VERSION 5.8 ;
BUSBITCHARS "[]" ;
DIVIDERCHAR "/" ;
UNITS
    DATABASE MICRONS 1000 ;
END UNITS

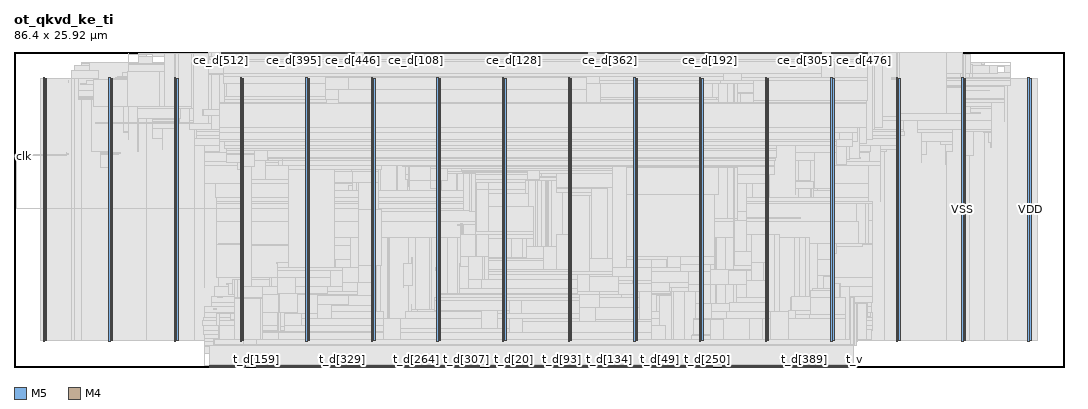
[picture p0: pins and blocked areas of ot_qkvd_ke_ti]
MACRO ot_qkvd_ke_ti
  FOREIGN ot_qkvd_ke_ti 0 0 ;
  CLASS BLOCK ;
  SIZE 86.4 BY 25.92 ;
  PIN ce_d[0]
    DIRECTION OUTPUT ;
    USE SIGNAL ;
    PORT
      LAYER M5 ;
        RECT  34.992 25.836 35.016 25.92 ;
    END
  END ce_d[0]
  PIN ce_d[100]
    DIRECTION OUTPUT ;
    USE SIGNAL ;
    PORT
      LAYER M5 ;
        RECT  32.304 25.836 32.328 25.92 ;
    END
  END ce_d[100]
  PIN ce_d[101]
    DIRECTION OUTPUT ;
    USE SIGNAL ;
    PORT
      LAYER M5 ;
        RECT  32.4 25.836 32.424 25.92 ;
    END
  END ce_d[101]
  PIN ce_d[102]
    DIRECTION OUTPUT ;
    USE SIGNAL ;
    PORT
      LAYER M5 ;
        RECT  32.496 25.836 32.52 25.92 ;
    END
  END ce_d[102]
  PIN ce_d[103]
    DIRECTION OUTPUT ;
    USE SIGNAL ;
    PORT
      LAYER M5 ;
        RECT  32.592 25.836 32.616 25.92 ;
    END
  END ce_d[103]
  PIN ce_d[104]
    DIRECTION OUTPUT ;
    USE SIGNAL ;
    PORT
      LAYER M5 ;
        RECT  32.688 25.836 32.712 25.92 ;
    END
  END ce_d[104]
  PIN ce_d[105]
    DIRECTION OUTPUT ;
    USE SIGNAL ;
    PORT
      LAYER M5 ;
        RECT  32.784 25.836 32.808 25.92 ;
    END
  END ce_d[105]
  PIN ce_d[106]
    DIRECTION OUTPUT ;
    USE SIGNAL ;
    PORT
      LAYER M5 ;
        RECT  32.88 25.836 32.904 25.92 ;
    END
  END ce_d[106]
  PIN ce_d[107]
    DIRECTION OUTPUT ;
    USE SIGNAL ;
    PORT
      LAYER M5 ;
        RECT  32.976 25.836 33 25.92 ;
    END
  END ce_d[107]
  PIN ce_d[108]
    DIRECTION OUTPUT ;
    USE SIGNAL ;
    PORT
      LAYER M5 ;
        RECT  33.072 25.836 33.096 25.92 ;
    END
  END ce_d[108]
  PIN ce_d[109]
    DIRECTION OUTPUT ;
    USE SIGNAL ;
    PORT
      LAYER M5 ;
        RECT  33.168 25.836 33.192 25.92 ;
    END
  END ce_d[109]
  PIN ce_d[10]
    DIRECTION OUTPUT ;
    USE SIGNAL ;
    PORT
      LAYER M5 ;
        RECT  35.952 25.836 35.976 25.92 ;
    END
  END ce_d[10]
  PIN ce_d[110]
    DIRECTION OUTPUT ;
    USE SIGNAL ;
    PORT
      LAYER M5 ;
        RECT  33.264 25.836 33.288 25.92 ;
    END
  END ce_d[110]
  PIN ce_d[111]
    DIRECTION OUTPUT ;
    USE SIGNAL ;
    PORT
      LAYER M5 ;
        RECT  33.36 25.836 33.384 25.92 ;
    END
  END ce_d[111]
  PIN ce_d[112]
    DIRECTION OUTPUT ;
    USE SIGNAL ;
    PORT
      LAYER M5 ;
        RECT  33.456 25.836 33.48 25.92 ;
    END
  END ce_d[112]
  PIN ce_d[113]
    DIRECTION OUTPUT ;
    USE SIGNAL ;
    PORT
      LAYER M5 ;
        RECT  33.552 25.836 33.576 25.92 ;
    END
  END ce_d[113]
  PIN ce_d[114]
    DIRECTION OUTPUT ;
    USE SIGNAL ;
    PORT
      LAYER M5 ;
        RECT  33.648 25.836 33.672 25.92 ;
    END
  END ce_d[114]
  PIN ce_d[115]
    DIRECTION OUTPUT ;
    USE SIGNAL ;
    PORT
      LAYER M5 ;
        RECT  33.744 25.836 33.768 25.92 ;
    END
  END ce_d[115]
  PIN ce_d[116]
    DIRECTION OUTPUT ;
    USE SIGNAL ;
    PORT
      LAYER M5 ;
        RECT  33.84 25.836 33.864 25.92 ;
    END
  END ce_d[116]
  PIN ce_d[117]
    DIRECTION OUTPUT ;
    USE SIGNAL ;
    PORT
      LAYER M5 ;
        RECT  33.936 25.836 33.96 25.92 ;
    END
  END ce_d[117]
  PIN ce_d[118]
    DIRECTION OUTPUT ;
    USE SIGNAL ;
    PORT
      LAYER M5 ;
        RECT  34.032 25.836 34.056 25.92 ;
    END
  END ce_d[118]
  PIN ce_d[119]
    DIRECTION OUTPUT ;
    USE SIGNAL ;
    PORT
      LAYER M5 ;
        RECT  34.128 25.836 34.152 25.92 ;
    END
  END ce_d[119]
  PIN ce_d[11]
    DIRECTION OUTPUT ;
    USE SIGNAL ;
    PORT
      LAYER M5 ;
        RECT  36.048 25.836 36.072 25.92 ;
    END
  END ce_d[11]
  PIN ce_d[120]
    DIRECTION OUTPUT ;
    USE SIGNAL ;
    PORT
      LAYER M5 ;
        RECT  34.224 25.836 34.248 25.92 ;
    END
  END ce_d[120]
  PIN ce_d[121]
    DIRECTION OUTPUT ;
    USE SIGNAL ;
    PORT
      LAYER M5 ;
        RECT  34.32 25.836 34.344 25.92 ;
    END
  END ce_d[121]
  PIN ce_d[122]
    DIRECTION OUTPUT ;
    USE SIGNAL ;
    PORT
      LAYER M5 ;
        RECT  34.416 25.836 34.44 25.92 ;
    END
  END ce_d[122]
  PIN ce_d[123]
    DIRECTION OUTPUT ;
    USE SIGNAL ;
    PORT
      LAYER M5 ;
        RECT  34.512 25.836 34.536 25.92 ;
    END
  END ce_d[123]
  PIN ce_d[124]
    DIRECTION OUTPUT ;
    USE SIGNAL ;
    PORT
      LAYER M5 ;
        RECT  34.608 25.836 34.632 25.92 ;
    END
  END ce_d[124]
  PIN ce_d[125]
    DIRECTION OUTPUT ;
    USE SIGNAL ;
    PORT
      LAYER M5 ;
        RECT  34.704 25.836 34.728 25.92 ;
    END
  END ce_d[125]
  PIN ce_d[126]
    DIRECTION OUTPUT ;
    USE SIGNAL ;
    PORT
      LAYER M5 ;
        RECT  34.8 25.836 34.824 25.92 ;
    END
  END ce_d[126]
  PIN ce_d[127]
    DIRECTION OUTPUT ;
    USE SIGNAL ;
    PORT
      LAYER M5 ;
        RECT  34.896 25.836 34.92 25.92 ;
    END
  END ce_d[127]
  PIN ce_d[128]
    DIRECTION OUTPUT ;
    USE SIGNAL ;
    PORT
      LAYER M5 ;
        RECT  41.136 25.836 41.16 25.92 ;
    END
  END ce_d[128]
  PIN ce_d[129]
    DIRECTION OUTPUT ;
    USE SIGNAL ;
    PORT
      LAYER M5 ;
        RECT  41.232 25.836 41.256 25.92 ;
    END
  END ce_d[129]
  PIN ce_d[12]
    DIRECTION OUTPUT ;
    USE SIGNAL ;
    PORT
      LAYER M5 ;
        RECT  36.144 25.836 36.168 25.92 ;
    END
  END ce_d[12]
  PIN ce_d[130]
    DIRECTION OUTPUT ;
    USE SIGNAL ;
    PORT
      LAYER M5 ;
        RECT  41.328 25.836 41.352 25.92 ;
    END
  END ce_d[130]
  PIN ce_d[131]
    DIRECTION OUTPUT ;
    USE SIGNAL ;
    PORT
      LAYER M5 ;
        RECT  41.424 25.836 41.448 25.92 ;
    END
  END ce_d[131]
  PIN ce_d[132]
    DIRECTION OUTPUT ;
    USE SIGNAL ;
    PORT
      LAYER M5 ;
        RECT  41.52 25.836 41.544 25.92 ;
    END
  END ce_d[132]
  PIN ce_d[133]
    DIRECTION OUTPUT ;
    USE SIGNAL ;
    PORT
      LAYER M5 ;
        RECT  41.616 25.836 41.64 25.92 ;
    END
  END ce_d[133]
  PIN ce_d[134]
    DIRECTION OUTPUT ;
    USE SIGNAL ;
    PORT
      LAYER M5 ;
        RECT  41.712 25.836 41.736 25.92 ;
    END
  END ce_d[134]
  PIN ce_d[135]
    DIRECTION OUTPUT ;
    USE SIGNAL ;
    PORT
      LAYER M5 ;
        RECT  41.808 25.836 41.832 25.92 ;
    END
  END ce_d[135]
  PIN ce_d[136]
    DIRECTION OUTPUT ;
    USE SIGNAL ;
    PORT
      LAYER M5 ;
        RECT  41.904 25.836 41.928 25.92 ;
    END
  END ce_d[136]
  PIN ce_d[137]
    DIRECTION OUTPUT ;
    USE SIGNAL ;
    PORT
      LAYER M5 ;
        RECT  42 25.836 42.024 25.92 ;
    END
  END ce_d[137]
  PIN ce_d[138]
    DIRECTION OUTPUT ;
    USE SIGNAL ;
    PORT
      LAYER M5 ;
        RECT  42.096 25.836 42.12 25.92 ;
    END
  END ce_d[138]
  PIN ce_d[139]
    DIRECTION OUTPUT ;
    USE SIGNAL ;
    PORT
      LAYER M5 ;
        RECT  42.192 25.836 42.216 25.92 ;
    END
  END ce_d[139]
  PIN ce_d[13]
    DIRECTION OUTPUT ;
    USE SIGNAL ;
    PORT
      LAYER M5 ;
        RECT  36.24 25.836 36.264 25.92 ;
    END
  END ce_d[13]
  PIN ce_d[140]
    DIRECTION OUTPUT ;
    USE SIGNAL ;
    PORT
      LAYER M5 ;
        RECT  42.288 25.836 42.312 25.92 ;
    END
  END ce_d[140]
  PIN ce_d[141]
    DIRECTION OUTPUT ;
    USE SIGNAL ;
    PORT
      LAYER M5 ;
        RECT  42.384 25.836 42.408 25.92 ;
    END
  END ce_d[141]
  PIN ce_d[142]
    DIRECTION OUTPUT ;
    USE SIGNAL ;
    PORT
      LAYER M5 ;
        RECT  42.48 25.836 42.504 25.92 ;
    END
  END ce_d[142]
  PIN ce_d[143]
    DIRECTION OUTPUT ;
    USE SIGNAL ;
    PORT
      LAYER M5 ;
        RECT  42.576 25.836 42.6 25.92 ;
    END
  END ce_d[143]
  PIN ce_d[144]
    DIRECTION OUTPUT ;
    USE SIGNAL ;
    PORT
      LAYER M5 ;
        RECT  42.672 25.836 42.696 25.92 ;
    END
  END ce_d[144]
  PIN ce_d[145]
    DIRECTION OUTPUT ;
    USE SIGNAL ;
    PORT
      LAYER M5 ;
        RECT  42.768 25.836 42.792 25.92 ;
    END
  END ce_d[145]
  PIN ce_d[146]
    DIRECTION OUTPUT ;
    USE SIGNAL ;
    PORT
      LAYER M5 ;
        RECT  42.864 25.836 42.888 25.92 ;
    END
  END ce_d[146]
  PIN ce_d[147]
    DIRECTION OUTPUT ;
    USE SIGNAL ;
    PORT
      LAYER M5 ;
        RECT  42.96 25.836 42.984 25.92 ;
    END
  END ce_d[147]
  PIN ce_d[148]
    DIRECTION OUTPUT ;
    USE SIGNAL ;
    PORT
      LAYER M5 ;
        RECT  43.056 25.836 43.08 25.92 ;
    END
  END ce_d[148]
  PIN ce_d[149]
    DIRECTION OUTPUT ;
    USE SIGNAL ;
    PORT
      LAYER M5 ;
        RECT  43.152 25.836 43.176 25.92 ;
    END
  END ce_d[149]
  PIN ce_d[14]
    DIRECTION OUTPUT ;
    USE SIGNAL ;
    PORT
      LAYER M5 ;
        RECT  36.336 25.836 36.36 25.92 ;
    END
  END ce_d[14]
  PIN ce_d[150]
    DIRECTION OUTPUT ;
    USE SIGNAL ;
    PORT
      LAYER M5 ;
        RECT  43.248 25.836 43.272 25.92 ;
    END
  END ce_d[150]
  PIN ce_d[151]
    DIRECTION OUTPUT ;
    USE SIGNAL ;
    PORT
      LAYER M5 ;
        RECT  43.344 25.836 43.368 25.92 ;
    END
  END ce_d[151]
  PIN ce_d[152]
    DIRECTION OUTPUT ;
    USE SIGNAL ;
    PORT
      LAYER M5 ;
        RECT  43.44 25.836 43.464 25.92 ;
    END
  END ce_d[152]
  PIN ce_d[153]
    DIRECTION OUTPUT ;
    USE SIGNAL ;
    PORT
      LAYER M5 ;
        RECT  43.536 25.836 43.56 25.92 ;
    END
  END ce_d[153]
  PIN ce_d[154]
    DIRECTION OUTPUT ;
    USE SIGNAL ;
    PORT
      LAYER M5 ;
        RECT  43.632 25.836 43.656 25.92 ;
    END
  END ce_d[154]
  PIN ce_d[155]
    DIRECTION OUTPUT ;
    USE SIGNAL ;
    PORT
      LAYER M5 ;
        RECT  43.728 25.836 43.752 25.92 ;
    END
  END ce_d[155]
  PIN ce_d[156]
    DIRECTION OUTPUT ;
    USE SIGNAL ;
    PORT
      LAYER M5 ;
        RECT  43.824 25.836 43.848 25.92 ;
    END
  END ce_d[156]
  PIN ce_d[157]
    DIRECTION OUTPUT ;
    USE SIGNAL ;
    PORT
      LAYER M5 ;
        RECT  43.92 25.836 43.944 25.92 ;
    END
  END ce_d[157]
  PIN ce_d[158]
    DIRECTION OUTPUT ;
    USE SIGNAL ;
    PORT
      LAYER M5 ;
        RECT  44.016 25.836 44.04 25.92 ;
    END
  END ce_d[158]
  PIN ce_d[159]
    DIRECTION OUTPUT ;
    USE SIGNAL ;
    PORT
      LAYER M5 ;
        RECT  44.112 25.836 44.136 25.92 ;
    END
  END ce_d[159]
  PIN ce_d[15]
    DIRECTION OUTPUT ;
    USE SIGNAL ;
    PORT
      LAYER M5 ;
        RECT  36.432 25.836 36.456 25.92 ;
    END
  END ce_d[15]
  PIN ce_d[160]
    DIRECTION OUTPUT ;
    USE SIGNAL ;
    PORT
      LAYER M5 ;
        RECT  28.848 25.836 28.872 25.92 ;
    END
  END ce_d[160]
  PIN ce_d[161]
    DIRECTION OUTPUT ;
    USE SIGNAL ;
    PORT
      LAYER M5 ;
        RECT  28.944 25.836 28.968 25.92 ;
    END
  END ce_d[161]
  PIN ce_d[162]
    DIRECTION OUTPUT ;
    USE SIGNAL ;
    PORT
      LAYER M5 ;
        RECT  29.04 25.836 29.064 25.92 ;
    END
  END ce_d[162]
  PIN ce_d[163]
    DIRECTION OUTPUT ;
    USE SIGNAL ;
    PORT
      LAYER M5 ;
        RECT  29.136 25.836 29.16 25.92 ;
    END
  END ce_d[163]
  PIN ce_d[164]
    DIRECTION OUTPUT ;
    USE SIGNAL ;
    PORT
      LAYER M5 ;
        RECT  29.232 25.836 29.256 25.92 ;
    END
  END ce_d[164]
  PIN ce_d[165]
    DIRECTION OUTPUT ;
    USE SIGNAL ;
    PORT
      LAYER M5 ;
        RECT  29.328 25.836 29.352 25.92 ;
    END
  END ce_d[165]
  PIN ce_d[166]
    DIRECTION OUTPUT ;
    USE SIGNAL ;
    PORT
      LAYER M5 ;
        RECT  29.424 25.836 29.448 25.92 ;
    END
  END ce_d[166]
  PIN ce_d[167]
    DIRECTION OUTPUT ;
    USE SIGNAL ;
    PORT
      LAYER M5 ;
        RECT  29.52 25.836 29.544 25.92 ;
    END
  END ce_d[167]
  PIN ce_d[168]
    DIRECTION OUTPUT ;
    USE SIGNAL ;
    PORT
      LAYER M5 ;
        RECT  29.616 25.836 29.64 25.92 ;
    END
  END ce_d[168]
  PIN ce_d[169]
    DIRECTION OUTPUT ;
    USE SIGNAL ;
    PORT
      LAYER M5 ;
        RECT  29.712 25.836 29.736 25.92 ;
    END
  END ce_d[169]
  PIN ce_d[16]
    DIRECTION OUTPUT ;
    USE SIGNAL ;
    PORT
      LAYER M5 ;
        RECT  36.528 25.836 36.552 25.92 ;
    END
  END ce_d[16]
  PIN ce_d[170]
    DIRECTION OUTPUT ;
    USE SIGNAL ;
    PORT
      LAYER M5 ;
        RECT  29.808 25.836 29.832 25.92 ;
    END
  END ce_d[170]
  PIN ce_d[171]
    DIRECTION OUTPUT ;
    USE SIGNAL ;
    PORT
      LAYER M5 ;
        RECT  29.904 25.836 29.928 25.92 ;
    END
  END ce_d[171]
  PIN ce_d[172]
    DIRECTION OUTPUT ;
    USE SIGNAL ;
    PORT
      LAYER M5 ;
        RECT  30 25.836 30.024 25.92 ;
    END
  END ce_d[172]
  PIN ce_d[173]
    DIRECTION OUTPUT ;
    USE SIGNAL ;
    PORT
      LAYER M5 ;
        RECT  30.096 25.836 30.12 25.92 ;
    END
  END ce_d[173]
  PIN ce_d[174]
    DIRECTION OUTPUT ;
    USE SIGNAL ;
    PORT
      LAYER M5 ;
        RECT  30.192 25.836 30.216 25.92 ;
    END
  END ce_d[174]
  PIN ce_d[175]
    DIRECTION OUTPUT ;
    USE SIGNAL ;
    PORT
      LAYER M5 ;
        RECT  30.288 25.836 30.312 25.92 ;
    END
  END ce_d[175]
  PIN ce_d[176]
    DIRECTION OUTPUT ;
    USE SIGNAL ;
    PORT
      LAYER M5 ;
        RECT  30.384 25.836 30.408 25.92 ;
    END
  END ce_d[176]
  PIN ce_d[177]
    DIRECTION OUTPUT ;
    USE SIGNAL ;
    PORT
      LAYER M5 ;
        RECT  30.48 25.836 30.504 25.92 ;
    END
  END ce_d[177]
  PIN ce_d[178]
    DIRECTION OUTPUT ;
    USE SIGNAL ;
    PORT
      LAYER M5 ;
        RECT  30.576 25.836 30.6 25.92 ;
    END
  END ce_d[178]
  PIN ce_d[179]
    DIRECTION OUTPUT ;
    USE SIGNAL ;
    PORT
      LAYER M5 ;
        RECT  30.672 25.836 30.696 25.92 ;
    END
  END ce_d[179]
  PIN ce_d[17]
    DIRECTION OUTPUT ;
    USE SIGNAL ;
    PORT
      LAYER M5 ;
        RECT  36.624 25.836 36.648 25.92 ;
    END
  END ce_d[17]
  PIN ce_d[180]
    DIRECTION OUTPUT ;
    USE SIGNAL ;
    PORT
      LAYER M5 ;
        RECT  30.768 25.836 30.792 25.92 ;
    END
  END ce_d[180]
  PIN ce_d[181]
    DIRECTION OUTPUT ;
    USE SIGNAL ;
    PORT
      LAYER M5 ;
        RECT  30.864 25.836 30.888 25.92 ;
    END
  END ce_d[181]
  PIN ce_d[182]
    DIRECTION OUTPUT ;
    USE SIGNAL ;
    PORT
      LAYER M5 ;
        RECT  30.96 25.836 30.984 25.92 ;
    END
  END ce_d[182]
  PIN ce_d[183]
    DIRECTION OUTPUT ;
    USE SIGNAL ;
    PORT
      LAYER M5 ;
        RECT  31.056 25.836 31.08 25.92 ;
    END
  END ce_d[183]
  PIN ce_d[184]
    DIRECTION OUTPUT ;
    USE SIGNAL ;
    PORT
      LAYER M5 ;
        RECT  31.152 25.836 31.176 25.92 ;
    END
  END ce_d[184]
  PIN ce_d[185]
    DIRECTION OUTPUT ;
    USE SIGNAL ;
    PORT
      LAYER M5 ;
        RECT  31.248 25.836 31.272 25.92 ;
    END
  END ce_d[185]
  PIN ce_d[186]
    DIRECTION OUTPUT ;
    USE SIGNAL ;
    PORT
      LAYER M5 ;
        RECT  31.344 25.836 31.368 25.92 ;
    END
  END ce_d[186]
  PIN ce_d[187]
    DIRECTION OUTPUT ;
    USE SIGNAL ;
    PORT
      LAYER M5 ;
        RECT  31.44 25.836 31.464 25.92 ;
    END
  END ce_d[187]
  PIN ce_d[188]
    DIRECTION OUTPUT ;
    USE SIGNAL ;
    PORT
      LAYER M5 ;
        RECT  31.536 25.836 31.56 25.92 ;
    END
  END ce_d[188]
  PIN ce_d[189]
    DIRECTION OUTPUT ;
    USE SIGNAL ;
    PORT
      LAYER M5 ;
        RECT  31.632 25.836 31.656 25.92 ;
    END
  END ce_d[189]
  PIN ce_d[18]
    DIRECTION OUTPUT ;
    USE SIGNAL ;
    PORT
      LAYER M5 ;
        RECT  36.72 25.836 36.744 25.92 ;
    END
  END ce_d[18]
  PIN ce_d[190]
    DIRECTION OUTPUT ;
    USE SIGNAL ;
    PORT
      LAYER M5 ;
        RECT  31.728 25.836 31.752 25.92 ;
    END
  END ce_d[190]
  PIN ce_d[191]
    DIRECTION OUTPUT ;
    USE SIGNAL ;
    PORT
      LAYER M5 ;
        RECT  31.824 25.836 31.848 25.92 ;
    END
  END ce_d[191]
  PIN ce_d[192]
    DIRECTION OUTPUT ;
    USE SIGNAL ;
    PORT
      LAYER M5 ;
        RECT  57.264 25.836 57.288 25.92 ;
    END
  END ce_d[192]
  PIN ce_d[193]
    DIRECTION OUTPUT ;
    USE SIGNAL ;
    PORT
      LAYER M5 ;
        RECT  57.36 25.836 57.384 25.92 ;
    END
  END ce_d[193]
  PIN ce_d[194]
    DIRECTION OUTPUT ;
    USE SIGNAL ;
    PORT
      LAYER M5 ;
        RECT  57.456 25.836 57.48 25.92 ;
    END
  END ce_d[194]
  PIN ce_d[195]
    DIRECTION OUTPUT ;
    USE SIGNAL ;
    PORT
      LAYER M5 ;
        RECT  57.552 25.836 57.576 25.92 ;
    END
  END ce_d[195]
  PIN ce_d[196]
    DIRECTION OUTPUT ;
    USE SIGNAL ;
    PORT
      LAYER M5 ;
        RECT  57.648 25.836 57.672 25.92 ;
    END
  END ce_d[196]
  PIN ce_d[197]
    DIRECTION OUTPUT ;
    USE SIGNAL ;
    PORT
      LAYER M5 ;
        RECT  57.744 25.836 57.768 25.92 ;
    END
  END ce_d[197]
  PIN ce_d[198]
    DIRECTION OUTPUT ;
    USE SIGNAL ;
    PORT
      LAYER M5 ;
        RECT  57.84 25.836 57.864 25.92 ;
    END
  END ce_d[198]
  PIN ce_d[199]
    DIRECTION OUTPUT ;
    USE SIGNAL ;
    PORT
      LAYER M5 ;
        RECT  57.936 25.836 57.96 25.92 ;
    END
  END ce_d[199]
  PIN ce_d[19]
    DIRECTION OUTPUT ;
    USE SIGNAL ;
    PORT
      LAYER M5 ;
        RECT  36.816 25.836 36.84 25.92 ;
    END
  END ce_d[19]
  PIN ce_d[1]
    DIRECTION OUTPUT ;
    USE SIGNAL ;
    PORT
      LAYER M5 ;
        RECT  35.088 25.836 35.112 25.92 ;
    END
  END ce_d[1]
  PIN ce_d[200]
    DIRECTION OUTPUT ;
    USE SIGNAL ;
    PORT
      LAYER M5 ;
        RECT  58.032 25.836 58.056 25.92 ;
    END
  END ce_d[200]
  PIN ce_d[201]
    DIRECTION OUTPUT ;
    USE SIGNAL ;
    PORT
      LAYER M5 ;
        RECT  58.128 25.836 58.152 25.92 ;
    END
  END ce_d[201]
  PIN ce_d[202]
    DIRECTION OUTPUT ;
    USE SIGNAL ;
    PORT
      LAYER M5 ;
        RECT  58.224 25.836 58.248 25.92 ;
    END
  END ce_d[202]
  PIN ce_d[203]
    DIRECTION OUTPUT ;
    USE SIGNAL ;
    PORT
      LAYER M5 ;
        RECT  58.32 25.836 58.344 25.92 ;
    END
  END ce_d[203]
  PIN ce_d[204]
    DIRECTION OUTPUT ;
    USE SIGNAL ;
    PORT
      LAYER M5 ;
        RECT  58.416 25.836 58.44 25.92 ;
    END
  END ce_d[204]
  PIN ce_d[205]
    DIRECTION OUTPUT ;
    USE SIGNAL ;
    PORT
      LAYER M5 ;
        RECT  58.512 25.836 58.536 25.92 ;
    END
  END ce_d[205]
  PIN ce_d[206]
    DIRECTION OUTPUT ;
    USE SIGNAL ;
    PORT
      LAYER M5 ;
        RECT  58.608 25.836 58.632 25.92 ;
    END
  END ce_d[206]
  PIN ce_d[207]
    DIRECTION OUTPUT ;
    USE SIGNAL ;
    PORT
      LAYER M5 ;
        RECT  58.704 25.836 58.728 25.92 ;
    END
  END ce_d[207]
  PIN ce_d[208]
    DIRECTION OUTPUT ;
    USE SIGNAL ;
    PORT
      LAYER M5 ;
        RECT  58.8 25.836 58.824 25.92 ;
    END
  END ce_d[208]
  PIN ce_d[209]
    DIRECTION OUTPUT ;
    USE SIGNAL ;
    PORT
      LAYER M5 ;
        RECT  58.896 25.836 58.92 25.92 ;
    END
  END ce_d[209]
  PIN ce_d[20]
    DIRECTION OUTPUT ;
    USE SIGNAL ;
    PORT
      LAYER M5 ;
        RECT  36.912 25.836 36.936 25.92 ;
    END
  END ce_d[20]
  PIN ce_d[210]
    DIRECTION OUTPUT ;
    USE SIGNAL ;
    PORT
      LAYER M5 ;
        RECT  58.992 25.836 59.016 25.92 ;
    END
  END ce_d[210]
  PIN ce_d[211]
    DIRECTION OUTPUT ;
    USE SIGNAL ;
    PORT
      LAYER M5 ;
        RECT  59.088 25.836 59.112 25.92 ;
    END
  END ce_d[211]
  PIN ce_d[212]
    DIRECTION OUTPUT ;
    USE SIGNAL ;
    PORT
      LAYER M5 ;
        RECT  59.184 25.836 59.208 25.92 ;
    END
  END ce_d[212]
  PIN ce_d[213]
    DIRECTION OUTPUT ;
    USE SIGNAL ;
    PORT
      LAYER M5 ;
        RECT  59.28 25.836 59.304 25.92 ;
    END
  END ce_d[213]
  PIN ce_d[214]
    DIRECTION OUTPUT ;
    USE SIGNAL ;
    PORT
      LAYER M5 ;
        RECT  59.376 25.836 59.4 25.92 ;
    END
  END ce_d[214]
  PIN ce_d[215]
    DIRECTION OUTPUT ;
    USE SIGNAL ;
    PORT
      LAYER M5 ;
        RECT  59.472 25.836 59.496 25.92 ;
    END
  END ce_d[215]
  PIN ce_d[216]
    DIRECTION OUTPUT ;
    USE SIGNAL ;
    PORT
      LAYER M5 ;
        RECT  59.568 25.836 59.592 25.92 ;
    END
  END ce_d[216]
  PIN ce_d[217]
    DIRECTION OUTPUT ;
    USE SIGNAL ;
    PORT
      LAYER M5 ;
        RECT  59.664 25.836 59.688 25.92 ;
    END
  END ce_d[217]
  PIN ce_d[218]
    DIRECTION OUTPUT ;
    USE SIGNAL ;
    PORT
      LAYER M5 ;
        RECT  59.76 25.836 59.784 25.92 ;
    END
  END ce_d[218]
  PIN ce_d[219]
    DIRECTION OUTPUT ;
    USE SIGNAL ;
    PORT
      LAYER M5 ;
        RECT  59.856 25.836 59.88 25.92 ;
    END
  END ce_d[219]
  PIN ce_d[21]
    DIRECTION OUTPUT ;
    USE SIGNAL ;
    PORT
      LAYER M5 ;
        RECT  37.008 25.836 37.032 25.92 ;
    END
  END ce_d[21]
  PIN ce_d[220]
    DIRECTION OUTPUT ;
    USE SIGNAL ;
    PORT
      LAYER M5 ;
        RECT  59.952 25.836 59.976 25.92 ;
    END
  END ce_d[220]
  PIN ce_d[221]
    DIRECTION OUTPUT ;
    USE SIGNAL ;
    PORT
      LAYER M5 ;
        RECT  60.048 25.836 60.072 25.92 ;
    END
  END ce_d[221]
  PIN ce_d[222]
    DIRECTION OUTPUT ;
    USE SIGNAL ;
    PORT
      LAYER M5 ;
        RECT  60.144 25.836 60.168 25.92 ;
    END
  END ce_d[222]
  PIN ce_d[223]
    DIRECTION OUTPUT ;
    USE SIGNAL ;
    PORT
      LAYER M5 ;
        RECT  60.24 25.836 60.264 25.92 ;
    END
  END ce_d[223]
  PIN ce_d[224]
    DIRECTION OUTPUT ;
    USE SIGNAL ;
    PORT
      LAYER M5 ;
        RECT  60.336 25.836 60.36 25.92 ;
    END
  END ce_d[224]
  PIN ce_d[225]
    DIRECTION OUTPUT ;
    USE SIGNAL ;
    PORT
      LAYER M5 ;
        RECT  60.432 25.836 60.456 25.92 ;
    END
  END ce_d[225]
  PIN ce_d[226]
    DIRECTION OUTPUT ;
    USE SIGNAL ;
    PORT
      LAYER M5 ;
        RECT  60.528 25.836 60.552 25.92 ;
    END
  END ce_d[226]
  PIN ce_d[227]
    DIRECTION OUTPUT ;
    USE SIGNAL ;
    PORT
      LAYER M5 ;
        RECT  60.624 25.836 60.648 25.92 ;
    END
  END ce_d[227]
  PIN ce_d[228]
    DIRECTION OUTPUT ;
    USE SIGNAL ;
    PORT
      LAYER M5 ;
        RECT  60.72 25.836 60.744 25.92 ;
    END
  END ce_d[228]
  PIN ce_d[229]
    DIRECTION OUTPUT ;
    USE SIGNAL ;
    PORT
      LAYER M5 ;
        RECT  60.816 25.836 60.84 25.92 ;
    END
  END ce_d[229]
  PIN ce_d[22]
    DIRECTION OUTPUT ;
    USE SIGNAL ;
    PORT
      LAYER M5 ;
        RECT  37.104 25.836 37.128 25.92 ;
    END
  END ce_d[22]
  PIN ce_d[230]
    DIRECTION OUTPUT ;
    USE SIGNAL ;
    PORT
      LAYER M5 ;
        RECT  60.912 25.836 60.936 25.92 ;
    END
  END ce_d[230]
  PIN ce_d[231]
    DIRECTION OUTPUT ;
    USE SIGNAL ;
    PORT
      LAYER M5 ;
        RECT  61.008 25.836 61.032 25.92 ;
    END
  END ce_d[231]
  PIN ce_d[232]
    DIRECTION OUTPUT ;
    USE SIGNAL ;
    PORT
      LAYER M5 ;
        RECT  61.104 25.836 61.128 25.92 ;
    END
  END ce_d[232]
  PIN ce_d[233]
    DIRECTION OUTPUT ;
    USE SIGNAL ;
    PORT
      LAYER M5 ;
        RECT  61.2 25.836 61.224 25.92 ;
    END
  END ce_d[233]
  PIN ce_d[234]
    DIRECTION OUTPUT ;
    USE SIGNAL ;
    PORT
      LAYER M5 ;
        RECT  61.296 25.836 61.32 25.92 ;
    END
  END ce_d[234]
  PIN ce_d[235]
    DIRECTION OUTPUT ;
    USE SIGNAL ;
    PORT
      LAYER M5 ;
        RECT  61.392 25.836 61.416 25.92 ;
    END
  END ce_d[235]
  PIN ce_d[236]
    DIRECTION OUTPUT ;
    USE SIGNAL ;
    PORT
      LAYER M5 ;
        RECT  61.488 25.836 61.512 25.92 ;
    END
  END ce_d[236]
  PIN ce_d[237]
    DIRECTION OUTPUT ;
    USE SIGNAL ;
    PORT
      LAYER M5 ;
        RECT  61.584 25.836 61.608 25.92 ;
    END
  END ce_d[237]
  PIN ce_d[238]
    DIRECTION OUTPUT ;
    USE SIGNAL ;
    PORT
      LAYER M5 ;
        RECT  61.68 25.836 61.704 25.92 ;
    END
  END ce_d[238]
  PIN ce_d[239]
    DIRECTION OUTPUT ;
    USE SIGNAL ;
    PORT
      LAYER M5 ;
        RECT  61.776 25.836 61.8 25.92 ;
    END
  END ce_d[239]
  PIN ce_d[23]
    DIRECTION OUTPUT ;
    USE SIGNAL ;
    PORT
      LAYER M5 ;
        RECT  37.2 25.836 37.224 25.92 ;
    END
  END ce_d[23]
  PIN ce_d[240]
    DIRECTION OUTPUT ;
    USE SIGNAL ;
    PORT
      LAYER M5 ;
        RECT  61.872 25.836 61.896 25.92 ;
    END
  END ce_d[240]
  PIN ce_d[241]
    DIRECTION OUTPUT ;
    USE SIGNAL ;
    PORT
      LAYER M5 ;
        RECT  61.968 25.836 61.992 25.92 ;
    END
  END ce_d[241]
  PIN ce_d[242]
    DIRECTION OUTPUT ;
    USE SIGNAL ;
    PORT
      LAYER M5 ;
        RECT  62.064 25.836 62.088 25.92 ;
    END
  END ce_d[242]
  PIN ce_d[243]
    DIRECTION OUTPUT ;
    USE SIGNAL ;
    PORT
      LAYER M5 ;
        RECT  62.16 25.836 62.184 25.92 ;
    END
  END ce_d[243]
  PIN ce_d[244]
    DIRECTION OUTPUT ;
    USE SIGNAL ;
    PORT
      LAYER M5 ;
        RECT  62.256 25.836 62.28 25.92 ;
    END
  END ce_d[244]
  PIN ce_d[245]
    DIRECTION OUTPUT ;
    USE SIGNAL ;
    PORT
      LAYER M5 ;
        RECT  62.352 25.836 62.376 25.92 ;
    END
  END ce_d[245]
  PIN ce_d[246]
    DIRECTION OUTPUT ;
    USE SIGNAL ;
    PORT
      LAYER M5 ;
        RECT  62.448 25.836 62.472 25.92 ;
    END
  END ce_d[246]
  PIN ce_d[247]
    DIRECTION OUTPUT ;
    USE SIGNAL ;
    PORT
      LAYER M5 ;
        RECT  62.544 25.836 62.568 25.92 ;
    END
  END ce_d[247]
  PIN ce_d[248]
    DIRECTION OUTPUT ;
    USE SIGNAL ;
    PORT
      LAYER M5 ;
        RECT  62.64 25.836 62.664 25.92 ;
    END
  END ce_d[248]
  PIN ce_d[249]
    DIRECTION OUTPUT ;
    USE SIGNAL ;
    PORT
      LAYER M5 ;
        RECT  62.736 25.836 62.76 25.92 ;
    END
  END ce_d[249]
  PIN ce_d[24]
    DIRECTION OUTPUT ;
    USE SIGNAL ;
    PORT
      LAYER M5 ;
        RECT  37.296 25.836 37.32 25.92 ;
    END
  END ce_d[24]
  PIN ce_d[250]
    DIRECTION OUTPUT ;
    USE SIGNAL ;
    PORT
      LAYER M5 ;
        RECT  62.832 25.836 62.856 25.92 ;
    END
  END ce_d[250]
  PIN ce_d[251]
    DIRECTION OUTPUT ;
    USE SIGNAL ;
    PORT
      LAYER M5 ;
        RECT  62.928 25.836 62.952 25.92 ;
    END
  END ce_d[251]
  PIN ce_d[252]
    DIRECTION OUTPUT ;
    USE SIGNAL ;
    PORT
      LAYER M5 ;
        RECT  63.024 25.836 63.048 25.92 ;
    END
  END ce_d[252]
  PIN ce_d[253]
    DIRECTION OUTPUT ;
    USE SIGNAL ;
    PORT
      LAYER M5 ;
        RECT  63.12 25.836 63.144 25.92 ;
    END
  END ce_d[253]
  PIN ce_d[254]
    DIRECTION OUTPUT ;
    USE SIGNAL ;
    PORT
      LAYER M5 ;
        RECT  63.216 25.836 63.24 25.92 ;
    END
  END ce_d[254]
  PIN ce_d[255]
    DIRECTION OUTPUT ;
    USE SIGNAL ;
    PORT
      LAYER M5 ;
        RECT  63.312 25.836 63.336 25.92 ;
    END
  END ce_d[255]
  PIN ce_d[256]
    DIRECTION OUTPUT ;
    USE SIGNAL ;
    PORT
      LAYER M5 ;
        RECT  54.192 25.836 54.216 25.92 ;
    END
  END ce_d[256]
  PIN ce_d[257]
    DIRECTION OUTPUT ;
    USE SIGNAL ;
    PORT
      LAYER M5 ;
        RECT  54.288 25.836 54.312 25.92 ;
    END
  END ce_d[257]
  PIN ce_d[258]
    DIRECTION OUTPUT ;
    USE SIGNAL ;
    PORT
      LAYER M5 ;
        RECT  54.384 25.836 54.408 25.92 ;
    END
  END ce_d[258]
  PIN ce_d[259]
    DIRECTION OUTPUT ;
    USE SIGNAL ;
    PORT
      LAYER M5 ;
        RECT  54.48 25.836 54.504 25.92 ;
    END
  END ce_d[259]
  PIN ce_d[25]
    DIRECTION OUTPUT ;
    USE SIGNAL ;
    PORT
      LAYER M5 ;
        RECT  37.392 25.836 37.416 25.92 ;
    END
  END ce_d[25]
  PIN ce_d[260]
    DIRECTION OUTPUT ;
    USE SIGNAL ;
    PORT
      LAYER M5 ;
        RECT  54.576 25.836 54.6 25.92 ;
    END
  END ce_d[260]
  PIN ce_d[261]
    DIRECTION OUTPUT ;
    USE SIGNAL ;
    PORT
      LAYER M5 ;
        RECT  54.672 25.836 54.696 25.92 ;
    END
  END ce_d[261]
  PIN ce_d[262]
    DIRECTION OUTPUT ;
    USE SIGNAL ;
    PORT
      LAYER M5 ;
        RECT  54.768 25.836 54.792 25.92 ;
    END
  END ce_d[262]
  PIN ce_d[263]
    DIRECTION OUTPUT ;
    USE SIGNAL ;
    PORT
      LAYER M5 ;
        RECT  54.864 25.836 54.888 25.92 ;
    END
  END ce_d[263]
  PIN ce_d[264]
    DIRECTION OUTPUT ;
    USE SIGNAL ;
    PORT
      LAYER M5 ;
        RECT  54.96 25.836 54.984 25.92 ;
    END
  END ce_d[264]
  PIN ce_d[265]
    DIRECTION OUTPUT ;
    USE SIGNAL ;
    PORT
      LAYER M5 ;
        RECT  55.056 25.836 55.08 25.92 ;
    END
  END ce_d[265]
  PIN ce_d[266]
    DIRECTION OUTPUT ;
    USE SIGNAL ;
    PORT
      LAYER M5 ;
        RECT  55.152 25.836 55.176 25.92 ;
    END
  END ce_d[266]
  PIN ce_d[267]
    DIRECTION OUTPUT ;
    USE SIGNAL ;
    PORT
      LAYER M5 ;
        RECT  55.248 25.836 55.272 25.92 ;
    END
  END ce_d[267]
  PIN ce_d[268]
    DIRECTION OUTPUT ;
    USE SIGNAL ;
    PORT
      LAYER M5 ;
        RECT  55.344 25.836 55.368 25.92 ;
    END
  END ce_d[268]
  PIN ce_d[269]
    DIRECTION OUTPUT ;
    USE SIGNAL ;
    PORT
      LAYER M5 ;
        RECT  55.44 25.836 55.464 25.92 ;
    END
  END ce_d[269]
  PIN ce_d[26]
    DIRECTION OUTPUT ;
    USE SIGNAL ;
    PORT
      LAYER M5 ;
        RECT  37.488 25.836 37.512 25.92 ;
    END
  END ce_d[26]
  PIN ce_d[270]
    DIRECTION OUTPUT ;
    USE SIGNAL ;
    PORT
      LAYER M5 ;
        RECT  55.536 25.836 55.56 25.92 ;
    END
  END ce_d[270]
  PIN ce_d[271]
    DIRECTION OUTPUT ;
    USE SIGNAL ;
    PORT
      LAYER M5 ;
        RECT  55.632 25.836 55.656 25.92 ;
    END
  END ce_d[271]
  PIN ce_d[272]
    DIRECTION OUTPUT ;
    USE SIGNAL ;
    PORT
      LAYER M5 ;
        RECT  55.728 25.836 55.752 25.92 ;
    END
  END ce_d[272]
  PIN ce_d[273]
    DIRECTION OUTPUT ;
    USE SIGNAL ;
    PORT
      LAYER M5 ;
        RECT  55.824 25.836 55.848 25.92 ;
    END
  END ce_d[273]
  PIN ce_d[274]
    DIRECTION OUTPUT ;
    USE SIGNAL ;
    PORT
      LAYER M5 ;
        RECT  55.92 25.836 55.944 25.92 ;
    END
  END ce_d[274]
  PIN ce_d[275]
    DIRECTION OUTPUT ;
    USE SIGNAL ;
    PORT
      LAYER M5 ;
        RECT  56.016 25.836 56.04 25.92 ;
    END
  END ce_d[275]
  PIN ce_d[276]
    DIRECTION OUTPUT ;
    USE SIGNAL ;
    PORT
      LAYER M5 ;
        RECT  56.112 25.836 56.136 25.92 ;
    END
  END ce_d[276]
  PIN ce_d[277]
    DIRECTION OUTPUT ;
    USE SIGNAL ;
    PORT
      LAYER M5 ;
        RECT  56.208 25.836 56.232 25.92 ;
    END
  END ce_d[277]
  PIN ce_d[278]
    DIRECTION OUTPUT ;
    USE SIGNAL ;
    PORT
      LAYER M5 ;
        RECT  56.304 25.836 56.328 25.92 ;
    END
  END ce_d[278]
  PIN ce_d[279]
    DIRECTION OUTPUT ;
    USE SIGNAL ;
    PORT
      LAYER M5 ;
        RECT  56.4 25.836 56.424 25.92 ;
    END
  END ce_d[279]
  PIN ce_d[27]
    DIRECTION OUTPUT ;
    USE SIGNAL ;
    PORT
      LAYER M5 ;
        RECT  37.584 25.836 37.608 25.92 ;
    END
  END ce_d[27]
  PIN ce_d[280]
    DIRECTION OUTPUT ;
    USE SIGNAL ;
    PORT
      LAYER M5 ;
        RECT  56.496 25.836 56.52 25.92 ;
    END
  END ce_d[280]
  PIN ce_d[281]
    DIRECTION OUTPUT ;
    USE SIGNAL ;
    PORT
      LAYER M5 ;
        RECT  56.592 25.836 56.616 25.92 ;
    END
  END ce_d[281]
  PIN ce_d[282]
    DIRECTION OUTPUT ;
    USE SIGNAL ;
    PORT
      LAYER M5 ;
        RECT  56.688 25.836 56.712 25.92 ;
    END
  END ce_d[282]
  PIN ce_d[283]
    DIRECTION OUTPUT ;
    USE SIGNAL ;
    PORT
      LAYER M5 ;
        RECT  56.784 25.836 56.808 25.92 ;
    END
  END ce_d[283]
  PIN ce_d[284]
    DIRECTION OUTPUT ;
    USE SIGNAL ;
    PORT
      LAYER M5 ;
        RECT  56.88 25.836 56.904 25.92 ;
    END
  END ce_d[284]
  PIN ce_d[285]
    DIRECTION OUTPUT ;
    USE SIGNAL ;
    PORT
      LAYER M5 ;
        RECT  56.976 25.836 57 25.92 ;
    END
  END ce_d[285]
  PIN ce_d[286]
    DIRECTION OUTPUT ;
    USE SIGNAL ;
    PORT
      LAYER M5 ;
        RECT  57.072 25.836 57.096 25.92 ;
    END
  END ce_d[286]
  PIN ce_d[287]
    DIRECTION OUTPUT ;
    USE SIGNAL ;
    PORT
      LAYER M5 ;
        RECT  57.168 25.836 57.192 25.92 ;
    END
  END ce_d[287]
  PIN ce_d[288]
    DIRECTION OUTPUT ;
    USE SIGNAL ;
    PORT
      LAYER M5 ;
        RECT  63.408 25.836 63.432 25.92 ;
    END
  END ce_d[288]
  PIN ce_d[289]
    DIRECTION OUTPUT ;
    USE SIGNAL ;
    PORT
      LAYER M5 ;
        RECT  63.504 25.836 63.528 25.92 ;
    END
  END ce_d[289]
  PIN ce_d[28]
    DIRECTION OUTPUT ;
    USE SIGNAL ;
    PORT
      LAYER M5 ;
        RECT  37.68 25.836 37.704 25.92 ;
    END
  END ce_d[28]
  PIN ce_d[290]
    DIRECTION OUTPUT ;
    USE SIGNAL ;
    PORT
      LAYER M5 ;
        RECT  63.6 25.836 63.624 25.92 ;
    END
  END ce_d[290]
  PIN ce_d[291]
    DIRECTION OUTPUT ;
    USE SIGNAL ;
    PORT
      LAYER M5 ;
        RECT  63.696 25.836 63.72 25.92 ;
    END
  END ce_d[291]
  PIN ce_d[292]
    DIRECTION OUTPUT ;
    USE SIGNAL ;
    PORT
      LAYER M5 ;
        RECT  63.792 25.836 63.816 25.92 ;
    END
  END ce_d[292]
  PIN ce_d[293]
    DIRECTION OUTPUT ;
    USE SIGNAL ;
    PORT
      LAYER M5 ;
        RECT  63.888 25.836 63.912 25.92 ;
    END
  END ce_d[293]
  PIN ce_d[294]
    DIRECTION OUTPUT ;
    USE SIGNAL ;
    PORT
      LAYER M5 ;
        RECT  63.984 25.836 64.008 25.92 ;
    END
  END ce_d[294]
  PIN ce_d[295]
    DIRECTION OUTPUT ;
    USE SIGNAL ;
    PORT
      LAYER M5 ;
        RECT  64.08 25.836 64.104 25.92 ;
    END
  END ce_d[295]
  PIN ce_d[296]
    DIRECTION OUTPUT ;
    USE SIGNAL ;
    PORT
      LAYER M5 ;
        RECT  64.176 25.836 64.2 25.92 ;
    END
  END ce_d[296]
  PIN ce_d[297]
    DIRECTION OUTPUT ;
    USE SIGNAL ;
    PORT
      LAYER M5 ;
        RECT  64.272 25.836 64.296 25.92 ;
    END
  END ce_d[297]
  PIN ce_d[298]
    DIRECTION OUTPUT ;
    USE SIGNAL ;
    PORT
      LAYER M5 ;
        RECT  64.368 25.836 64.392 25.92 ;
    END
  END ce_d[298]
  PIN ce_d[299]
    DIRECTION OUTPUT ;
    USE SIGNAL ;
    PORT
      LAYER M5 ;
        RECT  64.464 25.836 64.488 25.92 ;
    END
  END ce_d[299]
  PIN ce_d[29]
    DIRECTION OUTPUT ;
    USE SIGNAL ;
    PORT
      LAYER M5 ;
        RECT  37.776 25.836 37.8 25.92 ;
    END
  END ce_d[29]
  PIN ce_d[2]
    DIRECTION OUTPUT ;
    USE SIGNAL ;
    PORT
      LAYER M5 ;
        RECT  35.184 25.836 35.208 25.92 ;
    END
  END ce_d[2]
  PIN ce_d[300]
    DIRECTION OUTPUT ;
    USE SIGNAL ;
    PORT
      LAYER M5 ;
        RECT  64.56 25.836 64.584 25.92 ;
    END
  END ce_d[300]
  PIN ce_d[301]
    DIRECTION OUTPUT ;
    USE SIGNAL ;
    PORT
      LAYER M5 ;
        RECT  64.656 25.836 64.68 25.92 ;
    END
  END ce_d[301]
  PIN ce_d[302]
    DIRECTION OUTPUT ;
    USE SIGNAL ;
    PORT
      LAYER M5 ;
        RECT  64.752 25.836 64.776 25.92 ;
    END
  END ce_d[302]
  PIN ce_d[303]
    DIRECTION OUTPUT ;
    USE SIGNAL ;
    PORT
      LAYER M5 ;
        RECT  64.848 25.836 64.872 25.92 ;
    END
  END ce_d[303]
  PIN ce_d[304]
    DIRECTION OUTPUT ;
    USE SIGNAL ;
    PORT
      LAYER M5 ;
        RECT  64.944 25.836 64.968 25.92 ;
    END
  END ce_d[304]
  PIN ce_d[305]
    DIRECTION OUTPUT ;
    USE SIGNAL ;
    PORT
      LAYER M5 ;
        RECT  65.04 25.836 65.064 25.92 ;
    END
  END ce_d[305]
  PIN ce_d[306]
    DIRECTION OUTPUT ;
    USE SIGNAL ;
    PORT
      LAYER M5 ;
        RECT  65.136 25.836 65.16 25.92 ;
    END
  END ce_d[306]
  PIN ce_d[307]
    DIRECTION OUTPUT ;
    USE SIGNAL ;
    PORT
      LAYER M5 ;
        RECT  65.232 25.836 65.256 25.92 ;
    END
  END ce_d[307]
  PIN ce_d[308]
    DIRECTION OUTPUT ;
    USE SIGNAL ;
    PORT
      LAYER M5 ;
        RECT  65.328 25.836 65.352 25.92 ;
    END
  END ce_d[308]
  PIN ce_d[309]
    DIRECTION OUTPUT ;
    USE SIGNAL ;
    PORT
      LAYER M5 ;
        RECT  65.424 25.836 65.448 25.92 ;
    END
  END ce_d[309]
  PIN ce_d[30]
    DIRECTION OUTPUT ;
    USE SIGNAL ;
    PORT
      LAYER M5 ;
        RECT  37.872 25.836 37.896 25.92 ;
    END
  END ce_d[30]
  PIN ce_d[310]
    DIRECTION OUTPUT ;
    USE SIGNAL ;
    PORT
      LAYER M5 ;
        RECT  65.52 25.836 65.544 25.92 ;
    END
  END ce_d[310]
  PIN ce_d[311]
    DIRECTION OUTPUT ;
    USE SIGNAL ;
    PORT
      LAYER M5 ;
        RECT  65.616 25.836 65.64 25.92 ;
    END
  END ce_d[311]
  PIN ce_d[312]
    DIRECTION OUTPUT ;
    USE SIGNAL ;
    PORT
      LAYER M5 ;
        RECT  65.712 25.836 65.736 25.92 ;
    END
  END ce_d[312]
  PIN ce_d[313]
    DIRECTION OUTPUT ;
    USE SIGNAL ;
    PORT
      LAYER M5 ;
        RECT  65.808 25.836 65.832 25.92 ;
    END
  END ce_d[313]
  PIN ce_d[314]
    DIRECTION OUTPUT ;
    USE SIGNAL ;
    PORT
      LAYER M5 ;
        RECT  65.904 25.836 65.928 25.92 ;
    END
  END ce_d[314]
  PIN ce_d[315]
    DIRECTION OUTPUT ;
    USE SIGNAL ;
    PORT
      LAYER M5 ;
        RECT  66 25.836 66.024 25.92 ;
    END
  END ce_d[315]
  PIN ce_d[316]
    DIRECTION OUTPUT ;
    USE SIGNAL ;
    PORT
      LAYER M5 ;
        RECT  66.096 25.836 66.12 25.92 ;
    END
  END ce_d[316]
  PIN ce_d[317]
    DIRECTION OUTPUT ;
    USE SIGNAL ;
    PORT
      LAYER M5 ;
        RECT  66.192 25.836 66.216 25.92 ;
    END
  END ce_d[317]
  PIN ce_d[318]
    DIRECTION OUTPUT ;
    USE SIGNAL ;
    PORT
      LAYER M5 ;
        RECT  66.288 25.836 66.312 25.92 ;
    END
  END ce_d[318]
  PIN ce_d[319]
    DIRECTION OUTPUT ;
    USE SIGNAL ;
    PORT
      LAYER M5 ;
        RECT  66.384 25.836 66.408 25.92 ;
    END
  END ce_d[319]
  PIN ce_d[31]
    DIRECTION OUTPUT ;
    USE SIGNAL ;
    PORT
      LAYER M5 ;
        RECT  37.968 25.836 37.992 25.92 ;
    END
  END ce_d[31]
  PIN ce_d[320]
    DIRECTION OUTPUT ;
    USE SIGNAL ;
    PORT
      LAYER M5 ;
        RECT  51.12 25.836 51.144 25.92 ;
    END
  END ce_d[320]
  PIN ce_d[321]
    DIRECTION OUTPUT ;
    USE SIGNAL ;
    PORT
      LAYER M5 ;
        RECT  51.216 25.836 51.24 25.92 ;
    END
  END ce_d[321]
  PIN ce_d[322]
    DIRECTION OUTPUT ;
    USE SIGNAL ;
    PORT
      LAYER M5 ;
        RECT  51.312 25.836 51.336 25.92 ;
    END
  END ce_d[322]
  PIN ce_d[323]
    DIRECTION OUTPUT ;
    USE SIGNAL ;
    PORT
      LAYER M5 ;
        RECT  51.408 25.836 51.432 25.92 ;
    END
  END ce_d[323]
  PIN ce_d[324]
    DIRECTION OUTPUT ;
    USE SIGNAL ;
    PORT
      LAYER M5 ;
        RECT  51.504 25.836 51.528 25.92 ;
    END
  END ce_d[324]
  PIN ce_d[325]
    DIRECTION OUTPUT ;
    USE SIGNAL ;
    PORT
      LAYER M5 ;
        RECT  51.6 25.836 51.624 25.92 ;
    END
  END ce_d[325]
  PIN ce_d[326]
    DIRECTION OUTPUT ;
    USE SIGNAL ;
    PORT
      LAYER M5 ;
        RECT  51.696 25.836 51.72 25.92 ;
    END
  END ce_d[326]
  PIN ce_d[327]
    DIRECTION OUTPUT ;
    USE SIGNAL ;
    PORT
      LAYER M5 ;
        RECT  51.792 25.836 51.816 25.92 ;
    END
  END ce_d[327]
  PIN ce_d[328]
    DIRECTION OUTPUT ;
    USE SIGNAL ;
    PORT
      LAYER M5 ;
        RECT  51.888 25.836 51.912 25.92 ;
    END
  END ce_d[328]
  PIN ce_d[329]
    DIRECTION OUTPUT ;
    USE SIGNAL ;
    PORT
      LAYER M5 ;
        RECT  51.984 25.836 52.008 25.92 ;
    END
  END ce_d[329]
  PIN ce_d[32]
    DIRECTION OUTPUT ;
    USE SIGNAL ;
    PORT
      LAYER M5 ;
        RECT  44.208 25.836 44.232 25.92 ;
    END
  END ce_d[32]
  PIN ce_d[330]
    DIRECTION OUTPUT ;
    USE SIGNAL ;
    PORT
      LAYER M5 ;
        RECT  52.08 25.836 52.104 25.92 ;
    END
  END ce_d[330]
  PIN ce_d[331]
    DIRECTION OUTPUT ;
    USE SIGNAL ;
    PORT
      LAYER M5 ;
        RECT  52.176 25.836 52.2 25.92 ;
    END
  END ce_d[331]
  PIN ce_d[332]
    DIRECTION OUTPUT ;
    USE SIGNAL ;
    PORT
      LAYER M5 ;
        RECT  52.272 25.836 52.296 25.92 ;
    END
  END ce_d[332]
  PIN ce_d[333]
    DIRECTION OUTPUT ;
    USE SIGNAL ;
    PORT
      LAYER M5 ;
        RECT  52.368 25.836 52.392 25.92 ;
    END
  END ce_d[333]
  PIN ce_d[334]
    DIRECTION OUTPUT ;
    USE SIGNAL ;
    PORT
      LAYER M5 ;
        RECT  52.464 25.836 52.488 25.92 ;
    END
  END ce_d[334]
  PIN ce_d[335]
    DIRECTION OUTPUT ;
    USE SIGNAL ;
    PORT
      LAYER M5 ;
        RECT  52.56 25.836 52.584 25.92 ;
    END
  END ce_d[335]
  PIN ce_d[336]
    DIRECTION OUTPUT ;
    USE SIGNAL ;
    PORT
      LAYER M5 ;
        RECT  52.656 25.836 52.68 25.92 ;
    END
  END ce_d[336]
  PIN ce_d[337]
    DIRECTION OUTPUT ;
    USE SIGNAL ;
    PORT
      LAYER M5 ;
        RECT  52.752 25.836 52.776 25.92 ;
    END
  END ce_d[337]
  PIN ce_d[338]
    DIRECTION OUTPUT ;
    USE SIGNAL ;
    PORT
      LAYER M5 ;
        RECT  52.848 25.836 52.872 25.92 ;
    END
  END ce_d[338]
  PIN ce_d[339]
    DIRECTION OUTPUT ;
    USE SIGNAL ;
    PORT
      LAYER M5 ;
        RECT  52.944 25.836 52.968 25.92 ;
    END
  END ce_d[339]
  PIN ce_d[33]
    DIRECTION OUTPUT ;
    USE SIGNAL ;
    PORT
      LAYER M5 ;
        RECT  44.304 25.836 44.328 25.92 ;
    END
  END ce_d[33]
  PIN ce_d[340]
    DIRECTION OUTPUT ;
    USE SIGNAL ;
    PORT
      LAYER M5 ;
        RECT  53.04 25.836 53.064 25.92 ;
    END
  END ce_d[340]
  PIN ce_d[341]
    DIRECTION OUTPUT ;
    USE SIGNAL ;
    PORT
      LAYER M5 ;
        RECT  53.136 25.836 53.16 25.92 ;
    END
  END ce_d[341]
  PIN ce_d[342]
    DIRECTION OUTPUT ;
    USE SIGNAL ;
    PORT
      LAYER M5 ;
        RECT  53.232 25.836 53.256 25.92 ;
    END
  END ce_d[342]
  PIN ce_d[343]
    DIRECTION OUTPUT ;
    USE SIGNAL ;
    PORT
      LAYER M5 ;
        RECT  53.328 25.836 53.352 25.92 ;
    END
  END ce_d[343]
  PIN ce_d[344]
    DIRECTION OUTPUT ;
    USE SIGNAL ;
    PORT
      LAYER M5 ;
        RECT  53.424 25.836 53.448 25.92 ;
    END
  END ce_d[344]
  PIN ce_d[345]
    DIRECTION OUTPUT ;
    USE SIGNAL ;
    PORT
      LAYER M5 ;
        RECT  53.52 25.836 53.544 25.92 ;
    END
  END ce_d[345]
  PIN ce_d[346]
    DIRECTION OUTPUT ;
    USE SIGNAL ;
    PORT
      LAYER M5 ;
        RECT  53.616 25.836 53.64 25.92 ;
    END
  END ce_d[346]
  PIN ce_d[347]
    DIRECTION OUTPUT ;
    USE SIGNAL ;
    PORT
      LAYER M5 ;
        RECT  53.712 25.836 53.736 25.92 ;
    END
  END ce_d[347]
  PIN ce_d[348]
    DIRECTION OUTPUT ;
    USE SIGNAL ;
    PORT
      LAYER M5 ;
        RECT  53.808 25.836 53.832 25.92 ;
    END
  END ce_d[348]
  PIN ce_d[349]
    DIRECTION OUTPUT ;
    USE SIGNAL ;
    PORT
      LAYER M5 ;
        RECT  53.904 25.836 53.928 25.92 ;
    END
  END ce_d[349]
  PIN ce_d[34]
    DIRECTION OUTPUT ;
    USE SIGNAL ;
    PORT
      LAYER M5 ;
        RECT  44.4 25.836 44.424 25.92 ;
    END
  END ce_d[34]
  PIN ce_d[350]
    DIRECTION OUTPUT ;
    USE SIGNAL ;
    PORT
      LAYER M5 ;
        RECT  54 25.836 54.024 25.92 ;
    END
  END ce_d[350]
  PIN ce_d[351]
    DIRECTION OUTPUT ;
    USE SIGNAL ;
    PORT
      LAYER M5 ;
        RECT  54.096 25.836 54.12 25.92 ;
    END
  END ce_d[351]
  PIN ce_d[352]
    DIRECTION OUTPUT ;
    USE SIGNAL ;
    PORT
      LAYER M5 ;
        RECT  48.048 25.836 48.072 25.92 ;
    END
  END ce_d[352]
  PIN ce_d[353]
    DIRECTION OUTPUT ;
    USE SIGNAL ;
    PORT
      LAYER M5 ;
        RECT  48.144 25.836 48.168 25.92 ;
    END
  END ce_d[353]
  PIN ce_d[354]
    DIRECTION OUTPUT ;
    USE SIGNAL ;
    PORT
      LAYER M5 ;
        RECT  48.24 25.836 48.264 25.92 ;
    END
  END ce_d[354]
  PIN ce_d[355]
    DIRECTION OUTPUT ;
    USE SIGNAL ;
    PORT
      LAYER M5 ;
        RECT  48.336 25.836 48.36 25.92 ;
    END
  END ce_d[355]
  PIN ce_d[356]
    DIRECTION OUTPUT ;
    USE SIGNAL ;
    PORT
      LAYER M5 ;
        RECT  48.432 25.836 48.456 25.92 ;
    END
  END ce_d[356]
  PIN ce_d[357]
    DIRECTION OUTPUT ;
    USE SIGNAL ;
    PORT
      LAYER M5 ;
        RECT  48.528 25.836 48.552 25.92 ;
    END
  END ce_d[357]
  PIN ce_d[358]
    DIRECTION OUTPUT ;
    USE SIGNAL ;
    PORT
      LAYER M5 ;
        RECT  48.624 25.836 48.648 25.92 ;
    END
  END ce_d[358]
  PIN ce_d[359]
    DIRECTION OUTPUT ;
    USE SIGNAL ;
    PORT
      LAYER M5 ;
        RECT  48.72 25.836 48.744 25.92 ;
    END
  END ce_d[359]
  PIN ce_d[35]
    DIRECTION OUTPUT ;
    USE SIGNAL ;
    PORT
      LAYER M5 ;
        RECT  44.496 25.836 44.52 25.92 ;
    END
  END ce_d[35]
  PIN ce_d[360]
    DIRECTION OUTPUT ;
    USE SIGNAL ;
    PORT
      LAYER M5 ;
        RECT  48.816 25.836 48.84 25.92 ;
    END
  END ce_d[360]
  PIN ce_d[361]
    DIRECTION OUTPUT ;
    USE SIGNAL ;
    PORT
      LAYER M5 ;
        RECT  48.912 25.836 48.936 25.92 ;
    END
  END ce_d[361]
  PIN ce_d[362]
    DIRECTION OUTPUT ;
    USE SIGNAL ;
    PORT
      LAYER M5 ;
        RECT  49.008 25.836 49.032 25.92 ;
    END
  END ce_d[362]
  PIN ce_d[363]
    DIRECTION OUTPUT ;
    USE SIGNAL ;
    PORT
      LAYER M5 ;
        RECT  49.104 25.836 49.128 25.92 ;
    END
  END ce_d[363]
  PIN ce_d[364]
    DIRECTION OUTPUT ;
    USE SIGNAL ;
    PORT
      LAYER M5 ;
        RECT  49.2 25.836 49.224 25.92 ;
    END
  END ce_d[364]
  PIN ce_d[365]
    DIRECTION OUTPUT ;
    USE SIGNAL ;
    PORT
      LAYER M5 ;
        RECT  49.296 25.836 49.32 25.92 ;
    END
  END ce_d[365]
  PIN ce_d[366]
    DIRECTION OUTPUT ;
    USE SIGNAL ;
    PORT
      LAYER M5 ;
        RECT  49.392 25.836 49.416 25.92 ;
    END
  END ce_d[366]
  PIN ce_d[367]
    DIRECTION OUTPUT ;
    USE SIGNAL ;
    PORT
      LAYER M5 ;
        RECT  49.488 25.836 49.512 25.92 ;
    END
  END ce_d[367]
  PIN ce_d[368]
    DIRECTION OUTPUT ;
    USE SIGNAL ;
    PORT
      LAYER M5 ;
        RECT  49.584 25.836 49.608 25.92 ;
    END
  END ce_d[368]
  PIN ce_d[369]
    DIRECTION OUTPUT ;
    USE SIGNAL ;
    PORT
      LAYER M5 ;
        RECT  49.68 25.836 49.704 25.92 ;
    END
  END ce_d[369]
  PIN ce_d[36]
    DIRECTION OUTPUT ;
    USE SIGNAL ;
    PORT
      LAYER M5 ;
        RECT  44.592 25.836 44.616 25.92 ;
    END
  END ce_d[36]
  PIN ce_d[370]
    DIRECTION OUTPUT ;
    USE SIGNAL ;
    PORT
      LAYER M5 ;
        RECT  49.776 25.836 49.8 25.92 ;
    END
  END ce_d[370]
  PIN ce_d[371]
    DIRECTION OUTPUT ;
    USE SIGNAL ;
    PORT
      LAYER M5 ;
        RECT  49.872 25.836 49.896 25.92 ;
    END
  END ce_d[371]
  PIN ce_d[372]
    DIRECTION OUTPUT ;
    USE SIGNAL ;
    PORT
      LAYER M5 ;
        RECT  49.968 25.836 49.992 25.92 ;
    END
  END ce_d[372]
  PIN ce_d[373]
    DIRECTION OUTPUT ;
    USE SIGNAL ;
    PORT
      LAYER M5 ;
        RECT  50.064 25.836 50.088 25.92 ;
    END
  END ce_d[373]
  PIN ce_d[374]
    DIRECTION OUTPUT ;
    USE SIGNAL ;
    PORT
      LAYER M5 ;
        RECT  50.16 25.836 50.184 25.92 ;
    END
  END ce_d[374]
  PIN ce_d[375]
    DIRECTION OUTPUT ;
    USE SIGNAL ;
    PORT
      LAYER M5 ;
        RECT  50.256 25.836 50.28 25.92 ;
    END
  END ce_d[375]
  PIN ce_d[376]
    DIRECTION OUTPUT ;
    USE SIGNAL ;
    PORT
      LAYER M5 ;
        RECT  50.352 25.836 50.376 25.92 ;
    END
  END ce_d[376]
  PIN ce_d[377]
    DIRECTION OUTPUT ;
    USE SIGNAL ;
    PORT
      LAYER M5 ;
        RECT  50.448 25.836 50.472 25.92 ;
    END
  END ce_d[377]
  PIN ce_d[378]
    DIRECTION OUTPUT ;
    USE SIGNAL ;
    PORT
      LAYER M5 ;
        RECT  50.544 25.836 50.568 25.92 ;
    END
  END ce_d[378]
  PIN ce_d[379]
    DIRECTION OUTPUT ;
    USE SIGNAL ;
    PORT
      LAYER M5 ;
        RECT  50.64 25.836 50.664 25.92 ;
    END
  END ce_d[379]
  PIN ce_d[37]
    DIRECTION OUTPUT ;
    USE SIGNAL ;
    PORT
      LAYER M5 ;
        RECT  44.688 25.836 44.712 25.92 ;
    END
  END ce_d[37]
  PIN ce_d[380]
    DIRECTION OUTPUT ;
    USE SIGNAL ;
    PORT
      LAYER M5 ;
        RECT  50.736 25.836 50.76 25.92 ;
    END
  END ce_d[380]
  PIN ce_d[381]
    DIRECTION OUTPUT ;
    USE SIGNAL ;
    PORT
      LAYER M5 ;
        RECT  50.832 25.836 50.856 25.92 ;
    END
  END ce_d[381]
  PIN ce_d[382]
    DIRECTION OUTPUT ;
    USE SIGNAL ;
    PORT
      LAYER M5 ;
        RECT  50.928 25.836 50.952 25.92 ;
    END
  END ce_d[382]
  PIN ce_d[383]
    DIRECTION OUTPUT ;
    USE SIGNAL ;
    PORT
      LAYER M5 ;
        RECT  51.024 25.836 51.048 25.92 ;
    END
  END ce_d[383]
  PIN ce_d[384]
    DIRECTION OUTPUT ;
    USE SIGNAL ;
    PORT
      LAYER M5 ;
        RECT  21.936 25.836 21.96 25.92 ;
    END
  END ce_d[384]
  PIN ce_d[385]
    DIRECTION OUTPUT ;
    USE SIGNAL ;
    PORT
      LAYER M5 ;
        RECT  22.032 25.836 22.056 25.92 ;
    END
  END ce_d[385]
  PIN ce_d[386]
    DIRECTION OUTPUT ;
    USE SIGNAL ;
    PORT
      LAYER M5 ;
        RECT  22.128 25.836 22.152 25.92 ;
    END
  END ce_d[386]
  PIN ce_d[387]
    DIRECTION OUTPUT ;
    USE SIGNAL ;
    PORT
      LAYER M5 ;
        RECT  22.224 25.836 22.248 25.92 ;
    END
  END ce_d[387]
  PIN ce_d[388]
    DIRECTION OUTPUT ;
    USE SIGNAL ;
    PORT
      LAYER M5 ;
        RECT  22.32 25.836 22.344 25.92 ;
    END
  END ce_d[388]
  PIN ce_d[389]
    DIRECTION OUTPUT ;
    USE SIGNAL ;
    PORT
      LAYER M5 ;
        RECT  22.416 25.836 22.44 25.92 ;
    END
  END ce_d[389]
  PIN ce_d[38]
    DIRECTION OUTPUT ;
    USE SIGNAL ;
    PORT
      LAYER M5 ;
        RECT  44.784 25.836 44.808 25.92 ;
    END
  END ce_d[38]
  PIN ce_d[390]
    DIRECTION OUTPUT ;
    USE SIGNAL ;
    PORT
      LAYER M5 ;
        RECT  22.512 25.836 22.536 25.92 ;
    END
  END ce_d[390]
  PIN ce_d[391]
    DIRECTION OUTPUT ;
    USE SIGNAL ;
    PORT
      LAYER M5 ;
        RECT  22.608 25.836 22.632 25.92 ;
    END
  END ce_d[391]
  PIN ce_d[392]
    DIRECTION OUTPUT ;
    USE SIGNAL ;
    PORT
      LAYER M5 ;
        RECT  22.704 25.836 22.728 25.92 ;
    END
  END ce_d[392]
  PIN ce_d[393]
    DIRECTION OUTPUT ;
    USE SIGNAL ;
    PORT
      LAYER M5 ;
        RECT  22.8 25.836 22.824 25.92 ;
    END
  END ce_d[393]
  PIN ce_d[394]
    DIRECTION OUTPUT ;
    USE SIGNAL ;
    PORT
      LAYER M5 ;
        RECT  22.896 25.836 22.92 25.92 ;
    END
  END ce_d[394]
  PIN ce_d[395]
    DIRECTION OUTPUT ;
    USE SIGNAL ;
    PORT
      LAYER M5 ;
        RECT  22.992 25.836 23.016 25.92 ;
    END
  END ce_d[395]
  PIN ce_d[396]
    DIRECTION OUTPUT ;
    USE SIGNAL ;
    PORT
      LAYER M5 ;
        RECT  23.088 25.836 23.112 25.92 ;
    END
  END ce_d[396]
  PIN ce_d[397]
    DIRECTION OUTPUT ;
    USE SIGNAL ;
    PORT
      LAYER M5 ;
        RECT  23.184 25.836 23.208 25.92 ;
    END
  END ce_d[397]
  PIN ce_d[398]
    DIRECTION OUTPUT ;
    USE SIGNAL ;
    PORT
      LAYER M5 ;
        RECT  23.28 25.836 23.304 25.92 ;
    END
  END ce_d[398]
  PIN ce_d[399]
    DIRECTION OUTPUT ;
    USE SIGNAL ;
    PORT
      LAYER M5 ;
        RECT  23.376 25.836 23.4 25.92 ;
    END
  END ce_d[399]
  PIN ce_d[39]
    DIRECTION OUTPUT ;
    USE SIGNAL ;
    PORT
      LAYER M5 ;
        RECT  44.88 25.836 44.904 25.92 ;
    END
  END ce_d[39]
  PIN ce_d[3]
    DIRECTION OUTPUT ;
    USE SIGNAL ;
    PORT
      LAYER M5 ;
        RECT  35.28 25.836 35.304 25.92 ;
    END
  END ce_d[3]
  PIN ce_d[400]
    DIRECTION OUTPUT ;
    USE SIGNAL ;
    PORT
      LAYER M5 ;
        RECT  23.472 25.836 23.496 25.92 ;
    END
  END ce_d[400]
  PIN ce_d[401]
    DIRECTION OUTPUT ;
    USE SIGNAL ;
    PORT
      LAYER M5 ;
        RECT  23.568 25.836 23.592 25.92 ;
    END
  END ce_d[401]
  PIN ce_d[402]
    DIRECTION OUTPUT ;
    USE SIGNAL ;
    PORT
      LAYER M5 ;
        RECT  23.664 25.836 23.688 25.92 ;
    END
  END ce_d[402]
  PIN ce_d[403]
    DIRECTION OUTPUT ;
    USE SIGNAL ;
    PORT
      LAYER M5 ;
        RECT  23.76 25.836 23.784 25.92 ;
    END
  END ce_d[403]
  PIN ce_d[404]
    DIRECTION OUTPUT ;
    USE SIGNAL ;
    PORT
      LAYER M5 ;
        RECT  23.856 25.836 23.88 25.92 ;
    END
  END ce_d[404]
  PIN ce_d[405]
    DIRECTION OUTPUT ;
    USE SIGNAL ;
    PORT
      LAYER M5 ;
        RECT  23.952 25.836 23.976 25.92 ;
    END
  END ce_d[405]
  PIN ce_d[406]
    DIRECTION OUTPUT ;
    USE SIGNAL ;
    PORT
      LAYER M5 ;
        RECT  24.048 25.836 24.072 25.92 ;
    END
  END ce_d[406]
  PIN ce_d[407]
    DIRECTION OUTPUT ;
    USE SIGNAL ;
    PORT
      LAYER M5 ;
        RECT  24.144 25.836 24.168 25.92 ;
    END
  END ce_d[407]
  PIN ce_d[408]
    DIRECTION OUTPUT ;
    USE SIGNAL ;
    PORT
      LAYER M5 ;
        RECT  24.24 25.836 24.264 25.92 ;
    END
  END ce_d[408]
  PIN ce_d[409]
    DIRECTION OUTPUT ;
    USE SIGNAL ;
    PORT
      LAYER M5 ;
        RECT  24.336 25.836 24.36 25.92 ;
    END
  END ce_d[409]
  PIN ce_d[40]
    DIRECTION OUTPUT ;
    USE SIGNAL ;
    PORT
      LAYER M5 ;
        RECT  44.976 25.836 45 25.92 ;
    END
  END ce_d[40]
  PIN ce_d[410]
    DIRECTION OUTPUT ;
    USE SIGNAL ;
    PORT
      LAYER M5 ;
        RECT  24.432 25.836 24.456 25.92 ;
    END
  END ce_d[410]
  PIN ce_d[411]
    DIRECTION OUTPUT ;
    USE SIGNAL ;
    PORT
      LAYER M5 ;
        RECT  24.528 25.836 24.552 25.92 ;
    END
  END ce_d[411]
  PIN ce_d[412]
    DIRECTION OUTPUT ;
    USE SIGNAL ;
    PORT
      LAYER M5 ;
        RECT  24.624 25.836 24.648 25.92 ;
    END
  END ce_d[412]
  PIN ce_d[413]
    DIRECTION OUTPUT ;
    USE SIGNAL ;
    PORT
      LAYER M5 ;
        RECT  24.72 25.836 24.744 25.92 ;
    END
  END ce_d[413]
  PIN ce_d[414]
    DIRECTION OUTPUT ;
    USE SIGNAL ;
    PORT
      LAYER M5 ;
        RECT  24.816 25.836 24.84 25.92 ;
    END
  END ce_d[414]
  PIN ce_d[415]
    DIRECTION OUTPUT ;
    USE SIGNAL ;
    PORT
      LAYER M5 ;
        RECT  24.912 25.836 24.936 25.92 ;
    END
  END ce_d[415]
  PIN ce_d[416]
    DIRECTION OUTPUT ;
    USE SIGNAL ;
    PORT
      LAYER M5 ;
        RECT  25.008 25.836 25.032 25.92 ;
    END
  END ce_d[416]
  PIN ce_d[417]
    DIRECTION OUTPUT ;
    USE SIGNAL ;
    PORT
      LAYER M5 ;
        RECT  25.104 25.836 25.128 25.92 ;
    END
  END ce_d[417]
  PIN ce_d[418]
    DIRECTION OUTPUT ;
    USE SIGNAL ;
    PORT
      LAYER M5 ;
        RECT  25.2 25.836 25.224 25.92 ;
    END
  END ce_d[418]
  PIN ce_d[419]
    DIRECTION OUTPUT ;
    USE SIGNAL ;
    PORT
      LAYER M5 ;
        RECT  25.296 25.836 25.32 25.92 ;
    END
  END ce_d[419]
  PIN ce_d[41]
    DIRECTION OUTPUT ;
    USE SIGNAL ;
    PORT
      LAYER M5 ;
        RECT  45.072 25.836 45.096 25.92 ;
    END
  END ce_d[41]
  PIN ce_d[420]
    DIRECTION OUTPUT ;
    USE SIGNAL ;
    PORT
      LAYER M5 ;
        RECT  25.392 25.836 25.416 25.92 ;
    END
  END ce_d[420]
  PIN ce_d[421]
    DIRECTION OUTPUT ;
    USE SIGNAL ;
    PORT
      LAYER M5 ;
        RECT  25.488 25.836 25.512 25.92 ;
    END
  END ce_d[421]
  PIN ce_d[422]
    DIRECTION OUTPUT ;
    USE SIGNAL ;
    PORT
      LAYER M5 ;
        RECT  25.584 25.836 25.608 25.92 ;
    END
  END ce_d[422]
  PIN ce_d[423]
    DIRECTION OUTPUT ;
    USE SIGNAL ;
    PORT
      LAYER M5 ;
        RECT  25.68 25.836 25.704 25.92 ;
    END
  END ce_d[423]
  PIN ce_d[424]
    DIRECTION OUTPUT ;
    USE SIGNAL ;
    PORT
      LAYER M5 ;
        RECT  25.776 25.836 25.8 25.92 ;
    END
  END ce_d[424]
  PIN ce_d[425]
    DIRECTION OUTPUT ;
    USE SIGNAL ;
    PORT
      LAYER M5 ;
        RECT  25.872 25.836 25.896 25.92 ;
    END
  END ce_d[425]
  PIN ce_d[426]
    DIRECTION OUTPUT ;
    USE SIGNAL ;
    PORT
      LAYER M5 ;
        RECT  25.968 25.836 25.992 25.92 ;
    END
  END ce_d[426]
  PIN ce_d[427]
    DIRECTION OUTPUT ;
    USE SIGNAL ;
    PORT
      LAYER M5 ;
        RECT  26.064 25.836 26.088 25.92 ;
    END
  END ce_d[427]
  PIN ce_d[428]
    DIRECTION OUTPUT ;
    USE SIGNAL ;
    PORT
      LAYER M5 ;
        RECT  26.16 25.836 26.184 25.92 ;
    END
  END ce_d[428]
  PIN ce_d[429]
    DIRECTION OUTPUT ;
    USE SIGNAL ;
    PORT
      LAYER M5 ;
        RECT  26.256 25.836 26.28 25.92 ;
    END
  END ce_d[429]
  PIN ce_d[42]
    DIRECTION OUTPUT ;
    USE SIGNAL ;
    PORT
      LAYER M5 ;
        RECT  45.168 25.836 45.192 25.92 ;
    END
  END ce_d[42]
  PIN ce_d[430]
    DIRECTION OUTPUT ;
    USE SIGNAL ;
    PORT
      LAYER M5 ;
        RECT  26.352 25.836 26.376 25.92 ;
    END
  END ce_d[430]
  PIN ce_d[431]
    DIRECTION OUTPUT ;
    USE SIGNAL ;
    PORT
      LAYER M5 ;
        RECT  26.448 25.836 26.472 25.92 ;
    END
  END ce_d[431]
  PIN ce_d[432]
    DIRECTION OUTPUT ;
    USE SIGNAL ;
    PORT
      LAYER M5 ;
        RECT  26.544 25.836 26.568 25.92 ;
    END
  END ce_d[432]
  PIN ce_d[433]
    DIRECTION OUTPUT ;
    USE SIGNAL ;
    PORT
      LAYER M5 ;
        RECT  26.64 25.836 26.664 25.92 ;
    END
  END ce_d[433]
  PIN ce_d[434]
    DIRECTION OUTPUT ;
    USE SIGNAL ;
    PORT
      LAYER M5 ;
        RECT  26.736 25.836 26.76 25.92 ;
    END
  END ce_d[434]
  PIN ce_d[435]
    DIRECTION OUTPUT ;
    USE SIGNAL ;
    PORT
      LAYER M5 ;
        RECT  26.832 25.836 26.856 25.92 ;
    END
  END ce_d[435]
  PIN ce_d[436]
    DIRECTION OUTPUT ;
    USE SIGNAL ;
    PORT
      LAYER M5 ;
        RECT  26.928 25.836 26.952 25.92 ;
    END
  END ce_d[436]
  PIN ce_d[437]
    DIRECTION OUTPUT ;
    USE SIGNAL ;
    PORT
      LAYER M5 ;
        RECT  27.024 25.836 27.048 25.92 ;
    END
  END ce_d[437]
  PIN ce_d[438]
    DIRECTION OUTPUT ;
    USE SIGNAL ;
    PORT
      LAYER M5 ;
        RECT  27.12 25.836 27.144 25.92 ;
    END
  END ce_d[438]
  PIN ce_d[439]
    DIRECTION OUTPUT ;
    USE SIGNAL ;
    PORT
      LAYER M5 ;
        RECT  27.216 25.836 27.24 25.92 ;
    END
  END ce_d[439]
  PIN ce_d[43]
    DIRECTION OUTPUT ;
    USE SIGNAL ;
    PORT
      LAYER M5 ;
        RECT  45.264 25.836 45.288 25.92 ;
    END
  END ce_d[43]
  PIN ce_d[440]
    DIRECTION OUTPUT ;
    USE SIGNAL ;
    PORT
      LAYER M5 ;
        RECT  27.312 25.836 27.336 25.92 ;
    END
  END ce_d[440]
  PIN ce_d[441]
    DIRECTION OUTPUT ;
    USE SIGNAL ;
    PORT
      LAYER M5 ;
        RECT  27.408 25.836 27.432 25.92 ;
    END
  END ce_d[441]
  PIN ce_d[442]
    DIRECTION OUTPUT ;
    USE SIGNAL ;
    PORT
      LAYER M5 ;
        RECT  27.504 25.836 27.528 25.92 ;
    END
  END ce_d[442]
  PIN ce_d[443]
    DIRECTION OUTPUT ;
    USE SIGNAL ;
    PORT
      LAYER M5 ;
        RECT  27.6 25.836 27.624 25.92 ;
    END
  END ce_d[443]
  PIN ce_d[444]
    DIRECTION OUTPUT ;
    USE SIGNAL ;
    PORT
      LAYER M5 ;
        RECT  27.696 25.836 27.72 25.92 ;
    END
  END ce_d[444]
  PIN ce_d[445]
    DIRECTION OUTPUT ;
    USE SIGNAL ;
    PORT
      LAYER M5 ;
        RECT  27.792 25.836 27.816 25.92 ;
    END
  END ce_d[445]
  PIN ce_d[446]
    DIRECTION OUTPUT ;
    USE SIGNAL ;
    PORT
      LAYER M5 ;
        RECT  27.888 25.836 27.912 25.92 ;
    END
  END ce_d[446]
  PIN ce_d[447]
    DIRECTION OUTPUT ;
    USE SIGNAL ;
    PORT
      LAYER M5 ;
        RECT  27.984 25.836 28.008 25.92 ;
    END
  END ce_d[447]
  PIN ce_d[448]
    DIRECTION OUTPUT ;
    USE SIGNAL ;
    PORT
      LAYER M5 ;
        RECT  67.248 25.836 67.272 25.92 ;
    END
  END ce_d[448]
  PIN ce_d[449]
    DIRECTION OUTPUT ;
    USE SIGNAL ;
    PORT
      LAYER M5 ;
        RECT  67.344 25.836 67.368 25.92 ;
    END
  END ce_d[449]
  PIN ce_d[44]
    DIRECTION OUTPUT ;
    USE SIGNAL ;
    PORT
      LAYER M5 ;
        RECT  45.36 25.836 45.384 25.92 ;
    END
  END ce_d[44]
  PIN ce_d[450]
    DIRECTION OUTPUT ;
    USE SIGNAL ;
    PORT
      LAYER M5 ;
        RECT  67.44 25.836 67.464 25.92 ;
    END
  END ce_d[450]
  PIN ce_d[451]
    DIRECTION OUTPUT ;
    USE SIGNAL ;
    PORT
      LAYER M5 ;
        RECT  67.536 25.836 67.56 25.92 ;
    END
  END ce_d[451]
  PIN ce_d[452]
    DIRECTION OUTPUT ;
    USE SIGNAL ;
    PORT
      LAYER M5 ;
        RECT  67.632 25.836 67.656 25.92 ;
    END
  END ce_d[452]
  PIN ce_d[453]
    DIRECTION OUTPUT ;
    USE SIGNAL ;
    PORT
      LAYER M5 ;
        RECT  67.728 25.836 67.752 25.92 ;
    END
  END ce_d[453]
  PIN ce_d[454]
    DIRECTION OUTPUT ;
    USE SIGNAL ;
    PORT
      LAYER M5 ;
        RECT  67.824 25.836 67.848 25.92 ;
    END
  END ce_d[454]
  PIN ce_d[455]
    DIRECTION OUTPUT ;
    USE SIGNAL ;
    PORT
      LAYER M5 ;
        RECT  67.92 25.836 67.944 25.92 ;
    END
  END ce_d[455]
  PIN ce_d[456]
    DIRECTION OUTPUT ;
    USE SIGNAL ;
    PORT
      LAYER M5 ;
        RECT  68.016 25.836 68.04 25.92 ;
    END
  END ce_d[456]
  PIN ce_d[457]
    DIRECTION OUTPUT ;
    USE SIGNAL ;
    PORT
      LAYER M5 ;
        RECT  68.112 25.836 68.136 25.92 ;
    END
  END ce_d[457]
  PIN ce_d[458]
    DIRECTION OUTPUT ;
    USE SIGNAL ;
    PORT
      LAYER M5 ;
        RECT  68.208 25.836 68.232 25.92 ;
    END
  END ce_d[458]
  PIN ce_d[459]
    DIRECTION OUTPUT ;
    USE SIGNAL ;
    PORT
      LAYER M5 ;
        RECT  68.304 25.836 68.328 25.92 ;
    END
  END ce_d[459]
  PIN ce_d[45]
    DIRECTION OUTPUT ;
    USE SIGNAL ;
    PORT
      LAYER M5 ;
        RECT  45.456 25.836 45.48 25.92 ;
    END
  END ce_d[45]
  PIN ce_d[460]
    DIRECTION OUTPUT ;
    USE SIGNAL ;
    PORT
      LAYER M5 ;
        RECT  68.4 25.836 68.424 25.92 ;
    END
  END ce_d[460]
  PIN ce_d[461]
    DIRECTION OUTPUT ;
    USE SIGNAL ;
    PORT
      LAYER M5 ;
        RECT  68.496 25.836 68.52 25.92 ;
    END
  END ce_d[461]
  PIN ce_d[462]
    DIRECTION OUTPUT ;
    USE SIGNAL ;
    PORT
      LAYER M5 ;
        RECT  68.592 25.836 68.616 25.92 ;
    END
  END ce_d[462]
  PIN ce_d[463]
    DIRECTION OUTPUT ;
    USE SIGNAL ;
    PORT
      LAYER M5 ;
        RECT  68.688 25.836 68.712 25.92 ;
    END
  END ce_d[463]
  PIN ce_d[464]
    DIRECTION OUTPUT ;
    USE SIGNAL ;
    PORT
      LAYER M5 ;
        RECT  68.784 25.836 68.808 25.92 ;
    END
  END ce_d[464]
  PIN ce_d[465]
    DIRECTION OUTPUT ;
    USE SIGNAL ;
    PORT
      LAYER M5 ;
        RECT  68.88 25.836 68.904 25.92 ;
    END
  END ce_d[465]
  PIN ce_d[466]
    DIRECTION OUTPUT ;
    USE SIGNAL ;
    PORT
      LAYER M5 ;
        RECT  68.976 25.836 69 25.92 ;
    END
  END ce_d[466]
  PIN ce_d[467]
    DIRECTION OUTPUT ;
    USE SIGNAL ;
    PORT
      LAYER M5 ;
        RECT  69.072 25.836 69.096 25.92 ;
    END
  END ce_d[467]
  PIN ce_d[468]
    DIRECTION OUTPUT ;
    USE SIGNAL ;
    PORT
      LAYER M5 ;
        RECT  69.168 25.836 69.192 25.92 ;
    END
  END ce_d[468]
  PIN ce_d[469]
    DIRECTION OUTPUT ;
    USE SIGNAL ;
    PORT
      LAYER M5 ;
        RECT  69.264 25.836 69.288 25.92 ;
    END
  END ce_d[469]
  PIN ce_d[46]
    DIRECTION OUTPUT ;
    USE SIGNAL ;
    PORT
      LAYER M5 ;
        RECT  45.552 25.836 45.576 25.92 ;
    END
  END ce_d[46]
  PIN ce_d[470]
    DIRECTION OUTPUT ;
    USE SIGNAL ;
    PORT
      LAYER M5 ;
        RECT  69.36 25.836 69.384 25.92 ;
    END
  END ce_d[470]
  PIN ce_d[471]
    DIRECTION OUTPUT ;
    USE SIGNAL ;
    PORT
      LAYER M5 ;
        RECT  69.456 25.836 69.48 25.92 ;
    END
  END ce_d[471]
  PIN ce_d[472]
    DIRECTION OUTPUT ;
    USE SIGNAL ;
    PORT
      LAYER M5 ;
        RECT  69.552 25.836 69.576 25.92 ;
    END
  END ce_d[472]
  PIN ce_d[473]
    DIRECTION OUTPUT ;
    USE SIGNAL ;
    PORT
      LAYER M5 ;
        RECT  69.648 25.836 69.672 25.92 ;
    END
  END ce_d[473]
  PIN ce_d[474]
    DIRECTION OUTPUT ;
    USE SIGNAL ;
    PORT
      LAYER M5 ;
        RECT  69.744 25.836 69.768 25.92 ;
    END
  END ce_d[474]
  PIN ce_d[475]
    DIRECTION OUTPUT ;
    USE SIGNAL ;
    PORT
      LAYER M5 ;
        RECT  69.84 25.836 69.864 25.92 ;
    END
  END ce_d[475]
  PIN ce_d[476]
    DIRECTION OUTPUT ;
    USE SIGNAL ;
    PORT
      LAYER M5 ;
        RECT  69.936 25.836 69.96 25.92 ;
    END
  END ce_d[476]
  PIN ce_d[477]
    DIRECTION OUTPUT ;
    USE SIGNAL ;
    PORT
      LAYER M5 ;
        RECT  70.032 25.836 70.056 25.92 ;
    END
  END ce_d[477]
  PIN ce_d[478]
    DIRECTION OUTPUT ;
    USE SIGNAL ;
    PORT
      LAYER M5 ;
        RECT  70.128 25.836 70.152 25.92 ;
    END
  END ce_d[478]
  PIN ce_d[479]
    DIRECTION OUTPUT ;
    USE SIGNAL ;
    PORT
      LAYER M5 ;
        RECT  70.224 25.836 70.248 25.92 ;
    END
  END ce_d[479]
  PIN ce_d[47]
    DIRECTION OUTPUT ;
    USE SIGNAL ;
    PORT
      LAYER M5 ;
        RECT  45.648 25.836 45.672 25.92 ;
    END
  END ce_d[47]
  PIN ce_d[480]
    DIRECTION OUTPUT ;
    USE SIGNAL ;
    PORT
      LAYER M5 ;
        RECT  18.864 25.836 18.888 25.92 ;
    END
  END ce_d[480]
  PIN ce_d[481]
    DIRECTION OUTPUT ;
    USE SIGNAL ;
    PORT
      LAYER M5 ;
        RECT  18.96 25.836 18.984 25.92 ;
    END
  END ce_d[481]
  PIN ce_d[482]
    DIRECTION OUTPUT ;
    USE SIGNAL ;
    PORT
      LAYER M5 ;
        RECT  19.056 25.836 19.08 25.92 ;
    END
  END ce_d[482]
  PIN ce_d[483]
    DIRECTION OUTPUT ;
    USE SIGNAL ;
    PORT
      LAYER M5 ;
        RECT  19.152 25.836 19.176 25.92 ;
    END
  END ce_d[483]
  PIN ce_d[484]
    DIRECTION OUTPUT ;
    USE SIGNAL ;
    PORT
      LAYER M5 ;
        RECT  19.248 25.836 19.272 25.92 ;
    END
  END ce_d[484]
  PIN ce_d[485]
    DIRECTION OUTPUT ;
    USE SIGNAL ;
    PORT
      LAYER M5 ;
        RECT  19.344 25.836 19.368 25.92 ;
    END
  END ce_d[485]
  PIN ce_d[486]
    DIRECTION OUTPUT ;
    USE SIGNAL ;
    PORT
      LAYER M5 ;
        RECT  19.44 25.836 19.464 25.92 ;
    END
  END ce_d[486]
  PIN ce_d[487]
    DIRECTION OUTPUT ;
    USE SIGNAL ;
    PORT
      LAYER M5 ;
        RECT  19.536 25.836 19.56 25.92 ;
    END
  END ce_d[487]
  PIN ce_d[488]
    DIRECTION OUTPUT ;
    USE SIGNAL ;
    PORT
      LAYER M5 ;
        RECT  19.632 25.836 19.656 25.92 ;
    END
  END ce_d[488]
  PIN ce_d[489]
    DIRECTION OUTPUT ;
    USE SIGNAL ;
    PORT
      LAYER M5 ;
        RECT  19.728 25.836 19.752 25.92 ;
    END
  END ce_d[489]
  PIN ce_d[48]
    DIRECTION OUTPUT ;
    USE SIGNAL ;
    PORT
      LAYER M5 ;
        RECT  45.744 25.836 45.768 25.92 ;
    END
  END ce_d[48]
  PIN ce_d[490]
    DIRECTION OUTPUT ;
    USE SIGNAL ;
    PORT
      LAYER M5 ;
        RECT  19.824 25.836 19.848 25.92 ;
    END
  END ce_d[490]
  PIN ce_d[491]
    DIRECTION OUTPUT ;
    USE SIGNAL ;
    PORT
      LAYER M5 ;
        RECT  19.92 25.836 19.944 25.92 ;
    END
  END ce_d[491]
  PIN ce_d[492]
    DIRECTION OUTPUT ;
    USE SIGNAL ;
    PORT
      LAYER M5 ;
        RECT  20.016 25.836 20.04 25.92 ;
    END
  END ce_d[492]
  PIN ce_d[493]
    DIRECTION OUTPUT ;
    USE SIGNAL ;
    PORT
      LAYER M5 ;
        RECT  20.112 25.836 20.136 25.92 ;
    END
  END ce_d[493]
  PIN ce_d[494]
    DIRECTION OUTPUT ;
    USE SIGNAL ;
    PORT
      LAYER M5 ;
        RECT  20.208 25.836 20.232 25.92 ;
    END
  END ce_d[494]
  PIN ce_d[495]
    DIRECTION OUTPUT ;
    USE SIGNAL ;
    PORT
      LAYER M5 ;
        RECT  20.304 25.836 20.328 25.92 ;
    END
  END ce_d[495]
  PIN ce_d[496]
    DIRECTION OUTPUT ;
    USE SIGNAL ;
    PORT
      LAYER M5 ;
        RECT  20.4 25.836 20.424 25.92 ;
    END
  END ce_d[496]
  PIN ce_d[497]
    DIRECTION OUTPUT ;
    USE SIGNAL ;
    PORT
      LAYER M5 ;
        RECT  20.496 25.836 20.52 25.92 ;
    END
  END ce_d[497]
  PIN ce_d[498]
    DIRECTION OUTPUT ;
    USE SIGNAL ;
    PORT
      LAYER M5 ;
        RECT  20.592 25.836 20.616 25.92 ;
    END
  END ce_d[498]
  PIN ce_d[499]
    DIRECTION OUTPUT ;
    USE SIGNAL ;
    PORT
      LAYER M5 ;
        RECT  20.688 25.836 20.712 25.92 ;
    END
  END ce_d[499]
  PIN ce_d[49]
    DIRECTION OUTPUT ;
    USE SIGNAL ;
    PORT
      LAYER M5 ;
        RECT  45.84 25.836 45.864 25.92 ;
    END
  END ce_d[49]
  PIN ce_d[4]
    DIRECTION OUTPUT ;
    USE SIGNAL ;
    PORT
      LAYER M5 ;
        RECT  35.376 25.836 35.4 25.92 ;
    END
  END ce_d[4]
  PIN ce_d[500]
    DIRECTION OUTPUT ;
    USE SIGNAL ;
    PORT
      LAYER M5 ;
        RECT  20.784 25.836 20.808 25.92 ;
    END
  END ce_d[500]
  PIN ce_d[501]
    DIRECTION OUTPUT ;
    USE SIGNAL ;
    PORT
      LAYER M5 ;
        RECT  20.88 25.836 20.904 25.92 ;
    END
  END ce_d[501]
  PIN ce_d[502]
    DIRECTION OUTPUT ;
    USE SIGNAL ;
    PORT
      LAYER M5 ;
        RECT  20.976 25.836 21 25.92 ;
    END
  END ce_d[502]
  PIN ce_d[503]
    DIRECTION OUTPUT ;
    USE SIGNAL ;
    PORT
      LAYER M5 ;
        RECT  21.072 25.836 21.096 25.92 ;
    END
  END ce_d[503]
  PIN ce_d[504]
    DIRECTION OUTPUT ;
    USE SIGNAL ;
    PORT
      LAYER M5 ;
        RECT  21.168 25.836 21.192 25.92 ;
    END
  END ce_d[504]
  PIN ce_d[505]
    DIRECTION OUTPUT ;
    USE SIGNAL ;
    PORT
      LAYER M5 ;
        RECT  21.264 25.836 21.288 25.92 ;
    END
  END ce_d[505]
  PIN ce_d[506]
    DIRECTION OUTPUT ;
    USE SIGNAL ;
    PORT
      LAYER M5 ;
        RECT  21.36 25.836 21.384 25.92 ;
    END
  END ce_d[506]
  PIN ce_d[507]
    DIRECTION OUTPUT ;
    USE SIGNAL ;
    PORT
      LAYER M5 ;
        RECT  21.456 25.836 21.48 25.92 ;
    END
  END ce_d[507]
  PIN ce_d[508]
    DIRECTION OUTPUT ;
    USE SIGNAL ;
    PORT
      LAYER M5 ;
        RECT  21.552 25.836 21.576 25.92 ;
    END
  END ce_d[508]
  PIN ce_d[509]
    DIRECTION OUTPUT ;
    USE SIGNAL ;
    PORT
      LAYER M5 ;
        RECT  21.648 25.836 21.672 25.92 ;
    END
  END ce_d[509]
  PIN ce_d[50]
    DIRECTION OUTPUT ;
    USE SIGNAL ;
    PORT
      LAYER M5 ;
        RECT  45.936 25.836 45.96 25.92 ;
    END
  END ce_d[50]
  PIN ce_d[510]
    DIRECTION OUTPUT ;
    USE SIGNAL ;
    PORT
      LAYER M5 ;
        RECT  21.744 25.836 21.768 25.92 ;
    END
  END ce_d[510]
  PIN ce_d[511]
    DIRECTION OUTPUT ;
    USE SIGNAL ;
    PORT
      LAYER M5 ;
        RECT  21.84 25.836 21.864 25.92 ;
    END
  END ce_d[511]
  PIN ce_d[512]
    DIRECTION OUTPUT ;
    USE SIGNAL ;
    PORT
      LAYER M5 ;
        RECT  17.04 25.836 17.064 25.92 ;
    END
  END ce_d[512]
  PIN ce_d[513]
    DIRECTION OUTPUT ;
    USE SIGNAL ;
    PORT
      LAYER M5 ;
        RECT  17.136 25.836 17.16 25.92 ;
    END
  END ce_d[513]
  PIN ce_d[514]
    DIRECTION OUTPUT ;
    USE SIGNAL ;
    PORT
      LAYER M5 ;
        RECT  17.232 25.836 17.256 25.92 ;
    END
  END ce_d[514]
  PIN ce_d[515]
    DIRECTION OUTPUT ;
    USE SIGNAL ;
    PORT
      LAYER M5 ;
        RECT  17.328 25.836 17.352 25.92 ;
    END
  END ce_d[515]
  PIN ce_d[516]
    DIRECTION OUTPUT ;
    USE SIGNAL ;
    PORT
      LAYER M5 ;
        RECT  17.424 25.836 17.448 25.92 ;
    END
  END ce_d[516]
  PIN ce_d[517]
    DIRECTION OUTPUT ;
    USE SIGNAL ;
    PORT
      LAYER M5 ;
        RECT  17.52 25.836 17.544 25.92 ;
    END
  END ce_d[517]
  PIN ce_d[518]
    DIRECTION OUTPUT ;
    USE SIGNAL ;
    PORT
      LAYER M5 ;
        RECT  17.616 25.836 17.64 25.92 ;
    END
  END ce_d[518]
  PIN ce_d[519]
    DIRECTION OUTPUT ;
    USE SIGNAL ;
    PORT
      LAYER M5 ;
        RECT  17.712 25.836 17.736 25.92 ;
    END
  END ce_d[519]
  PIN ce_d[51]
    DIRECTION OUTPUT ;
    USE SIGNAL ;
    PORT
      LAYER M5 ;
        RECT  46.032 25.836 46.056 25.92 ;
    END
  END ce_d[51]
  PIN ce_d[520]
    DIRECTION OUTPUT ;
    USE SIGNAL ;
    PORT
      LAYER M5 ;
        RECT  17.808 25.836 17.832 25.92 ;
    END
  END ce_d[520]
  PIN ce_d[521]
    DIRECTION OUTPUT ;
    USE SIGNAL ;
    PORT
      LAYER M5 ;
        RECT  17.904 25.836 17.928 25.92 ;
    END
  END ce_d[521]
  PIN ce_d[522]
    DIRECTION OUTPUT ;
    USE SIGNAL ;
    PORT
      LAYER M5 ;
        RECT  18 25.836 18.024 25.92 ;
    END
  END ce_d[522]
  PIN ce_d[523]
    DIRECTION OUTPUT ;
    USE SIGNAL ;
    PORT
      LAYER M5 ;
        RECT  18.096 25.836 18.12 25.92 ;
    END
  END ce_d[523]
  PIN ce_d[524]
    DIRECTION OUTPUT ;
    USE SIGNAL ;
    PORT
      LAYER M5 ;
        RECT  18.192 25.836 18.216 25.92 ;
    END
  END ce_d[524]
  PIN ce_d[525]
    DIRECTION OUTPUT ;
    USE SIGNAL ;
    PORT
      LAYER M5 ;
        RECT  18.288 25.836 18.312 25.92 ;
    END
  END ce_d[525]
  PIN ce_d[526]
    DIRECTION OUTPUT ;
    USE SIGNAL ;
    PORT
      LAYER M5 ;
        RECT  18.384 25.836 18.408 25.92 ;
    END
  END ce_d[526]
  PIN ce_d[527]
    DIRECTION OUTPUT ;
    USE SIGNAL ;
    PORT
      LAYER M5 ;
        RECT  18.48 25.836 18.504 25.92 ;
    END
  END ce_d[527]
  PIN ce_d[52]
    DIRECTION OUTPUT ;
    USE SIGNAL ;
    PORT
      LAYER M5 ;
        RECT  46.128 25.836 46.152 25.92 ;
    END
  END ce_d[52]
  PIN ce_d[53]
    DIRECTION OUTPUT ;
    USE SIGNAL ;
    PORT
      LAYER M5 ;
        RECT  46.224 25.836 46.248 25.92 ;
    END
  END ce_d[53]
  PIN ce_d[54]
    DIRECTION OUTPUT ;
    USE SIGNAL ;
    PORT
      LAYER M5 ;
        RECT  46.32 25.836 46.344 25.92 ;
    END
  END ce_d[54]
  PIN ce_d[55]
    DIRECTION OUTPUT ;
    USE SIGNAL ;
    PORT
      LAYER M5 ;
        RECT  46.416 25.836 46.44 25.92 ;
    END
  END ce_d[55]
  PIN ce_d[56]
    DIRECTION OUTPUT ;
    USE SIGNAL ;
    PORT
      LAYER M5 ;
        RECT  46.512 25.836 46.536 25.92 ;
    END
  END ce_d[56]
  PIN ce_d[57]
    DIRECTION OUTPUT ;
    USE SIGNAL ;
    PORT
      LAYER M5 ;
        RECT  46.608 25.836 46.632 25.92 ;
    END
  END ce_d[57]
  PIN ce_d[58]
    DIRECTION OUTPUT ;
    USE SIGNAL ;
    PORT
      LAYER M5 ;
        RECT  46.704 25.836 46.728 25.92 ;
    END
  END ce_d[58]
  PIN ce_d[59]
    DIRECTION OUTPUT ;
    USE SIGNAL ;
    PORT
      LAYER M5 ;
        RECT  46.8 25.836 46.824 25.92 ;
    END
  END ce_d[59]
  PIN ce_d[5]
    DIRECTION OUTPUT ;
    USE SIGNAL ;
    PORT
      LAYER M5 ;
        RECT  35.472 25.836 35.496 25.92 ;
    END
  END ce_d[5]
  PIN ce_d[60]
    DIRECTION OUTPUT ;
    USE SIGNAL ;
    PORT
      LAYER M5 ;
        RECT  46.896 25.836 46.92 25.92 ;
    END
  END ce_d[60]
  PIN ce_d[61]
    DIRECTION OUTPUT ;
    USE SIGNAL ;
    PORT
      LAYER M5 ;
        RECT  46.992 25.836 47.016 25.92 ;
    END
  END ce_d[61]
  PIN ce_d[62]
    DIRECTION OUTPUT ;
    USE SIGNAL ;
    PORT
      LAYER M5 ;
        RECT  47.088 25.836 47.112 25.92 ;
    END
  END ce_d[62]
  PIN ce_d[63]
    DIRECTION OUTPUT ;
    USE SIGNAL ;
    PORT
      LAYER M5 ;
        RECT  47.184 25.836 47.208 25.92 ;
    END
  END ce_d[63]
  PIN ce_d[64]
    DIRECTION OUTPUT ;
    USE SIGNAL ;
    PORT
      LAYER M5 ;
        RECT  38.064 25.836 38.088 25.92 ;
    END
  END ce_d[64]
  PIN ce_d[65]
    DIRECTION OUTPUT ;
    USE SIGNAL ;
    PORT
      LAYER M5 ;
        RECT  38.16 25.836 38.184 25.92 ;
    END
  END ce_d[65]
  PIN ce_d[66]
    DIRECTION OUTPUT ;
    USE SIGNAL ;
    PORT
      LAYER M5 ;
        RECT  38.256 25.836 38.28 25.92 ;
    END
  END ce_d[66]
  PIN ce_d[67]
    DIRECTION OUTPUT ;
    USE SIGNAL ;
    PORT
      LAYER M5 ;
        RECT  38.352 25.836 38.376 25.92 ;
    END
  END ce_d[67]
  PIN ce_d[68]
    DIRECTION OUTPUT ;
    USE SIGNAL ;
    PORT
      LAYER M5 ;
        RECT  38.448 25.836 38.472 25.92 ;
    END
  END ce_d[68]
  PIN ce_d[69]
    DIRECTION OUTPUT ;
    USE SIGNAL ;
    PORT
      LAYER M5 ;
        RECT  38.544 25.836 38.568 25.92 ;
    END
  END ce_d[69]
  PIN ce_d[6]
    DIRECTION OUTPUT ;
    USE SIGNAL ;
    PORT
      LAYER M5 ;
        RECT  35.568 25.836 35.592 25.92 ;
    END
  END ce_d[6]
  PIN ce_d[70]
    DIRECTION OUTPUT ;
    USE SIGNAL ;
    PORT
      LAYER M5 ;
        RECT  38.64 25.836 38.664 25.92 ;
    END
  END ce_d[70]
  PIN ce_d[71]
    DIRECTION OUTPUT ;
    USE SIGNAL ;
    PORT
      LAYER M5 ;
        RECT  38.736 25.836 38.76 25.92 ;
    END
  END ce_d[71]
  PIN ce_d[72]
    DIRECTION OUTPUT ;
    USE SIGNAL ;
    PORT
      LAYER M5 ;
        RECT  38.832 25.836 38.856 25.92 ;
    END
  END ce_d[72]
  PIN ce_d[73]
    DIRECTION OUTPUT ;
    USE SIGNAL ;
    PORT
      LAYER M5 ;
        RECT  38.928 25.836 38.952 25.92 ;
    END
  END ce_d[73]
  PIN ce_d[74]
    DIRECTION OUTPUT ;
    USE SIGNAL ;
    PORT
      LAYER M5 ;
        RECT  39.024 25.836 39.048 25.92 ;
    END
  END ce_d[74]
  PIN ce_d[75]
    DIRECTION OUTPUT ;
    USE SIGNAL ;
    PORT
      LAYER M5 ;
        RECT  39.12 25.836 39.144 25.92 ;
    END
  END ce_d[75]
  PIN ce_d[76]
    DIRECTION OUTPUT ;
    USE SIGNAL ;
    PORT
      LAYER M5 ;
        RECT  39.216 25.836 39.24 25.92 ;
    END
  END ce_d[76]
  PIN ce_d[77]
    DIRECTION OUTPUT ;
    USE SIGNAL ;
    PORT
      LAYER M5 ;
        RECT  39.312 25.836 39.336 25.92 ;
    END
  END ce_d[77]
  PIN ce_d[78]
    DIRECTION OUTPUT ;
    USE SIGNAL ;
    PORT
      LAYER M5 ;
        RECT  39.408 25.836 39.432 25.92 ;
    END
  END ce_d[78]
  PIN ce_d[79]
    DIRECTION OUTPUT ;
    USE SIGNAL ;
    PORT
      LAYER M5 ;
        RECT  39.504 25.836 39.528 25.92 ;
    END
  END ce_d[79]
  PIN ce_d[7]
    DIRECTION OUTPUT ;
    USE SIGNAL ;
    PORT
      LAYER M5 ;
        RECT  35.664 25.836 35.688 25.92 ;
    END
  END ce_d[7]
  PIN ce_d[80]
    DIRECTION OUTPUT ;
    USE SIGNAL ;
    PORT
      LAYER M5 ;
        RECT  39.6 25.836 39.624 25.92 ;
    END
  END ce_d[80]
  PIN ce_d[81]
    DIRECTION OUTPUT ;
    USE SIGNAL ;
    PORT
      LAYER M5 ;
        RECT  39.696 25.836 39.72 25.92 ;
    END
  END ce_d[81]
  PIN ce_d[82]
    DIRECTION OUTPUT ;
    USE SIGNAL ;
    PORT
      LAYER M5 ;
        RECT  39.792 25.836 39.816 25.92 ;
    END
  END ce_d[82]
  PIN ce_d[83]
    DIRECTION OUTPUT ;
    USE SIGNAL ;
    PORT
      LAYER M5 ;
        RECT  39.888 25.836 39.912 25.92 ;
    END
  END ce_d[83]
  PIN ce_d[84]
    DIRECTION OUTPUT ;
    USE SIGNAL ;
    PORT
      LAYER M5 ;
        RECT  39.984 25.836 40.008 25.92 ;
    END
  END ce_d[84]
  PIN ce_d[85]
    DIRECTION OUTPUT ;
    USE SIGNAL ;
    PORT
      LAYER M5 ;
        RECT  40.08 25.836 40.104 25.92 ;
    END
  END ce_d[85]
  PIN ce_d[86]
    DIRECTION OUTPUT ;
    USE SIGNAL ;
    PORT
      LAYER M5 ;
        RECT  40.176 25.836 40.2 25.92 ;
    END
  END ce_d[86]
  PIN ce_d[87]
    DIRECTION OUTPUT ;
    USE SIGNAL ;
    PORT
      LAYER M5 ;
        RECT  40.272 25.836 40.296 25.92 ;
    END
  END ce_d[87]
  PIN ce_d[88]
    DIRECTION OUTPUT ;
    USE SIGNAL ;
    PORT
      LAYER M5 ;
        RECT  40.368 25.836 40.392 25.92 ;
    END
  END ce_d[88]
  PIN ce_d[89]
    DIRECTION OUTPUT ;
    USE SIGNAL ;
    PORT
      LAYER M5 ;
        RECT  40.464 25.836 40.488 25.92 ;
    END
  END ce_d[89]
  PIN ce_d[8]
    DIRECTION OUTPUT ;
    USE SIGNAL ;
    PORT
      LAYER M5 ;
        RECT  35.76 25.836 35.784 25.92 ;
    END
  END ce_d[8]
  PIN ce_d[90]
    DIRECTION OUTPUT ;
    USE SIGNAL ;
    PORT
      LAYER M5 ;
        RECT  40.56 25.836 40.584 25.92 ;
    END
  END ce_d[90]
  PIN ce_d[91]
    DIRECTION OUTPUT ;
    USE SIGNAL ;
    PORT
      LAYER M5 ;
        RECT  40.656 25.836 40.68 25.92 ;
    END
  END ce_d[91]
  PIN ce_d[92]
    DIRECTION OUTPUT ;
    USE SIGNAL ;
    PORT
      LAYER M5 ;
        RECT  40.752 25.836 40.776 25.92 ;
    END
  END ce_d[92]
  PIN ce_d[93]
    DIRECTION OUTPUT ;
    USE SIGNAL ;
    PORT
      LAYER M5 ;
        RECT  40.848 25.836 40.872 25.92 ;
    END
  END ce_d[93]
  PIN ce_d[94]
    DIRECTION OUTPUT ;
    USE SIGNAL ;
    PORT
      LAYER M5 ;
        RECT  40.944 25.836 40.968 25.92 ;
    END
  END ce_d[94]
  PIN ce_d[95]
    DIRECTION OUTPUT ;
    USE SIGNAL ;
    PORT
      LAYER M5 ;
        RECT  41.04 25.836 41.064 25.92 ;
    END
  END ce_d[95]
  PIN ce_d[96]
    DIRECTION OUTPUT ;
    USE SIGNAL ;
    PORT
      LAYER M5 ;
        RECT  31.92 25.836 31.944 25.92 ;
    END
  END ce_d[96]
  PIN ce_d[97]
    DIRECTION OUTPUT ;
    USE SIGNAL ;
    PORT
      LAYER M5 ;
        RECT  32.016 25.836 32.04 25.92 ;
    END
  END ce_d[97]
  PIN ce_d[98]
    DIRECTION OUTPUT ;
    USE SIGNAL ;
    PORT
      LAYER M5 ;
        RECT  32.112 25.836 32.136 25.92 ;
    END
  END ce_d[98]
  PIN ce_d[99]
    DIRECTION OUTPUT ;
    USE SIGNAL ;
    PORT
      LAYER M5 ;
        RECT  32.208 25.836 32.232 25.92 ;
    END
  END ce_d[99]
  PIN ce_d[9]
    DIRECTION OUTPUT ;
    USE SIGNAL ;
    PORT
      LAYER M5 ;
        RECT  35.856 25.836 35.88 25.92 ;
    END
  END ce_d[9]
  PIN civ
    DIRECTION OUTPUT ;
    USE SIGNAL ;
    PORT
      LAYER M5 ;
        RECT  18.576 25.836 18.6 25.92 ;
    END
  END civ
  PIN clk
    DIRECTION INPUT ;
    USE SIGNAL ;
    PORT
      LAYER M4 ;
        RECT  0 17.328 0.084 17.352 ;
    END
  END clk
  PIN psh
    DIRECTION OUTPUT ;
    USE SIGNAL ;
    PORT
      LAYER M5 ;
        RECT  18.672 25.836 18.696 25.92 ;
    END
  END psh
  PIN rst_n
    DIRECTION INPUT ;
    USE SIGNAL ;
    PORT
      LAYER M4 ;
        RECT  0 17.424 0.084 17.448 ;
    END
  END rst_n
  PIN t_cr
    DIRECTION OUTPUT ;
    USE SIGNAL ;
    PORT
      LAYER M5 ;
        RECT  39.12 0 39.144 0.084 ;
    END
  END t_cr
  PIN t_d[0]
    DIRECTION INPUT ;
    USE SIGNAL ;
    PORT
      LAYER M5 ;
        RECT  39.216 0 39.24 0.084 ;
    END
  END t_d[0]
  PIN t_d[100]
    DIRECTION INPUT ;
    USE SIGNAL ;
    PORT
      LAYER M5 ;
        RECT  29.616 0 29.64 0.084 ;
    END
  END t_d[100]
  PIN t_d[101]
    DIRECTION INPUT ;
    USE SIGNAL ;
    PORT
      LAYER M5 ;
        RECT  29.712 0 29.736 0.084 ;
    END
  END t_d[101]
  PIN t_d[102]
    DIRECTION INPUT ;
    USE SIGNAL ;
    PORT
      LAYER M5 ;
        RECT  29.808 0 29.832 0.084 ;
    END
  END t_d[102]
  PIN t_d[103]
    DIRECTION INPUT ;
    USE SIGNAL ;
    PORT
      LAYER M5 ;
        RECT  29.904 0 29.928 0.084 ;
    END
  END t_d[103]
  PIN t_d[104]
    DIRECTION INPUT ;
    USE SIGNAL ;
    PORT
      LAYER M5 ;
        RECT  30 0 30.024 0.084 ;
    END
  END t_d[104]
  PIN t_d[105]
    DIRECTION INPUT ;
    USE SIGNAL ;
    PORT
      LAYER M5 ;
        RECT  30.096 0 30.12 0.084 ;
    END
  END t_d[105]
  PIN t_d[106]
    DIRECTION INPUT ;
    USE SIGNAL ;
    PORT
      LAYER M5 ;
        RECT  30.192 0 30.216 0.084 ;
    END
  END t_d[106]
  PIN t_d[107]
    DIRECTION INPUT ;
    USE SIGNAL ;
    PORT
      LAYER M5 ;
        RECT  30.288 0 30.312 0.084 ;
    END
  END t_d[107]
  PIN t_d[108]
    DIRECTION INPUT ;
    USE SIGNAL ;
    PORT
      LAYER M5 ;
        RECT  30.384 0 30.408 0.084 ;
    END
  END t_d[108]
  PIN t_d[109]
    DIRECTION INPUT ;
    USE SIGNAL ;
    PORT
      LAYER M5 ;
        RECT  30.48 0 30.504 0.084 ;
    END
  END t_d[109]
  PIN t_d[10]
    DIRECTION INPUT ;
    USE SIGNAL ;
    PORT
      LAYER M5 ;
        RECT  40.176 0 40.2 0.084 ;
    END
  END t_d[10]
  PIN t_d[110]
    DIRECTION INPUT ;
    USE SIGNAL ;
    PORT
      LAYER M5 ;
        RECT  30.576 0 30.6 0.084 ;
    END
  END t_d[110]
  PIN t_d[111]
    DIRECTION INPUT ;
    USE SIGNAL ;
    PORT
      LAYER M5 ;
        RECT  30.672 0 30.696 0.084 ;
    END
  END t_d[111]
  PIN t_d[112]
    DIRECTION INPUT ;
    USE SIGNAL ;
    PORT
      LAYER M5 ;
        RECT  30.768 0 30.792 0.084 ;
    END
  END t_d[112]
  PIN t_d[113]
    DIRECTION INPUT ;
    USE SIGNAL ;
    PORT
      LAYER M5 ;
        RECT  30.864 0 30.888 0.084 ;
    END
  END t_d[113]
  PIN t_d[114]
    DIRECTION INPUT ;
    USE SIGNAL ;
    PORT
      LAYER M5 ;
        RECT  30.96 0 30.984 0.084 ;
    END
  END t_d[114]
  PIN t_d[115]
    DIRECTION INPUT ;
    USE SIGNAL ;
    PORT
      LAYER M5 ;
        RECT  31.056 0 31.08 0.084 ;
    END
  END t_d[115]
  PIN t_d[116]
    DIRECTION INPUT ;
    USE SIGNAL ;
    PORT
      LAYER M5 ;
        RECT  31.152 0 31.176 0.084 ;
    END
  END t_d[116]
  PIN t_d[117]
    DIRECTION INPUT ;
    USE SIGNAL ;
    PORT
      LAYER M5 ;
        RECT  31.248 0 31.272 0.084 ;
    END
  END t_d[117]
  PIN t_d[118]
    DIRECTION INPUT ;
    USE SIGNAL ;
    PORT
      LAYER M5 ;
        RECT  31.344 0 31.368 0.084 ;
    END
  END t_d[118]
  PIN t_d[119]
    DIRECTION INPUT ;
    USE SIGNAL ;
    PORT
      LAYER M5 ;
        RECT  31.44 0 31.464 0.084 ;
    END
  END t_d[119]
  PIN t_d[11]
    DIRECTION INPUT ;
    USE SIGNAL ;
    PORT
      LAYER M5 ;
        RECT  40.272 0 40.296 0.084 ;
    END
  END t_d[11]
  PIN t_d[120]
    DIRECTION INPUT ;
    USE SIGNAL ;
    PORT
      LAYER M5 ;
        RECT  31.536 0 31.56 0.084 ;
    END
  END t_d[120]
  PIN t_d[121]
    DIRECTION INPUT ;
    USE SIGNAL ;
    PORT
      LAYER M5 ;
        RECT  31.632 0 31.656 0.084 ;
    END
  END t_d[121]
  PIN t_d[122]
    DIRECTION INPUT ;
    USE SIGNAL ;
    PORT
      LAYER M5 ;
        RECT  31.728 0 31.752 0.084 ;
    END
  END t_d[122]
  PIN t_d[123]
    DIRECTION INPUT ;
    USE SIGNAL ;
    PORT
      LAYER M5 ;
        RECT  31.824 0 31.848 0.084 ;
    END
  END t_d[123]
  PIN t_d[124]
    DIRECTION INPUT ;
    USE SIGNAL ;
    PORT
      LAYER M5 ;
        RECT  31.92 0 31.944 0.084 ;
    END
  END t_d[124]
  PIN t_d[125]
    DIRECTION INPUT ;
    USE SIGNAL ;
    PORT
      LAYER M5 ;
        RECT  32.016 0 32.04 0.084 ;
    END
  END t_d[125]
  PIN t_d[126]
    DIRECTION INPUT ;
    USE SIGNAL ;
    PORT
      LAYER M5 ;
        RECT  32.112 0 32.136 0.084 ;
    END
  END t_d[126]
  PIN t_d[127]
    DIRECTION INPUT ;
    USE SIGNAL ;
    PORT
      LAYER M5 ;
        RECT  48.336 0 48.36 0.084 ;
    END
  END t_d[127]
  PIN t_d[128]
    DIRECTION INPUT ;
    USE SIGNAL ;
    PORT
      LAYER M5 ;
        RECT  48.432 0 48.456 0.084 ;
    END
  END t_d[128]
  PIN t_d[129]
    DIRECTION INPUT ;
    USE SIGNAL ;
    PORT
      LAYER M5 ;
        RECT  48.528 0 48.552 0.084 ;
    END
  END t_d[129]
  PIN t_d[12]
    DIRECTION INPUT ;
    USE SIGNAL ;
    PORT
      LAYER M5 ;
        RECT  40.368 0 40.392 0.084 ;
    END
  END t_d[12]
  PIN t_d[130]
    DIRECTION INPUT ;
    USE SIGNAL ;
    PORT
      LAYER M5 ;
        RECT  48.624 0 48.648 0.084 ;
    END
  END t_d[130]
  PIN t_d[131]
    DIRECTION INPUT ;
    USE SIGNAL ;
    PORT
      LAYER M5 ;
        RECT  48.72 0 48.744 0.084 ;
    END
  END t_d[131]
  PIN t_d[132]
    DIRECTION INPUT ;
    USE SIGNAL ;
    PORT
      LAYER M5 ;
        RECT  48.816 0 48.84 0.084 ;
    END
  END t_d[132]
  PIN t_d[133]
    DIRECTION INPUT ;
    USE SIGNAL ;
    PORT
      LAYER M5 ;
        RECT  48.912 0 48.936 0.084 ;
    END
  END t_d[133]
  PIN t_d[134]
    DIRECTION INPUT ;
    USE SIGNAL ;
    PORT
      LAYER M5 ;
        RECT  49.008 0 49.032 0.084 ;
    END
  END t_d[134]
  PIN t_d[135]
    DIRECTION INPUT ;
    USE SIGNAL ;
    PORT
      LAYER M5 ;
        RECT  49.104 0 49.128 0.084 ;
    END
  END t_d[135]
  PIN t_d[136]
    DIRECTION INPUT ;
    USE SIGNAL ;
    PORT
      LAYER M5 ;
        RECT  49.2 0 49.224 0.084 ;
    END
  END t_d[136]
  PIN t_d[137]
    DIRECTION INPUT ;
    USE SIGNAL ;
    PORT
      LAYER M5 ;
        RECT  49.296 0 49.32 0.084 ;
    END
  END t_d[137]
  PIN t_d[138]
    DIRECTION INPUT ;
    USE SIGNAL ;
    PORT
      LAYER M5 ;
        RECT  49.392 0 49.416 0.084 ;
    END
  END t_d[138]
  PIN t_d[139]
    DIRECTION INPUT ;
    USE SIGNAL ;
    PORT
      LAYER M5 ;
        RECT  49.488 0 49.512 0.084 ;
    END
  END t_d[139]
  PIN t_d[13]
    DIRECTION INPUT ;
    USE SIGNAL ;
    PORT
      LAYER M5 ;
        RECT  40.464 0 40.488 0.084 ;
    END
  END t_d[13]
  PIN t_d[140]
    DIRECTION INPUT ;
    USE SIGNAL ;
    PORT
      LAYER M5 ;
        RECT  49.584 0 49.608 0.084 ;
    END
  END t_d[140]
  PIN t_d[141]
    DIRECTION INPUT ;
    USE SIGNAL ;
    PORT
      LAYER M5 ;
        RECT  49.68 0 49.704 0.084 ;
    END
  END t_d[141]
  PIN t_d[142]
    DIRECTION INPUT ;
    USE SIGNAL ;
    PORT
      LAYER M5 ;
        RECT  49.776 0 49.8 0.084 ;
    END
  END t_d[142]
  PIN t_d[143]
    DIRECTION INPUT ;
    USE SIGNAL ;
    PORT
      LAYER M5 ;
        RECT  49.872 0 49.896 0.084 ;
    END
  END t_d[143]
  PIN t_d[144]
    DIRECTION INPUT ;
    USE SIGNAL ;
    PORT
      LAYER M5 ;
        RECT  49.968 0 49.992 0.084 ;
    END
  END t_d[144]
  PIN t_d[145]
    DIRECTION INPUT ;
    USE SIGNAL ;
    PORT
      LAYER M5 ;
        RECT  50.064 0 50.088 0.084 ;
    END
  END t_d[145]
  PIN t_d[146]
    DIRECTION INPUT ;
    USE SIGNAL ;
    PORT
      LAYER M5 ;
        RECT  50.16 0 50.184 0.084 ;
    END
  END t_d[146]
  PIN t_d[147]
    DIRECTION INPUT ;
    USE SIGNAL ;
    PORT
      LAYER M5 ;
        RECT  50.256 0 50.28 0.084 ;
    END
  END t_d[147]
  PIN t_d[148]
    DIRECTION INPUT ;
    USE SIGNAL ;
    PORT
      LAYER M5 ;
        RECT  50.352 0 50.376 0.084 ;
    END
  END t_d[148]
  PIN t_d[149]
    DIRECTION INPUT ;
    USE SIGNAL ;
    PORT
      LAYER M5 ;
        RECT  50.448 0 50.472 0.084 ;
    END
  END t_d[149]
  PIN t_d[14]
    DIRECTION INPUT ;
    USE SIGNAL ;
    PORT
      LAYER M5 ;
        RECT  40.56 0 40.584 0.084 ;
    END
  END t_d[14]
  PIN t_d[150]
    DIRECTION INPUT ;
    USE SIGNAL ;
    PORT
      LAYER M5 ;
        RECT  50.544 0 50.568 0.084 ;
    END
  END t_d[150]
  PIN t_d[151]
    DIRECTION INPUT ;
    USE SIGNAL ;
    PORT
      LAYER M5 ;
        RECT  50.64 0 50.664 0.084 ;
    END
  END t_d[151]
  PIN t_d[152]
    DIRECTION INPUT ;
    USE SIGNAL ;
    PORT
      LAYER M5 ;
        RECT  50.736 0 50.76 0.084 ;
    END
  END t_d[152]
  PIN t_d[153]
    DIRECTION INPUT ;
    USE SIGNAL ;
    PORT
      LAYER M5 ;
        RECT  50.832 0 50.856 0.084 ;
    END
  END t_d[153]
  PIN t_d[154]
    DIRECTION INPUT ;
    USE SIGNAL ;
    PORT
      LAYER M5 ;
        RECT  50.928 0 50.952 0.084 ;
    END
  END t_d[154]
  PIN t_d[155]
    DIRECTION INPUT ;
    USE SIGNAL ;
    PORT
      LAYER M5 ;
        RECT  51.024 0 51.048 0.084 ;
    END
  END t_d[155]
  PIN t_d[156]
    DIRECTION INPUT ;
    USE SIGNAL ;
    PORT
      LAYER M5 ;
        RECT  51.12 0 51.144 0.084 ;
    END
  END t_d[156]
  PIN t_d[157]
    DIRECTION INPUT ;
    USE SIGNAL ;
    PORT
      LAYER M5 ;
        RECT  51.216 0 51.24 0.084 ;
    END
  END t_d[157]
  PIN t_d[158]
    DIRECTION INPUT ;
    USE SIGNAL ;
    PORT
      LAYER M5 ;
        RECT  51.312 0 51.336 0.084 ;
    END
  END t_d[158]
  PIN t_d[159]
    DIRECTION INPUT ;
    USE SIGNAL ;
    PORT
      LAYER M5 ;
        RECT  19.92 0 19.944 0.084 ;
    END
  END t_d[159]
  PIN t_d[15]
    DIRECTION INPUT ;
    USE SIGNAL ;
    PORT
      LAYER M5 ;
        RECT  40.656 0 40.68 0.084 ;
    END
  END t_d[15]
  PIN t_d[160]
    DIRECTION INPUT ;
    USE SIGNAL ;
    PORT
      LAYER M5 ;
        RECT  20.016 0 20.04 0.084 ;
    END
  END t_d[160]
  PIN t_d[161]
    DIRECTION INPUT ;
    USE SIGNAL ;
    PORT
      LAYER M5 ;
        RECT  20.112 0 20.136 0.084 ;
    END
  END t_d[161]
  PIN t_d[162]
    DIRECTION INPUT ;
    USE SIGNAL ;
    PORT
      LAYER M5 ;
        RECT  20.208 0 20.232 0.084 ;
    END
  END t_d[162]
  PIN t_d[163]
    DIRECTION INPUT ;
    USE SIGNAL ;
    PORT
      LAYER M5 ;
        RECT  20.304 0 20.328 0.084 ;
    END
  END t_d[163]
  PIN t_d[164]
    DIRECTION INPUT ;
    USE SIGNAL ;
    PORT
      LAYER M5 ;
        RECT  20.4 0 20.424 0.084 ;
    END
  END t_d[164]
  PIN t_d[165]
    DIRECTION INPUT ;
    USE SIGNAL ;
    PORT
      LAYER M5 ;
        RECT  20.496 0 20.52 0.084 ;
    END
  END t_d[165]
  PIN t_d[166]
    DIRECTION INPUT ;
    USE SIGNAL ;
    PORT
      LAYER M5 ;
        RECT  20.592 0 20.616 0.084 ;
    END
  END t_d[166]
  PIN t_d[167]
    DIRECTION INPUT ;
    USE SIGNAL ;
    PORT
      LAYER M5 ;
        RECT  20.688 0 20.712 0.084 ;
    END
  END t_d[167]
  PIN t_d[168]
    DIRECTION INPUT ;
    USE SIGNAL ;
    PORT
      LAYER M5 ;
        RECT  20.784 0 20.808 0.084 ;
    END
  END t_d[168]
  PIN t_d[169]
    DIRECTION INPUT ;
    USE SIGNAL ;
    PORT
      LAYER M5 ;
        RECT  20.88 0 20.904 0.084 ;
    END
  END t_d[169]
  PIN t_d[16]
    DIRECTION INPUT ;
    USE SIGNAL ;
    PORT
      LAYER M5 ;
        RECT  40.752 0 40.776 0.084 ;
    END
  END t_d[16]
  PIN t_d[170]
    DIRECTION INPUT ;
    USE SIGNAL ;
    PORT
      LAYER M5 ;
        RECT  20.976 0 21 0.084 ;
    END
  END t_d[170]
  PIN t_d[171]
    DIRECTION INPUT ;
    USE SIGNAL ;
    PORT
      LAYER M5 ;
        RECT  21.072 0 21.096 0.084 ;
    END
  END t_d[171]
  PIN t_d[172]
    DIRECTION INPUT ;
    USE SIGNAL ;
    PORT
      LAYER M5 ;
        RECT  21.168 0 21.192 0.084 ;
    END
  END t_d[172]
  PIN t_d[173]
    DIRECTION INPUT ;
    USE SIGNAL ;
    PORT
      LAYER M5 ;
        RECT  21.264 0 21.288 0.084 ;
    END
  END t_d[173]
  PIN t_d[174]
    DIRECTION INPUT ;
    USE SIGNAL ;
    PORT
      LAYER M5 ;
        RECT  21.36 0 21.384 0.084 ;
    END
  END t_d[174]
  PIN t_d[175]
    DIRECTION INPUT ;
    USE SIGNAL ;
    PORT
      LAYER M5 ;
        RECT  21.456 0 21.48 0.084 ;
    END
  END t_d[175]
  PIN t_d[176]
    DIRECTION INPUT ;
    USE SIGNAL ;
    PORT
      LAYER M5 ;
        RECT  21.552 0 21.576 0.084 ;
    END
  END t_d[176]
  PIN t_d[177]
    DIRECTION INPUT ;
    USE SIGNAL ;
    PORT
      LAYER M5 ;
        RECT  21.648 0 21.672 0.084 ;
    END
  END t_d[177]
  PIN t_d[178]
    DIRECTION INPUT ;
    USE SIGNAL ;
    PORT
      LAYER M5 ;
        RECT  21.744 0 21.768 0.084 ;
    END
  END t_d[178]
  PIN t_d[179]
    DIRECTION INPUT ;
    USE SIGNAL ;
    PORT
      LAYER M5 ;
        RECT  21.84 0 21.864 0.084 ;
    END
  END t_d[179]
  PIN t_d[17]
    DIRECTION INPUT ;
    USE SIGNAL ;
    PORT
      LAYER M5 ;
        RECT  40.848 0 40.872 0.084 ;
    END
  END t_d[17]
  PIN t_d[180]
    DIRECTION INPUT ;
    USE SIGNAL ;
    PORT
      LAYER M5 ;
        RECT  21.936 0 21.96 0.084 ;
    END
  END t_d[180]
  PIN t_d[181]
    DIRECTION INPUT ;
    USE SIGNAL ;
    PORT
      LAYER M5 ;
        RECT  22.032 0 22.056 0.084 ;
    END
  END t_d[181]
  PIN t_d[182]
    DIRECTION INPUT ;
    USE SIGNAL ;
    PORT
      LAYER M5 ;
        RECT  22.128 0 22.152 0.084 ;
    END
  END t_d[182]
  PIN t_d[183]
    DIRECTION INPUT ;
    USE SIGNAL ;
    PORT
      LAYER M5 ;
        RECT  22.224 0 22.248 0.084 ;
    END
  END t_d[183]
  PIN t_d[184]
    DIRECTION INPUT ;
    USE SIGNAL ;
    PORT
      LAYER M5 ;
        RECT  22.32 0 22.344 0.084 ;
    END
  END t_d[184]
  PIN t_d[185]
    DIRECTION INPUT ;
    USE SIGNAL ;
    PORT
      LAYER M5 ;
        RECT  22.416 0 22.44 0.084 ;
    END
  END t_d[185]
  PIN t_d[186]
    DIRECTION INPUT ;
    USE SIGNAL ;
    PORT
      LAYER M5 ;
        RECT  22.512 0 22.536 0.084 ;
    END
  END t_d[186]
  PIN t_d[187]
    DIRECTION INPUT ;
    USE SIGNAL ;
    PORT
      LAYER M5 ;
        RECT  22.608 0 22.632 0.084 ;
    END
  END t_d[187]
  PIN t_d[188]
    DIRECTION INPUT ;
    USE SIGNAL ;
    PORT
      LAYER M5 ;
        RECT  22.704 0 22.728 0.084 ;
    END
  END t_d[188]
  PIN t_d[189]
    DIRECTION INPUT ;
    USE SIGNAL ;
    PORT
      LAYER M5 ;
        RECT  22.8 0 22.824 0.084 ;
    END
  END t_d[189]
  PIN t_d[18]
    DIRECTION INPUT ;
    USE SIGNAL ;
    PORT
      LAYER M5 ;
        RECT  40.944 0 40.968 0.084 ;
    END
  END t_d[18]
  PIN t_d[190]
    DIRECTION INPUT ;
    USE SIGNAL ;
    PORT
      LAYER M5 ;
        RECT  22.896 0 22.92 0.084 ;
    END
  END t_d[190]
  PIN t_d[191]
    DIRECTION INPUT ;
    USE SIGNAL ;
    PORT
      LAYER M5 ;
        RECT  45.264 0 45.288 0.084 ;
    END
  END t_d[191]
  PIN t_d[192]
    DIRECTION INPUT ;
    USE SIGNAL ;
    PORT
      LAYER M5 ;
        RECT  45.36 0 45.384 0.084 ;
    END
  END t_d[192]
  PIN t_d[193]
    DIRECTION INPUT ;
    USE SIGNAL ;
    PORT
      LAYER M5 ;
        RECT  45.456 0 45.48 0.084 ;
    END
  END t_d[193]
  PIN t_d[194]
    DIRECTION INPUT ;
    USE SIGNAL ;
    PORT
      LAYER M5 ;
        RECT  45.552 0 45.576 0.084 ;
    END
  END t_d[194]
  PIN t_d[195]
    DIRECTION INPUT ;
    USE SIGNAL ;
    PORT
      LAYER M5 ;
        RECT  45.648 0 45.672 0.084 ;
    END
  END t_d[195]
  PIN t_d[196]
    DIRECTION INPUT ;
    USE SIGNAL ;
    PORT
      LAYER M5 ;
        RECT  45.744 0 45.768 0.084 ;
    END
  END t_d[196]
  PIN t_d[197]
    DIRECTION INPUT ;
    USE SIGNAL ;
    PORT
      LAYER M5 ;
        RECT  45.84 0 45.864 0.084 ;
    END
  END t_d[197]
  PIN t_d[198]
    DIRECTION INPUT ;
    USE SIGNAL ;
    PORT
      LAYER M5 ;
        RECT  45.936 0 45.96 0.084 ;
    END
  END t_d[198]
  PIN t_d[199]
    DIRECTION INPUT ;
    USE SIGNAL ;
    PORT
      LAYER M5 ;
        RECT  46.032 0 46.056 0.084 ;
    END
  END t_d[199]
  PIN t_d[19]
    DIRECTION INPUT ;
    USE SIGNAL ;
    PORT
      LAYER M5 ;
        RECT  41.04 0 41.064 0.084 ;
    END
  END t_d[19]
  PIN t_d[1]
    DIRECTION INPUT ;
    USE SIGNAL ;
    PORT
      LAYER M5 ;
        RECT  39.312 0 39.336 0.084 ;
    END
  END t_d[1]
  PIN t_d[200]
    DIRECTION INPUT ;
    USE SIGNAL ;
    PORT
      LAYER M5 ;
        RECT  46.128 0 46.152 0.084 ;
    END
  END t_d[200]
  PIN t_d[201]
    DIRECTION INPUT ;
    USE SIGNAL ;
    PORT
      LAYER M5 ;
        RECT  46.224 0 46.248 0.084 ;
    END
  END t_d[201]
  PIN t_d[202]
    DIRECTION INPUT ;
    USE SIGNAL ;
    PORT
      LAYER M5 ;
        RECT  46.32 0 46.344 0.084 ;
    END
  END t_d[202]
  PIN t_d[203]
    DIRECTION INPUT ;
    USE SIGNAL ;
    PORT
      LAYER M5 ;
        RECT  46.416 0 46.44 0.084 ;
    END
  END t_d[203]
  PIN t_d[204]
    DIRECTION INPUT ;
    USE SIGNAL ;
    PORT
      LAYER M5 ;
        RECT  46.512 0 46.536 0.084 ;
    END
  END t_d[204]
  PIN t_d[205]
    DIRECTION INPUT ;
    USE SIGNAL ;
    PORT
      LAYER M5 ;
        RECT  46.608 0 46.632 0.084 ;
    END
  END t_d[205]
  PIN t_d[206]
    DIRECTION INPUT ;
    USE SIGNAL ;
    PORT
      LAYER M5 ;
        RECT  46.704 0 46.728 0.084 ;
    END
  END t_d[206]
  PIN t_d[207]
    DIRECTION INPUT ;
    USE SIGNAL ;
    PORT
      LAYER M5 ;
        RECT  46.8 0 46.824 0.084 ;
    END
  END t_d[207]
  PIN t_d[208]
    DIRECTION INPUT ;
    USE SIGNAL ;
    PORT
      LAYER M5 ;
        RECT  46.896 0 46.92 0.084 ;
    END
  END t_d[208]
  PIN t_d[209]
    DIRECTION INPUT ;
    USE SIGNAL ;
    PORT
      LAYER M5 ;
        RECT  46.992 0 47.016 0.084 ;
    END
  END t_d[209]
  PIN t_d[20]
    DIRECTION INPUT ;
    USE SIGNAL ;
    PORT
      LAYER M5 ;
        RECT  41.136 0 41.16 0.084 ;
    END
  END t_d[20]
  PIN t_d[210]
    DIRECTION INPUT ;
    USE SIGNAL ;
    PORT
      LAYER M5 ;
        RECT  47.088 0 47.112 0.084 ;
    END
  END t_d[210]
  PIN t_d[211]
    DIRECTION INPUT ;
    USE SIGNAL ;
    PORT
      LAYER M5 ;
        RECT  47.184 0 47.208 0.084 ;
    END
  END t_d[211]
  PIN t_d[212]
    DIRECTION INPUT ;
    USE SIGNAL ;
    PORT
      LAYER M5 ;
        RECT  47.28 0 47.304 0.084 ;
    END
  END t_d[212]
  PIN t_d[213]
    DIRECTION INPUT ;
    USE SIGNAL ;
    PORT
      LAYER M5 ;
        RECT  47.376 0 47.4 0.084 ;
    END
  END t_d[213]
  PIN t_d[214]
    DIRECTION INPUT ;
    USE SIGNAL ;
    PORT
      LAYER M5 ;
        RECT  47.472 0 47.496 0.084 ;
    END
  END t_d[214]
  PIN t_d[215]
    DIRECTION INPUT ;
    USE SIGNAL ;
    PORT
      LAYER M5 ;
        RECT  47.568 0 47.592 0.084 ;
    END
  END t_d[215]
  PIN t_d[216]
    DIRECTION INPUT ;
    USE SIGNAL ;
    PORT
      LAYER M5 ;
        RECT  47.664 0 47.688 0.084 ;
    END
  END t_d[216]
  PIN t_d[217]
    DIRECTION INPUT ;
    USE SIGNAL ;
    PORT
      LAYER M5 ;
        RECT  47.76 0 47.784 0.084 ;
    END
  END t_d[217]
  PIN t_d[218]
    DIRECTION INPUT ;
    USE SIGNAL ;
    PORT
      LAYER M5 ;
        RECT  47.856 0 47.88 0.084 ;
    END
  END t_d[218]
  PIN t_d[219]
    DIRECTION INPUT ;
    USE SIGNAL ;
    PORT
      LAYER M5 ;
        RECT  47.952 0 47.976 0.084 ;
    END
  END t_d[219]
  PIN t_d[21]
    DIRECTION INPUT ;
    USE SIGNAL ;
    PORT
      LAYER M5 ;
        RECT  41.232 0 41.256 0.084 ;
    END
  END t_d[21]
  PIN t_d[220]
    DIRECTION INPUT ;
    USE SIGNAL ;
    PORT
      LAYER M5 ;
        RECT  48.048 0 48.072 0.084 ;
    END
  END t_d[220]
  PIN t_d[221]
    DIRECTION INPUT ;
    USE SIGNAL ;
    PORT
      LAYER M5 ;
        RECT  48.144 0 48.168 0.084 ;
    END
  END t_d[221]
  PIN t_d[222]
    DIRECTION INPUT ;
    USE SIGNAL ;
    PORT
      LAYER M5 ;
        RECT  48.24 0 48.264 0.084 ;
    END
  END t_d[222]
  PIN t_d[223]
    DIRECTION INPUT ;
    USE SIGNAL ;
    PORT
      LAYER M5 ;
        RECT  54.48 0 54.504 0.084 ;
    END
  END t_d[223]
  PIN t_d[224]
    DIRECTION INPUT ;
    USE SIGNAL ;
    PORT
      LAYER M5 ;
        RECT  54.576 0 54.6 0.084 ;
    END
  END t_d[224]
  PIN t_d[225]
    DIRECTION INPUT ;
    USE SIGNAL ;
    PORT
      LAYER M5 ;
        RECT  54.672 0 54.696 0.084 ;
    END
  END t_d[225]
  PIN t_d[226]
    DIRECTION INPUT ;
    USE SIGNAL ;
    PORT
      LAYER M5 ;
        RECT  54.768 0 54.792 0.084 ;
    END
  END t_d[226]
  PIN t_d[227]
    DIRECTION INPUT ;
    USE SIGNAL ;
    PORT
      LAYER M5 ;
        RECT  54.864 0 54.888 0.084 ;
    END
  END t_d[227]
  PIN t_d[228]
    DIRECTION INPUT ;
    USE SIGNAL ;
    PORT
      LAYER M5 ;
        RECT  54.96 0 54.984 0.084 ;
    END
  END t_d[228]
  PIN t_d[229]
    DIRECTION INPUT ;
    USE SIGNAL ;
    PORT
      LAYER M5 ;
        RECT  55.056 0 55.08 0.084 ;
    END
  END t_d[229]
  PIN t_d[22]
    DIRECTION INPUT ;
    USE SIGNAL ;
    PORT
      LAYER M5 ;
        RECT  41.328 0 41.352 0.084 ;
    END
  END t_d[22]
  PIN t_d[230]
    DIRECTION INPUT ;
    USE SIGNAL ;
    PORT
      LAYER M5 ;
        RECT  55.152 0 55.176 0.084 ;
    END
  END t_d[230]
  PIN t_d[231]
    DIRECTION INPUT ;
    USE SIGNAL ;
    PORT
      LAYER M5 ;
        RECT  55.248 0 55.272 0.084 ;
    END
  END t_d[231]
  PIN t_d[232]
    DIRECTION INPUT ;
    USE SIGNAL ;
    PORT
      LAYER M5 ;
        RECT  55.344 0 55.368 0.084 ;
    END
  END t_d[232]
  PIN t_d[233]
    DIRECTION INPUT ;
    USE SIGNAL ;
    PORT
      LAYER M5 ;
        RECT  55.44 0 55.464 0.084 ;
    END
  END t_d[233]
  PIN t_d[234]
    DIRECTION INPUT ;
    USE SIGNAL ;
    PORT
      LAYER M5 ;
        RECT  55.536 0 55.56 0.084 ;
    END
  END t_d[234]
  PIN t_d[235]
    DIRECTION INPUT ;
    USE SIGNAL ;
    PORT
      LAYER M5 ;
        RECT  55.632 0 55.656 0.084 ;
    END
  END t_d[235]
  PIN t_d[236]
    DIRECTION INPUT ;
    USE SIGNAL ;
    PORT
      LAYER M5 ;
        RECT  55.728 0 55.752 0.084 ;
    END
  END t_d[236]
  PIN t_d[237]
    DIRECTION INPUT ;
    USE SIGNAL ;
    PORT
      LAYER M5 ;
        RECT  55.824 0 55.848 0.084 ;
    END
  END t_d[237]
  PIN t_d[238]
    DIRECTION INPUT ;
    USE SIGNAL ;
    PORT
      LAYER M5 ;
        RECT  55.92 0 55.944 0.084 ;
    END
  END t_d[238]
  PIN t_d[239]
    DIRECTION INPUT ;
    USE SIGNAL ;
    PORT
      LAYER M5 ;
        RECT  56.016 0 56.04 0.084 ;
    END
  END t_d[239]
  PIN t_d[23]
    DIRECTION INPUT ;
    USE SIGNAL ;
    PORT
      LAYER M5 ;
        RECT  41.424 0 41.448 0.084 ;
    END
  END t_d[23]
  PIN t_d[240]
    DIRECTION INPUT ;
    USE SIGNAL ;
    PORT
      LAYER M5 ;
        RECT  56.112 0 56.136 0.084 ;
    END
  END t_d[240]
  PIN t_d[241]
    DIRECTION INPUT ;
    USE SIGNAL ;
    PORT
      LAYER M5 ;
        RECT  56.208 0 56.232 0.084 ;
    END
  END t_d[241]
  PIN t_d[242]
    DIRECTION INPUT ;
    USE SIGNAL ;
    PORT
      LAYER M5 ;
        RECT  56.304 0 56.328 0.084 ;
    END
  END t_d[242]
  PIN t_d[243]
    DIRECTION INPUT ;
    USE SIGNAL ;
    PORT
      LAYER M5 ;
        RECT  56.4 0 56.424 0.084 ;
    END
  END t_d[243]
  PIN t_d[244]
    DIRECTION INPUT ;
    USE SIGNAL ;
    PORT
      LAYER M5 ;
        RECT  56.496 0 56.52 0.084 ;
    END
  END t_d[244]
  PIN t_d[245]
    DIRECTION INPUT ;
    USE SIGNAL ;
    PORT
      LAYER M5 ;
        RECT  56.592 0 56.616 0.084 ;
    END
  END t_d[245]
  PIN t_d[246]
    DIRECTION INPUT ;
    USE SIGNAL ;
    PORT
      LAYER M5 ;
        RECT  56.688 0 56.712 0.084 ;
    END
  END t_d[246]
  PIN t_d[247]
    DIRECTION INPUT ;
    USE SIGNAL ;
    PORT
      LAYER M5 ;
        RECT  56.784 0 56.808 0.084 ;
    END
  END t_d[247]
  PIN t_d[248]
    DIRECTION INPUT ;
    USE SIGNAL ;
    PORT
      LAYER M5 ;
        RECT  56.88 0 56.904 0.084 ;
    END
  END t_d[248]
  PIN t_d[249]
    DIRECTION INPUT ;
    USE SIGNAL ;
    PORT
      LAYER M5 ;
        RECT  56.976 0 57 0.084 ;
    END
  END t_d[249]
  PIN t_d[24]
    DIRECTION INPUT ;
    USE SIGNAL ;
    PORT
      LAYER M5 ;
        RECT  41.52 0 41.544 0.084 ;
    END
  END t_d[24]
  PIN t_d[250]
    DIRECTION INPUT ;
    USE SIGNAL ;
    PORT
      LAYER M5 ;
        RECT  57.072 0 57.096 0.084 ;
    END
  END t_d[250]
  PIN t_d[251]
    DIRECTION INPUT ;
    USE SIGNAL ;
    PORT
      LAYER M5 ;
        RECT  57.168 0 57.192 0.084 ;
    END
  END t_d[251]
  PIN t_d[252]
    DIRECTION INPUT ;
    USE SIGNAL ;
    PORT
      LAYER M5 ;
        RECT  57.264 0 57.288 0.084 ;
    END
  END t_d[252]
  PIN t_d[253]
    DIRECTION INPUT ;
    USE SIGNAL ;
    PORT
      LAYER M5 ;
        RECT  57.36 0 57.384 0.084 ;
    END
  END t_d[253]
  PIN t_d[254]
    DIRECTION INPUT ;
    USE SIGNAL ;
    PORT
      LAYER M5 ;
        RECT  57.456 0 57.48 0.084 ;
    END
  END t_d[254]
  PIN t_d[255]
    DIRECTION INPUT ;
    USE SIGNAL ;
    PORT
      LAYER M5 ;
        RECT  32.208 0 32.232 0.084 ;
    END
  END t_d[255]
  PIN t_d[256]
    DIRECTION INPUT ;
    USE SIGNAL ;
    PORT
      LAYER M5 ;
        RECT  32.304 0 32.328 0.084 ;
    END
  END t_d[256]
  PIN t_d[257]
    DIRECTION INPUT ;
    USE SIGNAL ;
    PORT
      LAYER M5 ;
        RECT  32.4 0 32.424 0.084 ;
    END
  END t_d[257]
  PIN t_d[258]
    DIRECTION INPUT ;
    USE SIGNAL ;
    PORT
      LAYER M5 ;
        RECT  32.496 0 32.52 0.084 ;
    END
  END t_d[258]
  PIN t_d[259]
    DIRECTION INPUT ;
    USE SIGNAL ;
    PORT
      LAYER M5 ;
        RECT  32.592 0 32.616 0.084 ;
    END
  END t_d[259]
  PIN t_d[25]
    DIRECTION INPUT ;
    USE SIGNAL ;
    PORT
      LAYER M5 ;
        RECT  41.616 0 41.64 0.084 ;
    END
  END t_d[25]
  PIN t_d[260]
    DIRECTION INPUT ;
    USE SIGNAL ;
    PORT
      LAYER M5 ;
        RECT  32.688 0 32.712 0.084 ;
    END
  END t_d[260]
  PIN t_d[261]
    DIRECTION INPUT ;
    USE SIGNAL ;
    PORT
      LAYER M5 ;
        RECT  32.784 0 32.808 0.084 ;
    END
  END t_d[261]
  PIN t_d[262]
    DIRECTION INPUT ;
    USE SIGNAL ;
    PORT
      LAYER M5 ;
        RECT  32.88 0 32.904 0.084 ;
    END
  END t_d[262]
  PIN t_d[263]
    DIRECTION INPUT ;
    USE SIGNAL ;
    PORT
      LAYER M5 ;
        RECT  32.976 0 33 0.084 ;
    END
  END t_d[263]
  PIN t_d[264]
    DIRECTION INPUT ;
    USE SIGNAL ;
    PORT
      LAYER M5 ;
        RECT  33.072 0 33.096 0.084 ;
    END
  END t_d[264]
  PIN t_d[265]
    DIRECTION INPUT ;
    USE SIGNAL ;
    PORT
      LAYER M5 ;
        RECT  33.168 0 33.192 0.084 ;
    END
  END t_d[265]
  PIN t_d[266]
    DIRECTION INPUT ;
    USE SIGNAL ;
    PORT
      LAYER M5 ;
        RECT  33.264 0 33.288 0.084 ;
    END
  END t_d[266]
  PIN t_d[267]
    DIRECTION INPUT ;
    USE SIGNAL ;
    PORT
      LAYER M5 ;
        RECT  33.36 0 33.384 0.084 ;
    END
  END t_d[267]
  PIN t_d[268]
    DIRECTION INPUT ;
    USE SIGNAL ;
    PORT
      LAYER M5 ;
        RECT  33.456 0 33.48 0.084 ;
    END
  END t_d[268]
  PIN t_d[269]
    DIRECTION INPUT ;
    USE SIGNAL ;
    PORT
      LAYER M5 ;
        RECT  33.552 0 33.576 0.084 ;
    END
  END t_d[269]
  PIN t_d[26]
    DIRECTION INPUT ;
    USE SIGNAL ;
    PORT
      LAYER M5 ;
        RECT  41.712 0 41.736 0.084 ;
    END
  END t_d[26]
  PIN t_d[270]
    DIRECTION INPUT ;
    USE SIGNAL ;
    PORT
      LAYER M5 ;
        RECT  33.648 0 33.672 0.084 ;
    END
  END t_d[270]
  PIN t_d[271]
    DIRECTION INPUT ;
    USE SIGNAL ;
    PORT
      LAYER M5 ;
        RECT  33.744 0 33.768 0.084 ;
    END
  END t_d[271]
  PIN t_d[272]
    DIRECTION INPUT ;
    USE SIGNAL ;
    PORT
      LAYER M5 ;
        RECT  33.84 0 33.864 0.084 ;
    END
  END t_d[272]
  PIN t_d[273]
    DIRECTION INPUT ;
    USE SIGNAL ;
    PORT
      LAYER M5 ;
        RECT  33.936 0 33.96 0.084 ;
    END
  END t_d[273]
  PIN t_d[274]
    DIRECTION INPUT ;
    USE SIGNAL ;
    PORT
      LAYER M5 ;
        RECT  34.032 0 34.056 0.084 ;
    END
  END t_d[274]
  PIN t_d[275]
    DIRECTION INPUT ;
    USE SIGNAL ;
    PORT
      LAYER M5 ;
        RECT  34.128 0 34.152 0.084 ;
    END
  END t_d[275]
  PIN t_d[276]
    DIRECTION INPUT ;
    USE SIGNAL ;
    PORT
      LAYER M5 ;
        RECT  34.224 0 34.248 0.084 ;
    END
  END t_d[276]
  PIN t_d[277]
    DIRECTION INPUT ;
    USE SIGNAL ;
    PORT
      LAYER M5 ;
        RECT  34.32 0 34.344 0.084 ;
    END
  END t_d[277]
  PIN t_d[278]
    DIRECTION INPUT ;
    USE SIGNAL ;
    PORT
      LAYER M5 ;
        RECT  34.416 0 34.44 0.084 ;
    END
  END t_d[278]
  PIN t_d[279]
    DIRECTION INPUT ;
    USE SIGNAL ;
    PORT
      LAYER M5 ;
        RECT  34.512 0 34.536 0.084 ;
    END
  END t_d[279]
  PIN t_d[27]
    DIRECTION INPUT ;
    USE SIGNAL ;
    PORT
      LAYER M5 ;
        RECT  41.808 0 41.832 0.084 ;
    END
  END t_d[27]
  PIN t_d[280]
    DIRECTION INPUT ;
    USE SIGNAL ;
    PORT
      LAYER M5 ;
        RECT  34.608 0 34.632 0.084 ;
    END
  END t_d[280]
  PIN t_d[281]
    DIRECTION INPUT ;
    USE SIGNAL ;
    PORT
      LAYER M5 ;
        RECT  34.704 0 34.728 0.084 ;
    END
  END t_d[281]
  PIN t_d[282]
    DIRECTION INPUT ;
    USE SIGNAL ;
    PORT
      LAYER M5 ;
        RECT  34.8 0 34.824 0.084 ;
    END
  END t_d[282]
  PIN t_d[283]
    DIRECTION INPUT ;
    USE SIGNAL ;
    PORT
      LAYER M5 ;
        RECT  34.896 0 34.92 0.084 ;
    END
  END t_d[283]
  PIN t_d[284]
    DIRECTION INPUT ;
    USE SIGNAL ;
    PORT
      LAYER M5 ;
        RECT  34.992 0 35.016 0.084 ;
    END
  END t_d[284]
  PIN t_d[285]
    DIRECTION INPUT ;
    USE SIGNAL ;
    PORT
      LAYER M5 ;
        RECT  35.088 0 35.112 0.084 ;
    END
  END t_d[285]
  PIN t_d[286]
    DIRECTION INPUT ;
    USE SIGNAL ;
    PORT
      LAYER M5 ;
        RECT  35.184 0 35.208 0.084 ;
    END
  END t_d[286]
  PIN t_d[287]
    DIRECTION INPUT ;
    USE SIGNAL ;
    PORT
      LAYER M5 ;
        RECT  35.28 0 35.304 0.084 ;
    END
  END t_d[287]
  PIN t_d[288]
    DIRECTION INPUT ;
    USE SIGNAL ;
    PORT
      LAYER M5 ;
        RECT  35.376 0 35.4 0.084 ;
    END
  END t_d[288]
  PIN t_d[289]
    DIRECTION INPUT ;
    USE SIGNAL ;
    PORT
      LAYER M5 ;
        RECT  35.472 0 35.496 0.084 ;
    END
  END t_d[289]
  PIN t_d[28]
    DIRECTION INPUT ;
    USE SIGNAL ;
    PORT
      LAYER M5 ;
        RECT  41.904 0 41.928 0.084 ;
    END
  END t_d[28]
  PIN t_d[290]
    DIRECTION INPUT ;
    USE SIGNAL ;
    PORT
      LAYER M5 ;
        RECT  35.568 0 35.592 0.084 ;
    END
  END t_d[290]
  PIN t_d[291]
    DIRECTION INPUT ;
    USE SIGNAL ;
    PORT
      LAYER M5 ;
        RECT  35.664 0 35.688 0.084 ;
    END
  END t_d[291]
  PIN t_d[292]
    DIRECTION INPUT ;
    USE SIGNAL ;
    PORT
      LAYER M5 ;
        RECT  35.76 0 35.784 0.084 ;
    END
  END t_d[292]
  PIN t_d[293]
    DIRECTION INPUT ;
    USE SIGNAL ;
    PORT
      LAYER M5 ;
        RECT  35.856 0 35.88 0.084 ;
    END
  END t_d[293]
  PIN t_d[294]
    DIRECTION INPUT ;
    USE SIGNAL ;
    PORT
      LAYER M5 ;
        RECT  35.952 0 35.976 0.084 ;
    END
  END t_d[294]
  PIN t_d[295]
    DIRECTION INPUT ;
    USE SIGNAL ;
    PORT
      LAYER M5 ;
        RECT  36.048 0 36.072 0.084 ;
    END
  END t_d[295]
  PIN t_d[296]
    DIRECTION INPUT ;
    USE SIGNAL ;
    PORT
      LAYER M5 ;
        RECT  36.144 0 36.168 0.084 ;
    END
  END t_d[296]
  PIN t_d[297]
    DIRECTION INPUT ;
    USE SIGNAL ;
    PORT
      LAYER M5 ;
        RECT  36.24 0 36.264 0.084 ;
    END
  END t_d[297]
  PIN t_d[298]
    DIRECTION INPUT ;
    USE SIGNAL ;
    PORT
      LAYER M5 ;
        RECT  36.336 0 36.36 0.084 ;
    END
  END t_d[298]
  PIN t_d[299]
    DIRECTION INPUT ;
    USE SIGNAL ;
    PORT
      LAYER M5 ;
        RECT  36.432 0 36.456 0.084 ;
    END
  END t_d[299]
  PIN t_d[29]
    DIRECTION INPUT ;
    USE SIGNAL ;
    PORT
      LAYER M5 ;
        RECT  42 0 42.024 0.084 ;
    END
  END t_d[29]
  PIN t_d[2]
    DIRECTION INPUT ;
    USE SIGNAL ;
    PORT
      LAYER M5 ;
        RECT  39.408 0 39.432 0.084 ;
    END
  END t_d[2]
  PIN t_d[300]
    DIRECTION INPUT ;
    USE SIGNAL ;
    PORT
      LAYER M5 ;
        RECT  36.528 0 36.552 0.084 ;
    END
  END t_d[300]
  PIN t_d[301]
    DIRECTION INPUT ;
    USE SIGNAL ;
    PORT
      LAYER M5 ;
        RECT  36.624 0 36.648 0.084 ;
    END
  END t_d[301]
  PIN t_d[302]
    DIRECTION INPUT ;
    USE SIGNAL ;
    PORT
      LAYER M5 ;
        RECT  36.72 0 36.744 0.084 ;
    END
  END t_d[302]
  PIN t_d[303]
    DIRECTION INPUT ;
    USE SIGNAL ;
    PORT
      LAYER M5 ;
        RECT  36.816 0 36.84 0.084 ;
    END
  END t_d[303]
  PIN t_d[304]
    DIRECTION INPUT ;
    USE SIGNAL ;
    PORT
      LAYER M5 ;
        RECT  36.912 0 36.936 0.084 ;
    END
  END t_d[304]
  PIN t_d[305]
    DIRECTION INPUT ;
    USE SIGNAL ;
    PORT
      LAYER M5 ;
        RECT  37.008 0 37.032 0.084 ;
    END
  END t_d[305]
  PIN t_d[306]
    DIRECTION INPUT ;
    USE SIGNAL ;
    PORT
      LAYER M5 ;
        RECT  37.104 0 37.128 0.084 ;
    END
  END t_d[306]
  PIN t_d[307]
    DIRECTION INPUT ;
    USE SIGNAL ;
    PORT
      LAYER M5 ;
        RECT  37.2 0 37.224 0.084 ;
    END
  END t_d[307]
  PIN t_d[308]
    DIRECTION INPUT ;
    USE SIGNAL ;
    PORT
      LAYER M5 ;
        RECT  37.296 0 37.32 0.084 ;
    END
  END t_d[308]
  PIN t_d[309]
    DIRECTION INPUT ;
    USE SIGNAL ;
    PORT
      LAYER M5 ;
        RECT  37.392 0 37.416 0.084 ;
    END
  END t_d[309]
  PIN t_d[30]
    DIRECTION INPUT ;
    USE SIGNAL ;
    PORT
      LAYER M5 ;
        RECT  42.096 0 42.12 0.084 ;
    END
  END t_d[30]
  PIN t_d[310]
    DIRECTION INPUT ;
    USE SIGNAL ;
    PORT
      LAYER M5 ;
        RECT  37.488 0 37.512 0.084 ;
    END
  END t_d[310]
  PIN t_d[311]
    DIRECTION INPUT ;
    USE SIGNAL ;
    PORT
      LAYER M5 ;
        RECT  37.584 0 37.608 0.084 ;
    END
  END t_d[311]
  PIN t_d[312]
    DIRECTION INPUT ;
    USE SIGNAL ;
    PORT
      LAYER M5 ;
        RECT  37.68 0 37.704 0.084 ;
    END
  END t_d[312]
  PIN t_d[313]
    DIRECTION INPUT ;
    USE SIGNAL ;
    PORT
      LAYER M5 ;
        RECT  37.776 0 37.8 0.084 ;
    END
  END t_d[313]
  PIN t_d[314]
    DIRECTION INPUT ;
    USE SIGNAL ;
    PORT
      LAYER M5 ;
        RECT  37.872 0 37.896 0.084 ;
    END
  END t_d[314]
  PIN t_d[315]
    DIRECTION INPUT ;
    USE SIGNAL ;
    PORT
      LAYER M5 ;
        RECT  37.968 0 37.992 0.084 ;
    END
  END t_d[315]
  PIN t_d[316]
    DIRECTION INPUT ;
    USE SIGNAL ;
    PORT
      LAYER M5 ;
        RECT  38.064 0 38.088 0.084 ;
    END
  END t_d[316]
  PIN t_d[317]
    DIRECTION INPUT ;
    USE SIGNAL ;
    PORT
      LAYER M5 ;
        RECT  38.16 0 38.184 0.084 ;
    END
  END t_d[317]
  PIN t_d[318]
    DIRECTION INPUT ;
    USE SIGNAL ;
    PORT
      LAYER M5 ;
        RECT  38.256 0 38.28 0.084 ;
    END
  END t_d[318]
  PIN t_d[319]
    DIRECTION INPUT ;
    USE SIGNAL ;
    PORT
      LAYER M5 ;
        RECT  26.064 0 26.088 0.084 ;
    END
  END t_d[319]
  PIN t_d[31]
    DIRECTION INPUT ;
    USE SIGNAL ;
    PORT
      LAYER M5 ;
        RECT  51.408 0 51.432 0.084 ;
    END
  END t_d[31]
  PIN t_d[320]
    DIRECTION INPUT ;
    USE SIGNAL ;
    PORT
      LAYER M5 ;
        RECT  26.16 0 26.184 0.084 ;
    END
  END t_d[320]
  PIN t_d[321]
    DIRECTION INPUT ;
    USE SIGNAL ;
    PORT
      LAYER M5 ;
        RECT  26.256 0 26.28 0.084 ;
    END
  END t_d[321]
  PIN t_d[322]
    DIRECTION INPUT ;
    USE SIGNAL ;
    PORT
      LAYER M5 ;
        RECT  26.352 0 26.376 0.084 ;
    END
  END t_d[322]
  PIN t_d[323]
    DIRECTION INPUT ;
    USE SIGNAL ;
    PORT
      LAYER M5 ;
        RECT  26.448 0 26.472 0.084 ;
    END
  END t_d[323]
  PIN t_d[324]
    DIRECTION INPUT ;
    USE SIGNAL ;
    PORT
      LAYER M5 ;
        RECT  26.544 0 26.568 0.084 ;
    END
  END t_d[324]
  PIN t_d[325]
    DIRECTION INPUT ;
    USE SIGNAL ;
    PORT
      LAYER M5 ;
        RECT  26.64 0 26.664 0.084 ;
    END
  END t_d[325]
  PIN t_d[326]
    DIRECTION INPUT ;
    USE SIGNAL ;
    PORT
      LAYER M5 ;
        RECT  26.736 0 26.76 0.084 ;
    END
  END t_d[326]
  PIN t_d[327]
    DIRECTION INPUT ;
    USE SIGNAL ;
    PORT
      LAYER M5 ;
        RECT  26.832 0 26.856 0.084 ;
    END
  END t_d[327]
  PIN t_d[328]
    DIRECTION INPUT ;
    USE SIGNAL ;
    PORT
      LAYER M5 ;
        RECT  26.928 0 26.952 0.084 ;
    END
  END t_d[328]
  PIN t_d[329]
    DIRECTION INPUT ;
    USE SIGNAL ;
    PORT
      LAYER M5 ;
        RECT  27.024 0 27.048 0.084 ;
    END
  END t_d[329]
  PIN t_d[32]
    DIRECTION INPUT ;
    USE SIGNAL ;
    PORT
      LAYER M5 ;
        RECT  51.504 0 51.528 0.084 ;
    END
  END t_d[32]
  PIN t_d[330]
    DIRECTION INPUT ;
    USE SIGNAL ;
    PORT
      LAYER M5 ;
        RECT  27.12 0 27.144 0.084 ;
    END
  END t_d[330]
  PIN t_d[331]
    DIRECTION INPUT ;
    USE SIGNAL ;
    PORT
      LAYER M5 ;
        RECT  27.216 0 27.24 0.084 ;
    END
  END t_d[331]
  PIN t_d[332]
    DIRECTION INPUT ;
    USE SIGNAL ;
    PORT
      LAYER M5 ;
        RECT  27.312 0 27.336 0.084 ;
    END
  END t_d[332]
  PIN t_d[333]
    DIRECTION INPUT ;
    USE SIGNAL ;
    PORT
      LAYER M5 ;
        RECT  27.408 0 27.432 0.084 ;
    END
  END t_d[333]
  PIN t_d[334]
    DIRECTION INPUT ;
    USE SIGNAL ;
    PORT
      LAYER M5 ;
        RECT  27.504 0 27.528 0.084 ;
    END
  END t_d[334]
  PIN t_d[335]
    DIRECTION INPUT ;
    USE SIGNAL ;
    PORT
      LAYER M5 ;
        RECT  27.6 0 27.624 0.084 ;
    END
  END t_d[335]
  PIN t_d[336]
    DIRECTION INPUT ;
    USE SIGNAL ;
    PORT
      LAYER M5 ;
        RECT  27.696 0 27.72 0.084 ;
    END
  END t_d[336]
  PIN t_d[337]
    DIRECTION INPUT ;
    USE SIGNAL ;
    PORT
      LAYER M5 ;
        RECT  27.792 0 27.816 0.084 ;
    END
  END t_d[337]
  PIN t_d[338]
    DIRECTION INPUT ;
    USE SIGNAL ;
    PORT
      LAYER M5 ;
        RECT  27.888 0 27.912 0.084 ;
    END
  END t_d[338]
  PIN t_d[339]
    DIRECTION INPUT ;
    USE SIGNAL ;
    PORT
      LAYER M5 ;
        RECT  27.984 0 28.008 0.084 ;
    END
  END t_d[339]
  PIN t_d[33]
    DIRECTION INPUT ;
    USE SIGNAL ;
    PORT
      LAYER M5 ;
        RECT  51.6 0 51.624 0.084 ;
    END
  END t_d[33]
  PIN t_d[340]
    DIRECTION INPUT ;
    USE SIGNAL ;
    PORT
      LAYER M5 ;
        RECT  28.08 0 28.104 0.084 ;
    END
  END t_d[340]
  PIN t_d[341]
    DIRECTION INPUT ;
    USE SIGNAL ;
    PORT
      LAYER M5 ;
        RECT  28.176 0 28.2 0.084 ;
    END
  END t_d[341]
  PIN t_d[342]
    DIRECTION INPUT ;
    USE SIGNAL ;
    PORT
      LAYER M5 ;
        RECT  28.272 0 28.296 0.084 ;
    END
  END t_d[342]
  PIN t_d[343]
    DIRECTION INPUT ;
    USE SIGNAL ;
    PORT
      LAYER M5 ;
        RECT  28.368 0 28.392 0.084 ;
    END
  END t_d[343]
  PIN t_d[344]
    DIRECTION INPUT ;
    USE SIGNAL ;
    PORT
      LAYER M5 ;
        RECT  28.464 0 28.488 0.084 ;
    END
  END t_d[344]
  PIN t_d[345]
    DIRECTION INPUT ;
    USE SIGNAL ;
    PORT
      LAYER M5 ;
        RECT  28.56 0 28.584 0.084 ;
    END
  END t_d[345]
  PIN t_d[346]
    DIRECTION INPUT ;
    USE SIGNAL ;
    PORT
      LAYER M5 ;
        RECT  28.656 0 28.68 0.084 ;
    END
  END t_d[346]
  PIN t_d[347]
    DIRECTION INPUT ;
    USE SIGNAL ;
    PORT
      LAYER M5 ;
        RECT  28.752 0 28.776 0.084 ;
    END
  END t_d[347]
  PIN t_d[348]
    DIRECTION INPUT ;
    USE SIGNAL ;
    PORT
      LAYER M5 ;
        RECT  28.848 0 28.872 0.084 ;
    END
  END t_d[348]
  PIN t_d[349]
    DIRECTION INPUT ;
    USE SIGNAL ;
    PORT
      LAYER M5 ;
        RECT  28.944 0 28.968 0.084 ;
    END
  END t_d[349]
  PIN t_d[34]
    DIRECTION INPUT ;
    USE SIGNAL ;
    PORT
      LAYER M5 ;
        RECT  51.696 0 51.72 0.084 ;
    END
  END t_d[34]
  PIN t_d[350]
    DIRECTION INPUT ;
    USE SIGNAL ;
    PORT
      LAYER M5 ;
        RECT  29.04 0 29.064 0.084 ;
    END
  END t_d[350]
  PIN t_d[351]
    DIRECTION INPUT ;
    USE SIGNAL ;
    PORT
      LAYER M5 ;
        RECT  22.992 0 23.016 0.084 ;
    END
  END t_d[351]
  PIN t_d[352]
    DIRECTION INPUT ;
    USE SIGNAL ;
    PORT
      LAYER M5 ;
        RECT  23.088 0 23.112 0.084 ;
    END
  END t_d[352]
  PIN t_d[353]
    DIRECTION INPUT ;
    USE SIGNAL ;
    PORT
      LAYER M5 ;
        RECT  23.184 0 23.208 0.084 ;
    END
  END t_d[353]
  PIN t_d[354]
    DIRECTION INPUT ;
    USE SIGNAL ;
    PORT
      LAYER M5 ;
        RECT  23.28 0 23.304 0.084 ;
    END
  END t_d[354]
  PIN t_d[355]
    DIRECTION INPUT ;
    USE SIGNAL ;
    PORT
      LAYER M5 ;
        RECT  23.376 0 23.4 0.084 ;
    END
  END t_d[355]
  PIN t_d[356]
    DIRECTION INPUT ;
    USE SIGNAL ;
    PORT
      LAYER M5 ;
        RECT  23.472 0 23.496 0.084 ;
    END
  END t_d[356]
  PIN t_d[357]
    DIRECTION INPUT ;
    USE SIGNAL ;
    PORT
      LAYER M5 ;
        RECT  23.568 0 23.592 0.084 ;
    END
  END t_d[357]
  PIN t_d[358]
    DIRECTION INPUT ;
    USE SIGNAL ;
    PORT
      LAYER M5 ;
        RECT  23.664 0 23.688 0.084 ;
    END
  END t_d[358]
  PIN t_d[359]
    DIRECTION INPUT ;
    USE SIGNAL ;
    PORT
      LAYER M5 ;
        RECT  23.76 0 23.784 0.084 ;
    END
  END t_d[359]
  PIN t_d[35]
    DIRECTION INPUT ;
    USE SIGNAL ;
    PORT
      LAYER M5 ;
        RECT  51.792 0 51.816 0.084 ;
    END
  END t_d[35]
  PIN t_d[360]
    DIRECTION INPUT ;
    USE SIGNAL ;
    PORT
      LAYER M5 ;
        RECT  23.856 0 23.88 0.084 ;
    END
  END t_d[360]
  PIN t_d[361]
    DIRECTION INPUT ;
    USE SIGNAL ;
    PORT
      LAYER M5 ;
        RECT  23.952 0 23.976 0.084 ;
    END
  END t_d[361]
  PIN t_d[362]
    DIRECTION INPUT ;
    USE SIGNAL ;
    PORT
      LAYER M5 ;
        RECT  24.048 0 24.072 0.084 ;
    END
  END t_d[362]
  PIN t_d[363]
    DIRECTION INPUT ;
    USE SIGNAL ;
    PORT
      LAYER M5 ;
        RECT  24.144 0 24.168 0.084 ;
    END
  END t_d[363]
  PIN t_d[364]
    DIRECTION INPUT ;
    USE SIGNAL ;
    PORT
      LAYER M5 ;
        RECT  24.24 0 24.264 0.084 ;
    END
  END t_d[364]
  PIN t_d[365]
    DIRECTION INPUT ;
    USE SIGNAL ;
    PORT
      LAYER M5 ;
        RECT  24.336 0 24.36 0.084 ;
    END
  END t_d[365]
  PIN t_d[366]
    DIRECTION INPUT ;
    USE SIGNAL ;
    PORT
      LAYER M5 ;
        RECT  24.432 0 24.456 0.084 ;
    END
  END t_d[366]
  PIN t_d[367]
    DIRECTION INPUT ;
    USE SIGNAL ;
    PORT
      LAYER M5 ;
        RECT  24.528 0 24.552 0.084 ;
    END
  END t_d[367]
  PIN t_d[368]
    DIRECTION INPUT ;
    USE SIGNAL ;
    PORT
      LAYER M5 ;
        RECT  24.624 0 24.648 0.084 ;
    END
  END t_d[368]
  PIN t_d[369]
    DIRECTION INPUT ;
    USE SIGNAL ;
    PORT
      LAYER M5 ;
        RECT  24.72 0 24.744 0.084 ;
    END
  END t_d[369]
  PIN t_d[36]
    DIRECTION INPUT ;
    USE SIGNAL ;
    PORT
      LAYER M5 ;
        RECT  51.888 0 51.912 0.084 ;
    END
  END t_d[36]
  PIN t_d[370]
    DIRECTION INPUT ;
    USE SIGNAL ;
    PORT
      LAYER M5 ;
        RECT  24.816 0 24.84 0.084 ;
    END
  END t_d[370]
  PIN t_d[371]
    DIRECTION INPUT ;
    USE SIGNAL ;
    PORT
      LAYER M5 ;
        RECT  24.912 0 24.936 0.084 ;
    END
  END t_d[371]
  PIN t_d[372]
    DIRECTION INPUT ;
    USE SIGNAL ;
    PORT
      LAYER M5 ;
        RECT  25.008 0 25.032 0.084 ;
    END
  END t_d[372]
  PIN t_d[373]
    DIRECTION INPUT ;
    USE SIGNAL ;
    PORT
      LAYER M5 ;
        RECT  25.104 0 25.128 0.084 ;
    END
  END t_d[373]
  PIN t_d[374]
    DIRECTION INPUT ;
    USE SIGNAL ;
    PORT
      LAYER M5 ;
        RECT  25.2 0 25.224 0.084 ;
    END
  END t_d[374]
  PIN t_d[375]
    DIRECTION INPUT ;
    USE SIGNAL ;
    PORT
      LAYER M5 ;
        RECT  25.296 0 25.32 0.084 ;
    END
  END t_d[375]
  PIN t_d[376]
    DIRECTION INPUT ;
    USE SIGNAL ;
    PORT
      LAYER M5 ;
        RECT  25.392 0 25.416 0.084 ;
    END
  END t_d[376]
  PIN t_d[377]
    DIRECTION INPUT ;
    USE SIGNAL ;
    PORT
      LAYER M5 ;
        RECT  25.488 0 25.512 0.084 ;
    END
  END t_d[377]
  PIN t_d[378]
    DIRECTION INPUT ;
    USE SIGNAL ;
    PORT
      LAYER M5 ;
        RECT  25.584 0 25.608 0.084 ;
    END
  END t_d[378]
  PIN t_d[379]
    DIRECTION INPUT ;
    USE SIGNAL ;
    PORT
      LAYER M5 ;
        RECT  25.68 0 25.704 0.084 ;
    END
  END t_d[379]
  PIN t_d[37]
    DIRECTION INPUT ;
    USE SIGNAL ;
    PORT
      LAYER M5 ;
        RECT  51.984 0 52.008 0.084 ;
    END
  END t_d[37]
  PIN t_d[380]
    DIRECTION INPUT ;
    USE SIGNAL ;
    PORT
      LAYER M5 ;
        RECT  25.776 0 25.8 0.084 ;
    END
  END t_d[380]
  PIN t_d[381]
    DIRECTION INPUT ;
    USE SIGNAL ;
    PORT
      LAYER M5 ;
        RECT  25.872 0 25.896 0.084 ;
    END
  END t_d[381]
  PIN t_d[382]
    DIRECTION INPUT ;
    USE SIGNAL ;
    PORT
      LAYER M5 ;
        RECT  25.968 0 25.992 0.084 ;
    END
  END t_d[382]
  PIN t_d[383]
    DIRECTION INPUT ;
    USE SIGNAL ;
    PORT
      LAYER M5 ;
        RECT  64.464 0 64.488 0.084 ;
    END
  END t_d[383]
  PIN t_d[384]
    DIRECTION INPUT ;
    USE SIGNAL ;
    PORT
      LAYER M5 ;
        RECT  64.56 0 64.584 0.084 ;
    END
  END t_d[384]
  PIN t_d[385]
    DIRECTION INPUT ;
    USE SIGNAL ;
    PORT
      LAYER M5 ;
        RECT  64.656 0 64.68 0.084 ;
    END
  END t_d[385]
  PIN t_d[386]
    DIRECTION INPUT ;
    USE SIGNAL ;
    PORT
      LAYER M5 ;
        RECT  64.752 0 64.776 0.084 ;
    END
  END t_d[386]
  PIN t_d[387]
    DIRECTION INPUT ;
    USE SIGNAL ;
    PORT
      LAYER M5 ;
        RECT  64.848 0 64.872 0.084 ;
    END
  END t_d[387]
  PIN t_d[388]
    DIRECTION INPUT ;
    USE SIGNAL ;
    PORT
      LAYER M5 ;
        RECT  64.944 0 64.968 0.084 ;
    END
  END t_d[388]
  PIN t_d[389]
    DIRECTION INPUT ;
    USE SIGNAL ;
    PORT
      LAYER M5 ;
        RECT  65.04 0 65.064 0.084 ;
    END
  END t_d[389]
  PIN t_d[38]
    DIRECTION INPUT ;
    USE SIGNAL ;
    PORT
      LAYER M5 ;
        RECT  52.08 0 52.104 0.084 ;
    END
  END t_d[38]
  PIN t_d[390]
    DIRECTION INPUT ;
    USE SIGNAL ;
    PORT
      LAYER M5 ;
        RECT  65.136 0 65.16 0.084 ;
    END
  END t_d[390]
  PIN t_d[391]
    DIRECTION INPUT ;
    USE SIGNAL ;
    PORT
      LAYER M5 ;
        RECT  65.232 0 65.256 0.084 ;
    END
  END t_d[391]
  PIN t_d[392]
    DIRECTION INPUT ;
    USE SIGNAL ;
    PORT
      LAYER M5 ;
        RECT  65.328 0 65.352 0.084 ;
    END
  END t_d[392]
  PIN t_d[393]
    DIRECTION INPUT ;
    USE SIGNAL ;
    PORT
      LAYER M5 ;
        RECT  65.424 0 65.448 0.084 ;
    END
  END t_d[393]
  PIN t_d[394]
    DIRECTION INPUT ;
    USE SIGNAL ;
    PORT
      LAYER M5 ;
        RECT  65.52 0 65.544 0.084 ;
    END
  END t_d[394]
  PIN t_d[395]
    DIRECTION INPUT ;
    USE SIGNAL ;
    PORT
      LAYER M5 ;
        RECT  65.616 0 65.64 0.084 ;
    END
  END t_d[395]
  PIN t_d[396]
    DIRECTION INPUT ;
    USE SIGNAL ;
    PORT
      LAYER M5 ;
        RECT  65.712 0 65.736 0.084 ;
    END
  END t_d[396]
  PIN t_d[397]
    DIRECTION INPUT ;
    USE SIGNAL ;
    PORT
      LAYER M5 ;
        RECT  65.808 0 65.832 0.084 ;
    END
  END t_d[397]
  PIN t_d[398]
    DIRECTION INPUT ;
    USE SIGNAL ;
    PORT
      LAYER M5 ;
        RECT  65.904 0 65.928 0.084 ;
    END
  END t_d[398]
  PIN t_d[399]
    DIRECTION INPUT ;
    USE SIGNAL ;
    PORT
      LAYER M5 ;
        RECT  66 0 66.024 0.084 ;
    END
  END t_d[399]
  PIN t_d[39]
    DIRECTION INPUT ;
    USE SIGNAL ;
    PORT
      LAYER M5 ;
        RECT  52.176 0 52.2 0.084 ;
    END
  END t_d[39]
  PIN t_d[3]
    DIRECTION INPUT ;
    USE SIGNAL ;
    PORT
      LAYER M5 ;
        RECT  39.504 0 39.528 0.084 ;
    END
  END t_d[3]
  PIN t_d[400]
    DIRECTION INPUT ;
    USE SIGNAL ;
    PORT
      LAYER M5 ;
        RECT  66.096 0 66.12 0.084 ;
    END
  END t_d[400]
  PIN t_d[401]
    DIRECTION INPUT ;
    USE SIGNAL ;
    PORT
      LAYER M5 ;
        RECT  66.192 0 66.216 0.084 ;
    END
  END t_d[401]
  PIN t_d[402]
    DIRECTION INPUT ;
    USE SIGNAL ;
    PORT
      LAYER M5 ;
        RECT  66.288 0 66.312 0.084 ;
    END
  END t_d[402]
  PIN t_d[403]
    DIRECTION INPUT ;
    USE SIGNAL ;
    PORT
      LAYER M5 ;
        RECT  66.384 0 66.408 0.084 ;
    END
  END t_d[403]
  PIN t_d[404]
    DIRECTION INPUT ;
    USE SIGNAL ;
    PORT
      LAYER M5 ;
        RECT  66.48 0 66.504 0.084 ;
    END
  END t_d[404]
  PIN t_d[405]
    DIRECTION INPUT ;
    USE SIGNAL ;
    PORT
      LAYER M5 ;
        RECT  66.576 0 66.6 0.084 ;
    END
  END t_d[405]
  PIN t_d[406]
    DIRECTION INPUT ;
    USE SIGNAL ;
    PORT
      LAYER M5 ;
        RECT  66.672 0 66.696 0.084 ;
    END
  END t_d[406]
  PIN t_d[407]
    DIRECTION INPUT ;
    USE SIGNAL ;
    PORT
      LAYER M5 ;
        RECT  66.768 0 66.792 0.084 ;
    END
  END t_d[407]
  PIN t_d[408]
    DIRECTION INPUT ;
    USE SIGNAL ;
    PORT
      LAYER M5 ;
        RECT  66.864 0 66.888 0.084 ;
    END
  END t_d[408]
  PIN t_d[409]
    DIRECTION INPUT ;
    USE SIGNAL ;
    PORT
      LAYER M5 ;
        RECT  66.96 0 66.984 0.084 ;
    END
  END t_d[409]
  PIN t_d[40]
    DIRECTION INPUT ;
    USE SIGNAL ;
    PORT
      LAYER M5 ;
        RECT  52.272 0 52.296 0.084 ;
    END
  END t_d[40]
  PIN t_d[410]
    DIRECTION INPUT ;
    USE SIGNAL ;
    PORT
      LAYER M5 ;
        RECT  67.056 0 67.08 0.084 ;
    END
  END t_d[410]
  PIN t_d[411]
    DIRECTION INPUT ;
    USE SIGNAL ;
    PORT
      LAYER M5 ;
        RECT  67.152 0 67.176 0.084 ;
    END
  END t_d[411]
  PIN t_d[412]
    DIRECTION INPUT ;
    USE SIGNAL ;
    PORT
      LAYER M5 ;
        RECT  67.248 0 67.272 0.084 ;
    END
  END t_d[412]
  PIN t_d[413]
    DIRECTION INPUT ;
    USE SIGNAL ;
    PORT
      LAYER M5 ;
        RECT  67.344 0 67.368 0.084 ;
    END
  END t_d[413]
  PIN t_d[414]
    DIRECTION INPUT ;
    USE SIGNAL ;
    PORT
      LAYER M5 ;
        RECT  67.44 0 67.464 0.084 ;
    END
  END t_d[414]
  PIN t_d[415]
    DIRECTION INPUT ;
    USE SIGNAL ;
    PORT
      LAYER M5 ;
        RECT  61.392 0 61.416 0.084 ;
    END
  END t_d[415]
  PIN t_d[416]
    DIRECTION INPUT ;
    USE SIGNAL ;
    PORT
      LAYER M5 ;
        RECT  61.488 0 61.512 0.084 ;
    END
  END t_d[416]
  PIN t_d[417]
    DIRECTION INPUT ;
    USE SIGNAL ;
    PORT
      LAYER M5 ;
        RECT  61.584 0 61.608 0.084 ;
    END
  END t_d[417]
  PIN t_d[418]
    DIRECTION INPUT ;
    USE SIGNAL ;
    PORT
      LAYER M5 ;
        RECT  61.68 0 61.704 0.084 ;
    END
  END t_d[418]
  PIN t_d[419]
    DIRECTION INPUT ;
    USE SIGNAL ;
    PORT
      LAYER M5 ;
        RECT  61.776 0 61.8 0.084 ;
    END
  END t_d[419]
  PIN t_d[41]
    DIRECTION INPUT ;
    USE SIGNAL ;
    PORT
      LAYER M5 ;
        RECT  52.368 0 52.392 0.084 ;
    END
  END t_d[41]
  PIN t_d[420]
    DIRECTION INPUT ;
    USE SIGNAL ;
    PORT
      LAYER M5 ;
        RECT  61.872 0 61.896 0.084 ;
    END
  END t_d[420]
  PIN t_d[421]
    DIRECTION INPUT ;
    USE SIGNAL ;
    PORT
      LAYER M5 ;
        RECT  61.968 0 61.992 0.084 ;
    END
  END t_d[421]
  PIN t_d[422]
    DIRECTION INPUT ;
    USE SIGNAL ;
    PORT
      LAYER M5 ;
        RECT  62.064 0 62.088 0.084 ;
    END
  END t_d[422]
  PIN t_d[423]
    DIRECTION INPUT ;
    USE SIGNAL ;
    PORT
      LAYER M5 ;
        RECT  62.16 0 62.184 0.084 ;
    END
  END t_d[423]
  PIN t_d[424]
    DIRECTION INPUT ;
    USE SIGNAL ;
    PORT
      LAYER M5 ;
        RECT  62.256 0 62.28 0.084 ;
    END
  END t_d[424]
  PIN t_d[425]
    DIRECTION INPUT ;
    USE SIGNAL ;
    PORT
      LAYER M5 ;
        RECT  62.352 0 62.376 0.084 ;
    END
  END t_d[425]
  PIN t_d[426]
    DIRECTION INPUT ;
    USE SIGNAL ;
    PORT
      LAYER M5 ;
        RECT  62.448 0 62.472 0.084 ;
    END
  END t_d[426]
  PIN t_d[427]
    DIRECTION INPUT ;
    USE SIGNAL ;
    PORT
      LAYER M5 ;
        RECT  62.544 0 62.568 0.084 ;
    END
  END t_d[427]
  PIN t_d[428]
    DIRECTION INPUT ;
    USE SIGNAL ;
    PORT
      LAYER M5 ;
        RECT  62.64 0 62.664 0.084 ;
    END
  END t_d[428]
  PIN t_d[429]
    DIRECTION INPUT ;
    USE SIGNAL ;
    PORT
      LAYER M5 ;
        RECT  62.736 0 62.76 0.084 ;
    END
  END t_d[429]
  PIN t_d[42]
    DIRECTION INPUT ;
    USE SIGNAL ;
    PORT
      LAYER M5 ;
        RECT  52.464 0 52.488 0.084 ;
    END
  END t_d[42]
  PIN t_d[430]
    DIRECTION INPUT ;
    USE SIGNAL ;
    PORT
      LAYER M5 ;
        RECT  62.832 0 62.856 0.084 ;
    END
  END t_d[430]
  PIN t_d[431]
    DIRECTION INPUT ;
    USE SIGNAL ;
    PORT
      LAYER M5 ;
        RECT  62.928 0 62.952 0.084 ;
    END
  END t_d[431]
  PIN t_d[432]
    DIRECTION INPUT ;
    USE SIGNAL ;
    PORT
      LAYER M5 ;
        RECT  63.024 0 63.048 0.084 ;
    END
  END t_d[432]
  PIN t_d[433]
    DIRECTION INPUT ;
    USE SIGNAL ;
    PORT
      LAYER M5 ;
        RECT  63.12 0 63.144 0.084 ;
    END
  END t_d[433]
  PIN t_d[434]
    DIRECTION INPUT ;
    USE SIGNAL ;
    PORT
      LAYER M5 ;
        RECT  63.216 0 63.24 0.084 ;
    END
  END t_d[434]
  PIN t_d[435]
    DIRECTION INPUT ;
    USE SIGNAL ;
    PORT
      LAYER M5 ;
        RECT  63.312 0 63.336 0.084 ;
    END
  END t_d[435]
  PIN t_d[436]
    DIRECTION INPUT ;
    USE SIGNAL ;
    PORT
      LAYER M5 ;
        RECT  63.408 0 63.432 0.084 ;
    END
  END t_d[436]
  PIN t_d[437]
    DIRECTION INPUT ;
    USE SIGNAL ;
    PORT
      LAYER M5 ;
        RECT  63.504 0 63.528 0.084 ;
    END
  END t_d[437]
  PIN t_d[438]
    DIRECTION INPUT ;
    USE SIGNAL ;
    PORT
      LAYER M5 ;
        RECT  63.6 0 63.624 0.084 ;
    END
  END t_d[438]
  PIN t_d[439]
    DIRECTION INPUT ;
    USE SIGNAL ;
    PORT
      LAYER M5 ;
        RECT  63.696 0 63.72 0.084 ;
    END
  END t_d[439]
  PIN t_d[43]
    DIRECTION INPUT ;
    USE SIGNAL ;
    PORT
      LAYER M5 ;
        RECT  52.56 0 52.584 0.084 ;
    END
  END t_d[43]
  PIN t_d[440]
    DIRECTION INPUT ;
    USE SIGNAL ;
    PORT
      LAYER M5 ;
        RECT  63.792 0 63.816 0.084 ;
    END
  END t_d[440]
  PIN t_d[441]
    DIRECTION INPUT ;
    USE SIGNAL ;
    PORT
      LAYER M5 ;
        RECT  63.888 0 63.912 0.084 ;
    END
  END t_d[441]
  PIN t_d[442]
    DIRECTION INPUT ;
    USE SIGNAL ;
    PORT
      LAYER M5 ;
        RECT  63.984 0 64.008 0.084 ;
    END
  END t_d[442]
  PIN t_d[443]
    DIRECTION INPUT ;
    USE SIGNAL ;
    PORT
      LAYER M5 ;
        RECT  64.08 0 64.104 0.084 ;
    END
  END t_d[443]
  PIN t_d[444]
    DIRECTION INPUT ;
    USE SIGNAL ;
    PORT
      LAYER M5 ;
        RECT  64.176 0 64.2 0.084 ;
    END
  END t_d[444]
  PIN t_d[445]
    DIRECTION INPUT ;
    USE SIGNAL ;
    PORT
      LAYER M5 ;
        RECT  64.272 0 64.296 0.084 ;
    END
  END t_d[445]
  PIN t_d[446]
    DIRECTION INPUT ;
    USE SIGNAL ;
    PORT
      LAYER M5 ;
        RECT  64.368 0 64.392 0.084 ;
    END
  END t_d[446]
  PIN t_d[447]
    DIRECTION INPUT ;
    USE SIGNAL ;
    PORT
      LAYER M5 ;
        RECT  58.32 0 58.344 0.084 ;
    END
  END t_d[447]
  PIN t_d[448]
    DIRECTION INPUT ;
    USE SIGNAL ;
    PORT
      LAYER M5 ;
        RECT  58.416 0 58.44 0.084 ;
    END
  END t_d[448]
  PIN t_d[449]
    DIRECTION INPUT ;
    USE SIGNAL ;
    PORT
      LAYER M5 ;
        RECT  58.512 0 58.536 0.084 ;
    END
  END t_d[449]
  PIN t_d[44]
    DIRECTION INPUT ;
    USE SIGNAL ;
    PORT
      LAYER M5 ;
        RECT  52.656 0 52.68 0.084 ;
    END
  END t_d[44]
  PIN t_d[450]
    DIRECTION INPUT ;
    USE SIGNAL ;
    PORT
      LAYER M5 ;
        RECT  58.608 0 58.632 0.084 ;
    END
  END t_d[450]
  PIN t_d[451]
    DIRECTION INPUT ;
    USE SIGNAL ;
    PORT
      LAYER M5 ;
        RECT  58.704 0 58.728 0.084 ;
    END
  END t_d[451]
  PIN t_d[452]
    DIRECTION INPUT ;
    USE SIGNAL ;
    PORT
      LAYER M5 ;
        RECT  58.8 0 58.824 0.084 ;
    END
  END t_d[452]
  PIN t_d[453]
    DIRECTION INPUT ;
    USE SIGNAL ;
    PORT
      LAYER M5 ;
        RECT  58.896 0 58.92 0.084 ;
    END
  END t_d[453]
  PIN t_d[454]
    DIRECTION INPUT ;
    USE SIGNAL ;
    PORT
      LAYER M5 ;
        RECT  58.992 0 59.016 0.084 ;
    END
  END t_d[454]
  PIN t_d[455]
    DIRECTION INPUT ;
    USE SIGNAL ;
    PORT
      LAYER M5 ;
        RECT  59.088 0 59.112 0.084 ;
    END
  END t_d[455]
  PIN t_d[456]
    DIRECTION INPUT ;
    USE SIGNAL ;
    PORT
      LAYER M5 ;
        RECT  59.184 0 59.208 0.084 ;
    END
  END t_d[456]
  PIN t_d[457]
    DIRECTION INPUT ;
    USE SIGNAL ;
    PORT
      LAYER M5 ;
        RECT  59.28 0 59.304 0.084 ;
    END
  END t_d[457]
  PIN t_d[458]
    DIRECTION INPUT ;
    USE SIGNAL ;
    PORT
      LAYER M5 ;
        RECT  59.376 0 59.4 0.084 ;
    END
  END t_d[458]
  PIN t_d[459]
    DIRECTION INPUT ;
    USE SIGNAL ;
    PORT
      LAYER M5 ;
        RECT  59.472 0 59.496 0.084 ;
    END
  END t_d[459]
  PIN t_d[45]
    DIRECTION INPUT ;
    USE SIGNAL ;
    PORT
      LAYER M5 ;
        RECT  52.752 0 52.776 0.084 ;
    END
  END t_d[45]
  PIN t_d[460]
    DIRECTION INPUT ;
    USE SIGNAL ;
    PORT
      LAYER M5 ;
        RECT  59.568 0 59.592 0.084 ;
    END
  END t_d[460]
  PIN t_d[461]
    DIRECTION INPUT ;
    USE SIGNAL ;
    PORT
      LAYER M5 ;
        RECT  59.664 0 59.688 0.084 ;
    END
  END t_d[461]
  PIN t_d[462]
    DIRECTION INPUT ;
    USE SIGNAL ;
    PORT
      LAYER M5 ;
        RECT  59.76 0 59.784 0.084 ;
    END
  END t_d[462]
  PIN t_d[463]
    DIRECTION INPUT ;
    USE SIGNAL ;
    PORT
      LAYER M5 ;
        RECT  59.856 0 59.88 0.084 ;
    END
  END t_d[463]
  PIN t_d[464]
    DIRECTION INPUT ;
    USE SIGNAL ;
    PORT
      LAYER M5 ;
        RECT  59.952 0 59.976 0.084 ;
    END
  END t_d[464]
  PIN t_d[465]
    DIRECTION INPUT ;
    USE SIGNAL ;
    PORT
      LAYER M5 ;
        RECT  60.048 0 60.072 0.084 ;
    END
  END t_d[465]
  PIN t_d[466]
    DIRECTION INPUT ;
    USE SIGNAL ;
    PORT
      LAYER M5 ;
        RECT  60.144 0 60.168 0.084 ;
    END
  END t_d[466]
  PIN t_d[467]
    DIRECTION INPUT ;
    USE SIGNAL ;
    PORT
      LAYER M5 ;
        RECT  60.24 0 60.264 0.084 ;
    END
  END t_d[467]
  PIN t_d[468]
    DIRECTION INPUT ;
    USE SIGNAL ;
    PORT
      LAYER M5 ;
        RECT  60.336 0 60.36 0.084 ;
    END
  END t_d[468]
  PIN t_d[469]
    DIRECTION INPUT ;
    USE SIGNAL ;
    PORT
      LAYER M5 ;
        RECT  60.432 0 60.456 0.084 ;
    END
  END t_d[469]
  PIN t_d[46]
    DIRECTION INPUT ;
    USE SIGNAL ;
    PORT
      LAYER M5 ;
        RECT  52.848 0 52.872 0.084 ;
    END
  END t_d[46]
  PIN t_d[470]
    DIRECTION INPUT ;
    USE SIGNAL ;
    PORT
      LAYER M5 ;
        RECT  60.528 0 60.552 0.084 ;
    END
  END t_d[470]
  PIN t_d[471]
    DIRECTION INPUT ;
    USE SIGNAL ;
    PORT
      LAYER M5 ;
        RECT  60.624 0 60.648 0.084 ;
    END
  END t_d[471]
  PIN t_d[472]
    DIRECTION INPUT ;
    USE SIGNAL ;
    PORT
      LAYER M5 ;
        RECT  60.72 0 60.744 0.084 ;
    END
  END t_d[472]
  PIN t_d[473]
    DIRECTION INPUT ;
    USE SIGNAL ;
    PORT
      LAYER M5 ;
        RECT  60.816 0 60.84 0.084 ;
    END
  END t_d[473]
  PIN t_d[474]
    DIRECTION INPUT ;
    USE SIGNAL ;
    PORT
      LAYER M5 ;
        RECT  60.912 0 60.936 0.084 ;
    END
  END t_d[474]
  PIN t_d[475]
    DIRECTION INPUT ;
    USE SIGNAL ;
    PORT
      LAYER M5 ;
        RECT  61.008 0 61.032 0.084 ;
    END
  END t_d[475]
  PIN t_d[476]
    DIRECTION INPUT ;
    USE SIGNAL ;
    PORT
      LAYER M5 ;
        RECT  61.104 0 61.128 0.084 ;
    END
  END t_d[476]
  PIN t_d[477]
    DIRECTION INPUT ;
    USE SIGNAL ;
    PORT
      LAYER M5 ;
        RECT  61.2 0 61.224 0.084 ;
    END
  END t_d[477]
  PIN t_d[478]
    DIRECTION INPUT ;
    USE SIGNAL ;
    PORT
      LAYER M5 ;
        RECT  61.296 0 61.32 0.084 ;
    END
  END t_d[478]
  PIN t_d[479]
    DIRECTION INPUT ;
    USE SIGNAL ;
    PORT
      LAYER M5 ;
        RECT  16.08 0 16.104 0.084 ;
    END
  END t_d[479]
  PIN t_d[47]
    DIRECTION INPUT ;
    USE SIGNAL ;
    PORT
      LAYER M5 ;
        RECT  52.944 0 52.968 0.084 ;
    END
  END t_d[47]
  PIN t_d[480]
    DIRECTION INPUT ;
    USE SIGNAL ;
    PORT
      LAYER M5 ;
        RECT  16.176 0 16.2 0.084 ;
    END
  END t_d[480]
  PIN t_d[481]
    DIRECTION INPUT ;
    USE SIGNAL ;
    PORT
      LAYER M5 ;
        RECT  16.272 0 16.296 0.084 ;
    END
  END t_d[481]
  PIN t_d[482]
    DIRECTION INPUT ;
    USE SIGNAL ;
    PORT
      LAYER M5 ;
        RECT  16.368 0 16.392 0.084 ;
    END
  END t_d[482]
  PIN t_d[483]
    DIRECTION INPUT ;
    USE SIGNAL ;
    PORT
      LAYER M5 ;
        RECT  16.464 0 16.488 0.084 ;
    END
  END t_d[483]
  PIN t_d[484]
    DIRECTION INPUT ;
    USE SIGNAL ;
    PORT
      LAYER M5 ;
        RECT  16.56 0 16.584 0.084 ;
    END
  END t_d[484]
  PIN t_d[485]
    DIRECTION INPUT ;
    USE SIGNAL ;
    PORT
      LAYER M5 ;
        RECT  16.656 0 16.68 0.084 ;
    END
  END t_d[485]
  PIN t_d[486]
    DIRECTION INPUT ;
    USE SIGNAL ;
    PORT
      LAYER M5 ;
        RECT  16.752 0 16.776 0.084 ;
    END
  END t_d[486]
  PIN t_d[487]
    DIRECTION INPUT ;
    USE SIGNAL ;
    PORT
      LAYER M5 ;
        RECT  16.848 0 16.872 0.084 ;
    END
  END t_d[487]
  PIN t_d[488]
    DIRECTION INPUT ;
    USE SIGNAL ;
    PORT
      LAYER M5 ;
        RECT  16.944 0 16.968 0.084 ;
    END
  END t_d[488]
  PIN t_d[489]
    DIRECTION INPUT ;
    USE SIGNAL ;
    PORT
      LAYER M5 ;
        RECT  17.04 0 17.064 0.084 ;
    END
  END t_d[489]
  PIN t_d[48]
    DIRECTION INPUT ;
    USE SIGNAL ;
    PORT
      LAYER M5 ;
        RECT  53.04 0 53.064 0.084 ;
    END
  END t_d[48]
  PIN t_d[490]
    DIRECTION INPUT ;
    USE SIGNAL ;
    PORT
      LAYER M5 ;
        RECT  17.136 0 17.16 0.084 ;
    END
  END t_d[490]
  PIN t_d[491]
    DIRECTION INPUT ;
    USE SIGNAL ;
    PORT
      LAYER M5 ;
        RECT  17.232 0 17.256 0.084 ;
    END
  END t_d[491]
  PIN t_d[492]
    DIRECTION INPUT ;
    USE SIGNAL ;
    PORT
      LAYER M5 ;
        RECT  17.328 0 17.352 0.084 ;
    END
  END t_d[492]
  PIN t_d[493]
    DIRECTION INPUT ;
    USE SIGNAL ;
    PORT
      LAYER M5 ;
        RECT  17.424 0 17.448 0.084 ;
    END
  END t_d[493]
  PIN t_d[494]
    DIRECTION INPUT ;
    USE SIGNAL ;
    PORT
      LAYER M5 ;
        RECT  17.52 0 17.544 0.084 ;
    END
  END t_d[494]
  PIN t_d[495]
    DIRECTION INPUT ;
    USE SIGNAL ;
    PORT
      LAYER M5 ;
        RECT  17.616 0 17.64 0.084 ;
    END
  END t_d[495]
  PIN t_d[496]
    DIRECTION INPUT ;
    USE SIGNAL ;
    PORT
      LAYER M5 ;
        RECT  17.712 0 17.736 0.084 ;
    END
  END t_d[496]
  PIN t_d[497]
    DIRECTION INPUT ;
    USE SIGNAL ;
    PORT
      LAYER M5 ;
        RECT  17.808 0 17.832 0.084 ;
    END
  END t_d[497]
  PIN t_d[498]
    DIRECTION INPUT ;
    USE SIGNAL ;
    PORT
      LAYER M5 ;
        RECT  17.904 0 17.928 0.084 ;
    END
  END t_d[498]
  PIN t_d[499]
    DIRECTION INPUT ;
    USE SIGNAL ;
    PORT
      LAYER M5 ;
        RECT  18 0 18.024 0.084 ;
    END
  END t_d[499]
  PIN t_d[49]
    DIRECTION INPUT ;
    USE SIGNAL ;
    PORT
      LAYER M5 ;
        RECT  53.136 0 53.16 0.084 ;
    END
  END t_d[49]
  PIN t_d[4]
    DIRECTION INPUT ;
    USE SIGNAL ;
    PORT
      LAYER M5 ;
        RECT  39.6 0 39.624 0.084 ;
    END
  END t_d[4]
  PIN t_d[500]
    DIRECTION INPUT ;
    USE SIGNAL ;
    PORT
      LAYER M5 ;
        RECT  18.096 0 18.12 0.084 ;
    END
  END t_d[500]
  PIN t_d[501]
    DIRECTION INPUT ;
    USE SIGNAL ;
    PORT
      LAYER M5 ;
        RECT  18.192 0 18.216 0.084 ;
    END
  END t_d[501]
  PIN t_d[502]
    DIRECTION INPUT ;
    USE SIGNAL ;
    PORT
      LAYER M5 ;
        RECT  18.288 0 18.312 0.084 ;
    END
  END t_d[502]
  PIN t_d[503]
    DIRECTION INPUT ;
    USE SIGNAL ;
    PORT
      LAYER M5 ;
        RECT  18.384 0 18.408 0.084 ;
    END
  END t_d[503]
  PIN t_d[504]
    DIRECTION INPUT ;
    USE SIGNAL ;
    PORT
      LAYER M5 ;
        RECT  18.48 0 18.504 0.084 ;
    END
  END t_d[504]
  PIN t_d[505]
    DIRECTION INPUT ;
    USE SIGNAL ;
    PORT
      LAYER M5 ;
        RECT  18.576 0 18.6 0.084 ;
    END
  END t_d[505]
  PIN t_d[506]
    DIRECTION INPUT ;
    USE SIGNAL ;
    PORT
      LAYER M5 ;
        RECT  18.672 0 18.696 0.084 ;
    END
  END t_d[506]
  PIN t_d[507]
    DIRECTION INPUT ;
    USE SIGNAL ;
    PORT
      LAYER M5 ;
        RECT  18.768 0 18.792 0.084 ;
    END
  END t_d[507]
  PIN t_d[508]
    DIRECTION INPUT ;
    USE SIGNAL ;
    PORT
      LAYER M5 ;
        RECT  18.864 0 18.888 0.084 ;
    END
  END t_d[508]
  PIN t_d[509]
    DIRECTION INPUT ;
    USE SIGNAL ;
    PORT
      LAYER M5 ;
        RECT  18.96 0 18.984 0.084 ;
    END
  END t_d[509]
  PIN t_d[50]
    DIRECTION INPUT ;
    USE SIGNAL ;
    PORT
      LAYER M5 ;
        RECT  53.232 0 53.256 0.084 ;
    END
  END t_d[50]
  PIN t_d[510]
    DIRECTION INPUT ;
    USE SIGNAL ;
    PORT
      LAYER M5 ;
        RECT  19.056 0 19.08 0.084 ;
    END
  END t_d[510]
  PIN t_d[511]
    DIRECTION INPUT ;
    USE SIGNAL ;
    PORT
      LAYER M5 ;
        RECT  67.536 0 67.56 0.084 ;
    END
  END t_d[511]
  PIN t_d[512]
    DIRECTION INPUT ;
    USE SIGNAL ;
    PORT
      LAYER M5 ;
        RECT  67.632 0 67.656 0.084 ;
    END
  END t_d[512]
  PIN t_d[513]
    DIRECTION INPUT ;
    USE SIGNAL ;
    PORT
      LAYER M5 ;
        RECT  67.728 0 67.752 0.084 ;
    END
  END t_d[513]
  PIN t_d[514]
    DIRECTION INPUT ;
    USE SIGNAL ;
    PORT
      LAYER M5 ;
        RECT  67.824 0 67.848 0.084 ;
    END
  END t_d[514]
  PIN t_d[515]
    DIRECTION INPUT ;
    USE SIGNAL ;
    PORT
      LAYER M5 ;
        RECT  67.92 0 67.944 0.084 ;
    END
  END t_d[515]
  PIN t_d[516]
    DIRECTION INPUT ;
    USE SIGNAL ;
    PORT
      LAYER M5 ;
        RECT  68.016 0 68.04 0.084 ;
    END
  END t_d[516]
  PIN t_d[517]
    DIRECTION INPUT ;
    USE SIGNAL ;
    PORT
      LAYER M5 ;
        RECT  68.112 0 68.136 0.084 ;
    END
  END t_d[517]
  PIN t_d[518]
    DIRECTION INPUT ;
    USE SIGNAL ;
    PORT
      LAYER M5 ;
        RECT  68.208 0 68.232 0.084 ;
    END
  END t_d[518]
  PIN t_d[519]
    DIRECTION INPUT ;
    USE SIGNAL ;
    PORT
      LAYER M5 ;
        RECT  68.304 0 68.328 0.084 ;
    END
  END t_d[519]
  PIN t_d[51]
    DIRECTION INPUT ;
    USE SIGNAL ;
    PORT
      LAYER M5 ;
        RECT  53.328 0 53.352 0.084 ;
    END
  END t_d[51]
  PIN t_d[520]
    DIRECTION INPUT ;
    USE SIGNAL ;
    PORT
      LAYER M5 ;
        RECT  68.4 0 68.424 0.084 ;
    END
  END t_d[520]
  PIN t_d[521]
    DIRECTION INPUT ;
    USE SIGNAL ;
    PORT
      LAYER M5 ;
        RECT  68.496 0 68.52 0.084 ;
    END
  END t_d[521]
  PIN t_d[522]
    DIRECTION INPUT ;
    USE SIGNAL ;
    PORT
      LAYER M5 ;
        RECT  68.592 0 68.616 0.084 ;
    END
  END t_d[522]
  PIN t_d[523]
    DIRECTION INPUT ;
    USE SIGNAL ;
    PORT
      LAYER M5 ;
        RECT  68.688 0 68.712 0.084 ;
    END
  END t_d[523]
  PIN t_d[524]
    DIRECTION INPUT ;
    USE SIGNAL ;
    PORT
      LAYER M5 ;
        RECT  68.784 0 68.808 0.084 ;
    END
  END t_d[524]
  PIN t_d[525]
    DIRECTION INPUT ;
    USE SIGNAL ;
    PORT
      LAYER M5 ;
        RECT  68.88 0 68.904 0.084 ;
    END
  END t_d[525]
  PIN t_d[526]
    DIRECTION INPUT ;
    USE SIGNAL ;
    PORT
      LAYER M5 ;
        RECT  68.976 0 69 0.084 ;
    END
  END t_d[526]
  PIN t_d[527]
    DIRECTION INPUT ;
    USE SIGNAL ;
    PORT
      LAYER M5 ;
        RECT  69.072 0 69.096 0.084 ;
    END
  END t_d[527]
  PIN t_d[52]
    DIRECTION INPUT ;
    USE SIGNAL ;
    PORT
      LAYER M5 ;
        RECT  53.424 0 53.448 0.084 ;
    END
  END t_d[52]
  PIN t_d[53]
    DIRECTION INPUT ;
    USE SIGNAL ;
    PORT
      LAYER M5 ;
        RECT  53.52 0 53.544 0.084 ;
    END
  END t_d[53]
  PIN t_d[54]
    DIRECTION INPUT ;
    USE SIGNAL ;
    PORT
      LAYER M5 ;
        RECT  53.616 0 53.64 0.084 ;
    END
  END t_d[54]
  PIN t_d[55]
    DIRECTION INPUT ;
    USE SIGNAL ;
    PORT
      LAYER M5 ;
        RECT  53.712 0 53.736 0.084 ;
    END
  END t_d[55]
  PIN t_d[56]
    DIRECTION INPUT ;
    USE SIGNAL ;
    PORT
      LAYER M5 ;
        RECT  53.808 0 53.832 0.084 ;
    END
  END t_d[56]
  PIN t_d[57]
    DIRECTION INPUT ;
    USE SIGNAL ;
    PORT
      LAYER M5 ;
        RECT  53.904 0 53.928 0.084 ;
    END
  END t_d[57]
  PIN t_d[58]
    DIRECTION INPUT ;
    USE SIGNAL ;
    PORT
      LAYER M5 ;
        RECT  54 0 54.024 0.084 ;
    END
  END t_d[58]
  PIN t_d[59]
    DIRECTION INPUT ;
    USE SIGNAL ;
    PORT
      LAYER M5 ;
        RECT  54.096 0 54.12 0.084 ;
    END
  END t_d[59]
  PIN t_d[5]
    DIRECTION INPUT ;
    USE SIGNAL ;
    PORT
      LAYER M5 ;
        RECT  39.696 0 39.72 0.084 ;
    END
  END t_d[5]
  PIN t_d[60]
    DIRECTION INPUT ;
    USE SIGNAL ;
    PORT
      LAYER M5 ;
        RECT  54.192 0 54.216 0.084 ;
    END
  END t_d[60]
  PIN t_d[61]
    DIRECTION INPUT ;
    USE SIGNAL ;
    PORT
      LAYER M5 ;
        RECT  54.288 0 54.312 0.084 ;
    END
  END t_d[61]
  PIN t_d[62]
    DIRECTION INPUT ;
    USE SIGNAL ;
    PORT
      LAYER M5 ;
        RECT  54.384 0 54.408 0.084 ;
    END
  END t_d[62]
  PIN t_d[63]
    DIRECTION INPUT ;
    USE SIGNAL ;
    PORT
      LAYER M5 ;
        RECT  42.192 0 42.216 0.084 ;
    END
  END t_d[63]
  PIN t_d[64]
    DIRECTION INPUT ;
    USE SIGNAL ;
    PORT
      LAYER M5 ;
        RECT  42.288 0 42.312 0.084 ;
    END
  END t_d[64]
  PIN t_d[65]
    DIRECTION INPUT ;
    USE SIGNAL ;
    PORT
      LAYER M5 ;
        RECT  42.384 0 42.408 0.084 ;
    END
  END t_d[65]
  PIN t_d[66]
    DIRECTION INPUT ;
    USE SIGNAL ;
    PORT
      LAYER M5 ;
        RECT  42.48 0 42.504 0.084 ;
    END
  END t_d[66]
  PIN t_d[67]
    DIRECTION INPUT ;
    USE SIGNAL ;
    PORT
      LAYER M5 ;
        RECT  42.576 0 42.6 0.084 ;
    END
  END t_d[67]
  PIN t_d[68]
    DIRECTION INPUT ;
    USE SIGNAL ;
    PORT
      LAYER M5 ;
        RECT  42.672 0 42.696 0.084 ;
    END
  END t_d[68]
  PIN t_d[69]
    DIRECTION INPUT ;
    USE SIGNAL ;
    PORT
      LAYER M5 ;
        RECT  42.768 0 42.792 0.084 ;
    END
  END t_d[69]
  PIN t_d[6]
    DIRECTION INPUT ;
    USE SIGNAL ;
    PORT
      LAYER M5 ;
        RECT  39.792 0 39.816 0.084 ;
    END
  END t_d[6]
  PIN t_d[70]
    DIRECTION INPUT ;
    USE SIGNAL ;
    PORT
      LAYER M5 ;
        RECT  42.864 0 42.888 0.084 ;
    END
  END t_d[70]
  PIN t_d[71]
    DIRECTION INPUT ;
    USE SIGNAL ;
    PORT
      LAYER M5 ;
        RECT  42.96 0 42.984 0.084 ;
    END
  END t_d[71]
  PIN t_d[72]
    DIRECTION INPUT ;
    USE SIGNAL ;
    PORT
      LAYER M5 ;
        RECT  43.056 0 43.08 0.084 ;
    END
  END t_d[72]
  PIN t_d[73]
    DIRECTION INPUT ;
    USE SIGNAL ;
    PORT
      LAYER M5 ;
        RECT  43.152 0 43.176 0.084 ;
    END
  END t_d[73]
  PIN t_d[74]
    DIRECTION INPUT ;
    USE SIGNAL ;
    PORT
      LAYER M5 ;
        RECT  43.248 0 43.272 0.084 ;
    END
  END t_d[74]
  PIN t_d[75]
    DIRECTION INPUT ;
    USE SIGNAL ;
    PORT
      LAYER M5 ;
        RECT  43.344 0 43.368 0.084 ;
    END
  END t_d[75]
  PIN t_d[76]
    DIRECTION INPUT ;
    USE SIGNAL ;
    PORT
      LAYER M5 ;
        RECT  43.44 0 43.464 0.084 ;
    END
  END t_d[76]
  PIN t_d[77]
    DIRECTION INPUT ;
    USE SIGNAL ;
    PORT
      LAYER M5 ;
        RECT  43.536 0 43.56 0.084 ;
    END
  END t_d[77]
  PIN t_d[78]
    DIRECTION INPUT ;
    USE SIGNAL ;
    PORT
      LAYER M5 ;
        RECT  43.632 0 43.656 0.084 ;
    END
  END t_d[78]
  PIN t_d[79]
    DIRECTION INPUT ;
    USE SIGNAL ;
    PORT
      LAYER M5 ;
        RECT  43.728 0 43.752 0.084 ;
    END
  END t_d[79]
  PIN t_d[7]
    DIRECTION INPUT ;
    USE SIGNAL ;
    PORT
      LAYER M5 ;
        RECT  39.888 0 39.912 0.084 ;
    END
  END t_d[7]
  PIN t_d[80]
    DIRECTION INPUT ;
    USE SIGNAL ;
    PORT
      LAYER M5 ;
        RECT  43.824 0 43.848 0.084 ;
    END
  END t_d[80]
  PIN t_d[81]
    DIRECTION INPUT ;
    USE SIGNAL ;
    PORT
      LAYER M5 ;
        RECT  43.92 0 43.944 0.084 ;
    END
  END t_d[81]
  PIN t_d[82]
    DIRECTION INPUT ;
    USE SIGNAL ;
    PORT
      LAYER M5 ;
        RECT  44.016 0 44.04 0.084 ;
    END
  END t_d[82]
  PIN t_d[83]
    DIRECTION INPUT ;
    USE SIGNAL ;
    PORT
      LAYER M5 ;
        RECT  44.112 0 44.136 0.084 ;
    END
  END t_d[83]
  PIN t_d[84]
    DIRECTION INPUT ;
    USE SIGNAL ;
    PORT
      LAYER M5 ;
        RECT  44.208 0 44.232 0.084 ;
    END
  END t_d[84]
  PIN t_d[85]
    DIRECTION INPUT ;
    USE SIGNAL ;
    PORT
      LAYER M5 ;
        RECT  44.304 0 44.328 0.084 ;
    END
  END t_d[85]
  PIN t_d[86]
    DIRECTION INPUT ;
    USE SIGNAL ;
    PORT
      LAYER M5 ;
        RECT  44.4 0 44.424 0.084 ;
    END
  END t_d[86]
  PIN t_d[87]
    DIRECTION INPUT ;
    USE SIGNAL ;
    PORT
      LAYER M5 ;
        RECT  44.496 0 44.52 0.084 ;
    END
  END t_d[87]
  PIN t_d[88]
    DIRECTION INPUT ;
    USE SIGNAL ;
    PORT
      LAYER M5 ;
        RECT  44.592 0 44.616 0.084 ;
    END
  END t_d[88]
  PIN t_d[89]
    DIRECTION INPUT ;
    USE SIGNAL ;
    PORT
      LAYER M5 ;
        RECT  44.688 0 44.712 0.084 ;
    END
  END t_d[89]
  PIN t_d[8]
    DIRECTION INPUT ;
    USE SIGNAL ;
    PORT
      LAYER M5 ;
        RECT  39.984 0 40.008 0.084 ;
    END
  END t_d[8]
  PIN t_d[90]
    DIRECTION INPUT ;
    USE SIGNAL ;
    PORT
      LAYER M5 ;
        RECT  44.784 0 44.808 0.084 ;
    END
  END t_d[90]
  PIN t_d[91]
    DIRECTION INPUT ;
    USE SIGNAL ;
    PORT
      LAYER M5 ;
        RECT  44.88 0 44.904 0.084 ;
    END
  END t_d[91]
  PIN t_d[92]
    DIRECTION INPUT ;
    USE SIGNAL ;
    PORT
      LAYER M5 ;
        RECT  44.976 0 45 0.084 ;
    END
  END t_d[92]
  PIN t_d[93]
    DIRECTION INPUT ;
    USE SIGNAL ;
    PORT
      LAYER M5 ;
        RECT  45.072 0 45.096 0.084 ;
    END
  END t_d[93]
  PIN t_d[94]
    DIRECTION INPUT ;
    USE SIGNAL ;
    PORT
      LAYER M5 ;
        RECT  45.168 0 45.192 0.084 ;
    END
  END t_d[94]
  PIN t_d[95]
    DIRECTION INPUT ;
    USE SIGNAL ;
    PORT
      LAYER M5 ;
        RECT  29.136 0 29.16 0.084 ;
    END
  END t_d[95]
  PIN t_d[96]
    DIRECTION INPUT ;
    USE SIGNAL ;
    PORT
      LAYER M5 ;
        RECT  29.232 0 29.256 0.084 ;
    END
  END t_d[96]
  PIN t_d[97]
    DIRECTION INPUT ;
    USE SIGNAL ;
    PORT
      LAYER M5 ;
        RECT  29.328 0 29.352 0.084 ;
    END
  END t_d[97]
  PIN t_d[98]
    DIRECTION INPUT ;
    USE SIGNAL ;
    PORT
      LAYER M5 ;
        RECT  29.424 0 29.448 0.084 ;
    END
  END t_d[98]
  PIN t_d[99]
    DIRECTION INPUT ;
    USE SIGNAL ;
    PORT
      LAYER M5 ;
        RECT  29.52 0 29.544 0.084 ;
    END
  END t_d[99]
  PIN t_d[9]
    DIRECTION INPUT ;
    USE SIGNAL ;
    PORT
      LAYER M5 ;
        RECT  40.08 0 40.104 0.084 ;
    END
  END t_d[9]
  PIN t_v
    DIRECTION INPUT ;
    USE SIGNAL ;
    PORT
      LAYER M5 ;
        RECT  69.168 0 69.192 0.084 ;
    END
  END t_v
  PIN tcr_i
    DIRECTION INPUT ;
    USE SIGNAL ;
    PORT
      LAYER M5 ;
        RECT  18.768 25.836 18.792 25.92 ;
    END
  END tcr_i
  PIN VDD
    DIRECTION INOUT ;
    USE POWER ;
    PORT
      LAYER M5 ;
        RECT  83.592 2.151 83.712 23.769 ;
        RECT  78.192 2.151 78.312 23.769 ;
        RECT  72.792 2.151 72.912 23.769 ;
        RECT  67.392 2.151 67.512 23.769 ;
        RECT  61.992 2.151 62.112 23.769 ;
        RECT  56.592 2.151 56.712 23.769 ;
        RECT  51.192 2.151 51.312 23.769 ;
        RECT  45.792 2.151 45.912 23.769 ;
        RECT  40.392 2.151 40.512 23.769 ;
        RECT  34.992 2.151 35.112 23.769 ;
        RECT  29.592 2.151 29.712 23.769 ;
        RECT  24.192 2.151 24.312 23.769 ;
        RECT  18.792 2.151 18.912 23.769 ;
        RECT  13.392 2.151 13.512 23.769 ;
        RECT  7.992 2.151 8.112 23.769 ;
        RECT  2.592 2.151 2.712 23.769 ;
    END
  END VDD
  PIN VSS
    DIRECTION INOUT ;
    USE GROUND ;
    PORT
      LAYER M5 ;
        RECT  83.4 2.137 83.52 23.783 ;
        RECT  78 2.137 78.12 23.783 ;
        RECT  72.6 2.137 72.72 23.783 ;
        RECT  67.2 2.137 67.32 23.783 ;
        RECT  61.8 2.137 61.92 23.783 ;
        RECT  56.4 2.137 56.52 23.783 ;
        RECT  51 2.137 51.12 23.783 ;
        RECT  45.6 2.137 45.72 23.783 ;
        RECT  40.2 2.137 40.32 23.783 ;
        RECT  34.8 2.137 34.92 23.783 ;
        RECT  29.4 2.137 29.52 23.783 ;
        RECT  24 2.137 24.12 23.783 ;
        RECT  18.6 2.137 18.72 23.783 ;
        RECT  13.2 2.137 13.32 23.783 ;
        RECT  7.8 2.137 7.92 23.783 ;
        RECT  2.4 2.137 2.52 23.783 ;
    END
  END VSS
  # OT_OBS_CLOSED layer=M5 d_um=1.536 added=127
  OBS
    LAYER RVTN ;
     RECT  2.16 2.16 84.24 2.295 ;
     RECT  2.16 2.565 84.24 2.835 ;
     RECT  2.16 3.105 84.24 3.375 ;
     RECT  2.16 3.645 84.24 3.915 ;
     RECT  2.16 4.185 84.24 4.455 ;
     RECT  2.16 4.725 84.24 4.995 ;
     RECT  2.16 5.265 84.24 5.535 ;
     RECT  2.16 5.805 84.24 6.075 ;
     RECT  2.16 6.345 84.24 6.615 ;
     RECT  2.16 6.885 84.24 7.155 ;
     RECT  2.16 7.425 84.24 7.695 ;
     RECT  2.16 7.965 84.24 8.235 ;
     RECT  2.16 8.505 84.24 8.775 ;
     RECT  2.16 9.045 84.24 9.315 ;
     RECT  2.16 9.585 84.24 9.855 ;
     RECT  2.16 10.125 84.24 10.395 ;
     RECT  2.16 10.665 84.24 10.935 ;
     RECT  2.16 11.205 84.24 11.475 ;
     RECT  2.16 11.745 84.24 12.015 ;
     RECT  2.16 12.285 84.24 12.555 ;
     RECT  2.16 12.825 84.24 13.095 ;
     RECT  2.16 13.365 84.24 13.635 ;
     RECT  2.16 13.905 84.24 14.175 ;
     RECT  2.16 14.445 84.24 14.715 ;
     RECT  2.16 14.985 84.24 15.255 ;
     RECT  2.16 15.525 84.24 15.795 ;
     RECT  2.16 16.065 84.24 16.335 ;
     RECT  2.16 16.605 84.24 16.875 ;
     RECT  2.16 17.145 84.24 17.415 ;
     RECT  2.16 17.685 84.24 17.955 ;
     RECT  2.16 18.225 84.24 18.495 ;
     RECT  2.16 18.765 84.24 19.035 ;
     RECT  2.16 19.305 84.24 19.575 ;
     RECT  2.16 19.845 84.24 20.115 ;
     RECT  2.16 20.385 84.24 20.655 ;
     RECT  2.16 20.925 84.24 21.195 ;
     RECT  2.16 21.465 84.24 21.735 ;
     RECT  2.16 22.005 84.24 22.275 ;
     RECT  2.16 22.545 84.24 22.815 ;
     RECT  2.16 23.085 84.24 23.355 ;
     RECT  2.16 23.625 84.24 23.76 ;
    LAYER RVTP ;
     RECT  2.16 2.295 84.24 2.565 ;
     RECT  2.16 2.835 84.24 3.105 ;
     RECT  2.16 3.375 84.24 3.645 ;
     RECT  2.16 3.915 84.24 4.185 ;
     RECT  2.16 4.455 84.24 4.725 ;
     RECT  2.16 4.995 84.24 5.265 ;
     RECT  2.16 5.535 84.24 5.805 ;
     RECT  2.16 6.075 84.24 6.345 ;
     RECT  2.16 6.615 84.24 6.885 ;
     RECT  2.16 7.155 84.24 7.425 ;
     RECT  2.16 7.695 84.24 7.965 ;
     RECT  2.16 8.235 84.24 8.505 ;
     RECT  2.16 8.775 84.24 9.045 ;
     RECT  2.16 9.315 84.24 9.585 ;
     RECT  2.16 9.855 84.24 10.125 ;
     RECT  2.16 10.395 84.24 10.665 ;
     RECT  2.16 10.935 84.24 11.205 ;
     RECT  2.16 11.475 84.24 11.745 ;
     RECT  2.16 12.015 84.24 12.285 ;
     RECT  2.16 12.555 84.24 12.825 ;
     RECT  2.16 13.095 84.24 13.365 ;
     RECT  2.16 13.635 84.24 13.905 ;
     RECT  2.16 14.175 84.24 14.445 ;
     RECT  2.16 14.715 84.24 14.985 ;
     RECT  2.16 15.255 84.24 15.525 ;
     RECT  2.16 15.795 84.24 16.065 ;
     RECT  2.16 16.335 84.24 16.605 ;
     RECT  2.16 16.875 84.24 17.145 ;
     RECT  2.16 17.415 84.24 17.685 ;
     RECT  2.16 17.955 84.24 18.225 ;
     RECT  2.16 18.495 84.24 18.765 ;
     RECT  2.16 19.035 84.24 19.305 ;
     RECT  2.16 19.575 84.24 19.845 ;
     RECT  2.16 20.115 84.24 20.385 ;
     RECT  2.16 20.655 84.24 20.925 ;
     RECT  2.16 21.195 84.24 21.465 ;
     RECT  2.16 21.735 84.24 22.005 ;
     RECT  2.16 22.275 84.24 22.545 ;
     RECT  2.16 22.815 84.24 23.085 ;
     RECT  2.16 23.355 84.24 23.625 ;
    LAYER M1 ;
     RECT  2.16 2.151 84.24 23.769 ;
    LAYER M2 ;
     RECT  2.16 2.151 4.711 23.769 ;
     RECT  4.711 2.151 4.963 24.354 ;
     RECT  4.963 2.151 5.575 24.804 ;
     RECT  5.575 2.151 10.939 25.038 ;
     RECT  10.939 2.151 14.855 25.074 ;
     RECT  14.855 2.151 19.967 25.002 ;
     RECT  19.967 2.151 21.119 24.93 ;
     RECT  21.119 2.151 22.603 24.849 ;
     RECT  22.603 2.106 23.279 24.849 ;
     RECT  23.279 2.106 23.891 24.804 ;
     RECT  23.891 2.151 24.691 24.804 ;
     RECT  24.691 2.106 26.267 24.804 ;
     RECT  26.267 24.786 26.303 24.804 ;
     RECT  26.267 2.106 26.599 23.769 ;
     RECT  26.599 2.034 26.635 23.769 ;
     RECT  26.635 1.998 30.091 23.769 ;
     RECT  29.947 1.152 30.155 1.17 ;
     RECT  30.091 1.962 30.227 23.769 ;
     RECT  30.227 1.998 33.583 23.769 ;
     RECT  33.943 1.152 34.043 1.17 ;
     RECT  33.583 1.962 34.583 23.769 ;
     RECT  35.995 1.152 36.239 1.17 ;
     RECT  34.583 1.998 39.127 23.769 ;
     RECT  39.127 1.881 39.343 23.769 ;
     RECT  39.343 1.881 40.091 23.814 ;
     RECT  40.091 1.962 40.703 23.814 ;
     RECT  40.703 1.962 41.063 23.769 ;
     RECT  41.063 1.998 44.275 23.769 ;
     RECT  44.275 1.881 45.931 23.769 ;
     RECT  45.931 1.152 46.139 23.769 ;
     RECT  46.139 1.881 49.055 23.769 ;
     RECT  49.055 1.926 58.091 23.769 ;
     RECT  58.091 1.962 58.739 23.769 ;
     RECT  58.739 1.998 60.403 23.769 ;
     RECT  60.367 24.786 60.403 24.804 ;
     RECT  60.403 1.998 60.943 24.804 ;
     RECT  60.943 1.962 61.655 24.894 ;
     RECT  61.655 1.998 65.687 24.894 ;
     RECT  65.687 2.034 66.767 24.894 ;
     RECT  66.767 2.07 67.243 24.894 ;
     RECT  67.243 2.07 67.307 25.002 ;
     RECT  67.307 2.151 70.087 25.002 ;
     RECT  70.087 2.151 71.591 25.074 ;
     RECT  71.591 2.151 76.739 24.966 ;
     RECT  76.739 2.151 78.655 24.93 ;
     RECT  78.655 2.151 79.871 25.074 ;
     RECT  79.871 2.151 81.779 24.264 ;
     RECT  79.871 25.056 82.031 25.074 ;
     RECT  81.779 2.151 84.24 23.769 ;
    LAYER M3 ;
     RECT  40.176 0.091 40.194 0.475 ;
     RECT  17.748 0.523 17.766 0.571 ;
     RECT  25.2 0.091 25.218 0.571 ;
     RECT  28.548 0.091 28.566 0.571 ;
     RECT  30.96 0.091 30.978 0.571 ;
     RECT  33.012 0.523 33.03 0.571 ;
     RECT  34.02 0.523 34.038 0.571 ;
     RECT  46.872 0.523 46.89 0.571 ;
     RECT  58.068 0.043 58.086 0.571 ;
     RECT  60.984 0.523 61.002 0.571 ;
     RECT  67.284 0.091 67.842 0.571 ;
     RECT  39.96 0.475 40.194 0.619 ;
     RECT  58.068 0.571 58.734 0.667 ;
     RECT  19.692 0.523 19.71 1.099 ;
     RECT  25.2 0.571 25.686 1.099 ;
     RECT  30.204 0.571 30.222 1.099 ;
     RECT  30.96 0.571 31.374 1.099 ;
     RECT  32.22 0.523 32.238 1.099 ;
     RECT  33.012 0.571 34.038 1.099 ;
     RECT  39.924 0.619 40.194 1.099 ;
     RECT  41.04 0.091 41.058 1.099 ;
     RECT  46.224 0.571 46.89 1.099 ;
     RECT  49.68 0.571 50.274 1.099 ;
     RECT  59.58 0.523 59.598 1.099 ;
     RECT  64.152 0.523 64.17 1.099 ;
     RECT  15.696 0.091 15.714 1.147 ;
     RECT  16.488 0.091 16.506 1.147 ;
     RECT  19.656 1.099 19.71 1.147 ;
     RECT  30.132 1.099 31.374 1.147 ;
     RECT  32.22 1.099 34.038 1.147 ;
     RECT  36.216 0.091 36.234 1.147 ;
     RECT  39.924 1.099 41.058 1.147 ;
     RECT  42.228 0.091 42.246 1.147 ;
     RECT  46.116 1.099 46.89 1.147 ;
     RECT  22.896 0.571 22.914 1.195 ;
     RECT  58.068 0.667 58.77 1.627 ;
     RECT  17.748 0.571 18.306 1.675 ;
     RECT  22.824 1.195 22.914 1.675 ;
     RECT  27.972 0.571 28.566 1.675 ;
     RECT  36 1.147 36.846 1.675 ;
     RECT  45.18 1.147 45.198 1.675 ;
     RECT  45.936 1.147 46.89 1.675 ;
     RECT  54.18 1.099 54.198 1.675 ;
     RECT  57.816 1.627 58.77 1.675 ;
     RECT  59.58 1.099 60.102 1.675 ;
     RECT  60.984 0.571 61.29 1.675 ;
     RECT  15.696 1.147 16.506 1.723 ;
     RECT  17.748 1.675 18.378 1.723 ;
     RECT  19.656 1.147 19.998 1.723 ;
     RECT  21.672 0.571 21.69 1.723 ;
     RECT  22.824 1.675 23.418 1.723 ;
     RECT  25.2 1.099 25.866 1.723 ;
     RECT  27.144 0.091 27.162 1.723 ;
     RECT  27.972 1.675 28.854 1.723 ;
     RECT  29.952 1.147 31.374 1.723 ;
     RECT  32.22 1.147 34.254 1.723 ;
     RECT  35.748 1.675 36.846 1.723 ;
     RECT  38.592 1.675 38.61 1.723 ;
     RECT  39.924 1.147 42.246 1.723 ;
     RECT  45.18 1.675 46.89 1.723 ;
     RECT  49.68 1.099 50.958 1.723 ;
     RECT  52.74 1.675 52.758 1.723 ;
     RECT  54.18 1.675 54.738 1.723 ;
     RECT  56.916 0.523 56.934 1.723 ;
     RECT  57.744 1.675 58.77 1.723 ;
     RECT  59.58 1.675 61.29 1.723 ;
     RECT  62.136 0.571 63.306 1.723 ;
     RECT  64.152 1.099 64.278 1.723 ;
     RECT  65.016 1.147 65.034 1.723 ;
     RECT  66.744 0.571 68.49 1.723 ;
     RECT  15.696 1.723 51.57 1.771 ;
     RECT  52.308 1.723 69.066 1.771 ;
     RECT  15.696 1.771 69.318 2.059 ;
     RECT  15.696 2.059 69.426 2.371 ;
     RECT  2.415 2.143 2.505 2.413 ;
     RECT  7.815 2.143 7.905 2.413 ;
     RECT  13.215 2.143 13.305 2.413 ;
     RECT  72.615 2.143 72.705 2.413 ;
     RECT  78.015 2.143 78.105 2.413 ;
     RECT  83.415 2.143 83.505 2.413 ;
     RECT  15.696 2.371 69.786 2.641 ;
     RECT  70.524 2.251 70.542 2.641 ;
     RECT  15.624 2.641 70.542 3.001 ;
     RECT  15.624 3.001 70.65 3.415 ;
     RECT  15.48 3.415 70.65 3.839 ;
     RECT  15.624 3.839 70.65 4.109 ;
     RECT  15.66 4.109 70.65 4.493 ;
     RECT  15.66 4.493 70.542 4.991 ;
     RECT  16.236 4.991 70.542 5.341 ;
     RECT  16.236 5.341 70.614 5.765 ;
     RECT  16.488 5.765 70.614 6.611 ;
     RECT  16.848 6.611 70.614 7.393 ;
     RECT  16.632 7.393 70.614 10.109 ;
     RECT  70.272 10.109 70.614 10.157 ;
     RECT  16.632 10.109 69.462 11.975 ;
     RECT  70.308 10.157 70.614 12.091 ;
     RECT  16.632 11.975 69.318 13.441 ;
     RECT  70.272 12.091 70.614 13.441 ;
     RECT  16.632 13.441 70.614 13.595 ;
     RECT  16.632 13.595 70.326 13.945 ;
     RECT  15.696 6.511 15.714 15.061 ;
     RECT  16.596 13.945 70.326 15.061 ;
     RECT  7.815 2.413 8.097 16.411 ;
     RECT  14.832 16.069 14.85 16.439 ;
     RECT  15.696 15.061 70.326 16.573 ;
     RECT  71.28 13.639 71.298 16.573 ;
     RECT  15.696 16.573 71.298 16.871 ;
     RECT  78.015 2.413 78.297 17.383 ;
     RECT  4.284 17.419 4.302 17.491 ;
     RECT  7.092 16.411 8.097 17.491 ;
     RECT  74.664 16.843 74.682 17.491 ;
     RECT  7.092 17.491 8.586 17.581 ;
     RECT  4.284 17.491 4.518 17.609 ;
     RECT  4.284 17.609 4.302 17.645 ;
     RECT  7.092 17.581 8.766 17.645 ;
     RECT  15.696 16.871 70.398 17.653 ;
     RECT  71.28 16.871 71.298 17.725 ;
     RECT  76.644 16.645 76.662 17.725 ;
     RECT  7.092 17.645 8.097 17.761 ;
     RECT  15.696 17.653 70.434 17.761 ;
     RECT  71.28 17.725 71.766 17.923 ;
     RECT  72.615 2.413 72.897 17.923 ;
     RECT  14.868 17.653 14.886 18.229 ;
     RECT  15.696 17.761 70.47 18.229 ;
     RECT  71.28 17.923 72.897 18.229 ;
     RECT  76.644 17.725 77.238 18.301 ;
     RECT  80.388 18.031 80.406 18.499 ;
     RECT  74.664 17.491 75.078 18.571 ;
     RECT  76.212 18.301 77.238 18.571 ;
     RECT  12.204 17.923 12.222 18.769 ;
     RECT  14.868 18.229 72.897 18.833 ;
     RECT  11.736 18.769 12.222 18.841 ;
     RECT  14.976 18.833 72.897 19.039 ;
     RECT  74.664 18.571 77.238 19.273 ;
     RECT  80.172 18.499 80.406 19.273 ;
     RECT  9.396 18.697 9.414 19.309 ;
     RECT  9.036 19.309 9.414 19.345 ;
     RECT  14.976 19.039 73.242 19.373 ;
     RECT  78.015 17.383 78.93 19.381 ;
     RECT  79.74 19.273 80.406 19.381 ;
     RECT  14.976 19.373 73.17 19.579 ;
     RECT  74.376 19.273 77.238 19.579 ;
     RECT  78.015 19.381 80.406 19.579 ;
     RECT  11.412 18.841 12.222 19.651 ;
     RECT  13.215 2.413 13.497 19.651 ;
     RECT  11.412 19.651 13.497 20.191 ;
     RECT  14.472 19.579 73.17 20.281 ;
     RECT  74.376 19.579 80.406 20.281 ;
     RECT  11.412 20.191 13.59 20.389 ;
     RECT  11.412 20.389 13.626 20.425 ;
     RECT  10.188 17.725 10.206 20.461 ;
     RECT  11.412 20.425 13.734 20.461 ;
     RECT  10.188 20.461 13.734 21.271 ;
     RECT  14.472 20.281 80.406 21.271 ;
     RECT  9.036 19.345 9.45 21.469 ;
     RECT  10.188 21.271 80.406 21.469 ;
     RECT  9.036 21.469 80.406 21.739 ;
     RECT  81.504 20.191 81.522 21.739 ;
     RECT  6.408 17.761 8.097 21.979 ;
     RECT  9.036 21.739 81.522 21.979 ;
     RECT  6.408 21.979 81.522 22.009 ;
     RECT  5.76 22.009 81.522 22.045 ;
     RECT  5.328 22.045 81.522 22.109 ;
     RECT  5.328 22.109 8.55 22.199 ;
     RECT  5.328 22.199 8.37 22.235 ;
     RECT  5.328 22.235 8.097 22.775 ;
     RECT  7.815 22.775 8.097 23.089 ;
     RECT  9.36 22.109 81.522 23.089 ;
     RECT  7.815 23.089 81.522 23.161 ;
     RECT  2.415 2.413 2.697 23.507 ;
     RECT  83.415 2.413 83.697 23.507 ;
     RECT  7.815 23.161 82.026 23.549 ;
     RECT  4.5 23.431 4.518 23.585 ;
     RECT  7.815 23.549 32.454 23.585 ;
     RECT  33.192 23.549 47.43 23.585 ;
     RECT  50.616 23.549 69.426 23.585 ;
     RECT  58.896 23.585 63.018 23.621 ;
     RECT  68.508 23.585 69.426 23.621 ;
     RECT  7.815 23.585 26.262 23.657 ;
     RECT  37.512 23.585 41.85 23.657 ;
     RECT  48.312 23.549 49.842 23.657 ;
     RECT  59.544 23.621 63.018 23.657 ;
     RECT  66.096 23.585 67.554 23.657 ;
     RECT  5.328 22.775 6.75 23.701 ;
     RECT  27.072 23.585 32.454 23.729 ;
     RECT  33.624 23.585 36.558 23.729 ;
     RECT  44.928 23.585 47.43 23.729 ;
     RECT  50.616 23.585 54.306 23.729 ;
     RECT  66.168 23.657 67.554 23.729 ;
     RECT  68.868 23.621 69.426 23.729 ;
     RECT  70.272 23.549 82.026 23.729 ;
     RECT  2.415 23.507 2.505 23.777 ;
     RECT  7.815 23.657 19.782 23.777 ;
     RECT  51.015 23.729 54.306 23.777 ;
     RECT  70.704 23.729 82.026 23.777 ;
     RECT  83.415 23.507 83.505 23.777 ;
     RECT  66.168 23.729 66.258 23.789 ;
     RECT  8.352 23.777 19.782 23.819 ;
     RECT  37.512 23.657 41.634 23.819 ;
     RECT  59.76 23.657 63.018 23.819 ;
     RECT  63.756 23.585 64.998 23.819 ;
     RECT  66.168 23.789 66.186 23.819 ;
     RECT  73.26 23.777 82.026 23.819 ;
     RECT  55.08 23.585 58.122 23.837 ;
     RECT  63 23.819 63.018 23.837 ;
     RECT  67.104 23.729 67.554 23.837 ;
     RECT  20.52 23.657 21.33 23.885 ;
     RECT  55.08 23.837 58.086 23.885 ;
     RECT  22.14 23.657 22.23 23.891 ;
     RECT  63.828 23.819 64.998 23.891 ;
     RECT  68.868 23.729 68.886 23.891 ;
     RECT  8.532 23.819 19.782 23.927 ;
     RECT  23.364 23.657 26.262 23.927 ;
     RECT  67.356 23.837 67.554 23.927 ;
     RECT  27.072 23.729 27.918 23.933 ;
     RECT  28.908 23.729 30.582 23.933 ;
     RECT  33.66 23.729 36.558 23.933 ;
     RECT  37.512 23.819 40.41 23.933 ;
     RECT  44.928 23.729 47.214 23.933 ;
     RECT  55.08 23.885 55.602 23.933 ;
     RECT  56.376 23.885 58.086 23.933 ;
     RECT  59.76 23.819 62.154 23.933 ;
     RECT  37.512 23.933 40.158 23.981 ;
     RECT  51.156 23.777 54.306 23.981 ;
     RECT  14.112 23.927 19.026 23.999 ;
     RECT  22.212 23.891 22.23 23.999 ;
     RECT  33.66 23.933 34.614 24.029 ;
     RECT  41.22 23.819 41.634 24.029 ;
     RECT  14.112 23.999 18.594 24.173 ;
     RECT  8.964 23.927 13.194 24.221 ;
     RECT  78.876 23.819 82.026 24.221 ;
     RECT  8.964 24.221 13.05 24.233 ;
     RECT  78.876 24.221 80.514 24.269 ;
     RECT  73.332 23.819 77.85 24.314 ;
     RECT  9.36 24.233 13.05 24.317 ;
     RECT  19.764 23.927 19.782 24.317 ;
     RECT  4.716 23.701 6.93 24.359 ;
     RECT  73.332 24.314 74.934 24.359 ;
     RECT  14.436 24.173 18.594 24.365 ;
     RECT  70.704 23.777 72.414 24.395 ;
     RECT  4.968 24.359 6.93 24.431 ;
     RECT  71.172 24.395 72.414 24.431 ;
     RECT  41.22 24.029 41.454 24.461 ;
     RECT  73.404 24.359 74.934 24.461 ;
     RECT  28.908 23.933 28.926 24.509 ;
     RECT  31.356 23.729 32.454 24.509 ;
     RECT  33.66 24.029 33.75 24.509 ;
     RECT  37.512 23.981 40.122 24.509 ;
     RECT  41.22 24.461 41.346 24.509 ;
     RECT  44.928 23.933 47.178 24.509 ;
     RECT  56.736 23.933 58.05 24.509 ;
     RECT  75.78 24.314 77.85 24.509 ;
     RECT  20.52 23.885 21.258 24.557 ;
     RECT  33.732 24.509 33.75 24.557 ;
     RECT  42.588 23.585 44.118 24.557 ;
     RECT  46.332 24.509 47.178 24.557 ;
     RECT  48.312 23.657 49.014 24.557 ;
     RECT  51.156 23.981 53.874 24.557 ;
     RECT  46.44 24.557 47.178 24.605 ;
     RECT  73.512 24.461 74.934 24.701 ;
     RECT  73.512 24.701 74.574 24.749 ;
     RECT  26.244 23.927 26.262 24.781 ;
     RECT  60.408 23.933 62.154 24.781 ;
     RECT  81.468 24.221 82.026 24.797 ;
     RECT  4.968 24.431 6.246 24.809 ;
     RECT  78.876 24.269 80.262 24.809 ;
     RECT  23.364 23.927 25.47 24.826 ;
     RECT  79.632 24.809 80.262 24.845 ;
     RECT  74.52 24.749 74.574 24.854 ;
     RECT  77.508 24.509 77.85 24.871 ;
     RECT  9.396 24.317 13.05 24.893 ;
     RECT  23.256 24.826 25.47 24.893 ;
     RECT  78.876 24.809 78.894 24.893 ;
     RECT  79.632 24.845 79.866 24.899 ;
     RECT  9.396 24.893 12.582 24.935 ;
     RECT  79.632 24.899 79.65 24.935 ;
     RECT  5.58 24.809 6.246 24.971 ;
     RECT  20.52 24.557 21.15 24.979 ;
     RECT  67.788 24.403 67.806 24.979 ;
     RECT  56.844 24.509 58.05 24.989 ;
     RECT  75.78 24.509 76.77 24.989 ;
     RECT  10.26 24.935 12.582 25.007 ;
     RECT  56.844 24.989 56.934 25.037 ;
     RECT  73.512 24.749 73.602 25.037 ;
     RECT  5.58 24.971 5.598 25.043 ;
     RECT  77.508 24.871 78.066 25.051 ;
     RECT  82.008 24.797 82.026 25.079 ;
     RECT  29.664 23.933 30.582 25.085 ;
     RECT  31.356 24.509 31.374 25.085 ;
     RECT  32.148 24.509 32.166 25.085 ;
     RECT  34.596 24.029 34.614 25.085 ;
     RECT  35.388 23.933 35.766 25.085 ;
     RECT  37.944 24.509 40.122 25.085 ;
     RECT  41.22 24.509 41.238 25.085 ;
     RECT  42.588 24.557 42.606 25.085 ;
     RECT  43.452 24.557 44.118 25.085 ;
     RECT  46.908 24.605 47.178 25.085 ;
     RECT  48.42 24.557 49.014 25.085 ;
     RECT  49.824 23.657 49.842 25.085 ;
     RECT  55.584 23.933 55.602 25.085 ;
     RECT  57.708 24.989 58.05 25.085 ;
     RECT  14.508 24.365 18.594 25.133 ;
     RECT  19.944 24.979 21.15 25.133 ;
     RECT  24.516 24.893 25.47 25.133 ;
     RECT  29.664 25.085 29.682 25.133 ;
     RECT  30.528 25.085 30.582 25.133 ;
     RECT  39.024 25.085 39.726 25.133 ;
     RECT  19.944 25.133 19.962 25.181 ;
     RECT  60.372 24.781 62.154 25.181 ;
     RECT  26.244 24.781 26.298 25.229 ;
     RECT  30.564 25.133 30.582 25.229 ;
     RECT  44.928 24.509 45.594 25.229 ;
     RECT  60.372 25.181 60.39 25.229 ;
     RECT  14.508 25.133 17.37 25.277 ;
     RECT  44.928 25.229 44.946 25.277 ;
     RECT  14.508 25.277 17.118 25.421 ;
     RECT  71.172 24.431 72.378 25.421 ;
     RECT  55.476 25.291 55.494 25.469 ;
     RECT  72.36 25.421 72.378 25.469 ;
     RECT  12.564 25.007 12.582 25.517 ;
     RECT  24.552 25.133 25.47 25.517 ;
     RECT  67.248 24.979 67.806 25.517 ;
     RECT  75.78 24.989 75.798 25.517 ;
     RECT  18.144 25.133 18.594 25.531 ;
     RECT  24.948 25.517 25.47 25.531 ;
     RECT  10.26 25.007 11.43 25.565 ;
     RECT  50.616 25.435 50.634 25.565 ;
     RECT  70.092 25.051 70.11 25.565 ;
     RECT  21.132 25.133 21.15 25.579 ;
     RECT  23.256 24.893 23.562 25.579 ;
     RECT  35.388 25.085 35.406 25.579 ;
     RECT  14.508 25.421 14.85 25.613 ;
     RECT  71.172 25.421 71.19 25.613 ;
     RECT  18.144 25.531 18.846 25.627 ;
     RECT  19.584 25.483 19.746 25.627 ;
     RECT  14.508 25.613 14.526 25.661 ;
     RECT  21.132 25.579 21.51 25.661 ;
     RECT  51.624 24.557 53.514 25.661 ;
     RECT  56.88 25.037 56.934 25.661 ;
     RECT  74.556 24.854 74.574 25.661 ;
     RECT  50.724 25.579 50.742 25.675 ;
     RECT  10.26 25.565 10.89 25.709 ;
     RECT  35.316 25.579 35.406 25.709 ;
     RECT  50.724 25.675 50.958 25.709 ;
     RECT  67.248 25.517 67.266 25.709 ;
     RECT  77.508 25.051 78.678 25.709 ;
     RECT  27.72 23.933 27.738 25.723 ;
     RECT  63.828 23.891 64.962 25.723 ;
     RECT  9.396 24.935 9.414 25.757 ;
     RECT  18.144 25.627 19.746 25.757 ;
     RECT  24.948 25.531 26.01 25.757 ;
     RECT  63.828 25.723 65.07 25.757 ;
     RECT  77.508 25.709 78.066 25.757 ;
     RECT  10.26 25.709 10.278 25.805 ;
     RECT  15.984 25.421 17.118 25.805 ;
     RECT  18.828 25.757 19.746 25.805 ;
     RECT  21.492 25.661 21.51 25.805 ;
     RECT  22.86 25.579 23.562 25.805 ;
     RECT  25.416 25.757 26.01 25.805 ;
     RECT  27 25.723 27.738 25.805 ;
     RECT  32.688 25.531 32.742 25.805 ;
     RECT  35.388 25.709 35.406 25.805 ;
     RECT  39.708 25.133 39.726 25.805 ;
     RECT  40.68 25.675 40.698 25.805 ;
     RECT  42.408 25.675 42.426 25.805 ;
     RECT  43.452 25.085 43.47 25.805 ;
     RECT  47.16 25.085 47.178 25.805 ;
     RECT  50.94 25.709 50.958 25.805 ;
     RECT  52.308 25.661 53.514 25.805 ;
     RECT  56.88 25.661 56.898 25.805 ;
     RECT  61.56 25.181 62.154 25.805 ;
     RECT  73.584 25.037 73.602 25.805 ;
     RECT  15.984 25.805 16.542 25.853 ;
     RECT  27 25.805 27.234 25.853 ;
     RECT  65.052 25.757 65.07 25.853 ;
     RECT  76.752 24.989 76.77 25.853 ;
     RECT  15.984 25.853 16.002 25.901 ;
     RECT  18.828 25.805 18.954 25.901 ;
     RECT  25.884 25.805 26.01 25.901 ;
     RECT  27.216 25.853 27.234 25.901 ;
     RECT  32.688 25.805 32.706 25.901 ;
     RECT  58.644 25.771 58.662 25.901 ;
     RECT  62.136 25.805 62.154 25.901 ;
     RECT  65.844 25.723 65.862 25.901 ;
     RECT  78.048 25.757 78.066 25.901 ;
    LAYER M4 ;
     RECT  0.06 17.328 0.227 17.448 ;
     RECT  0.181 13.056 2.408 13.08 ;
     RECT  0.227 17.424 2.408 17.448 ;
     RECT  2.408 2.148 2.512 23.772 ;
     RECT  2.512 2.418 2.704 23.502 ;
     RECT  2.704 17.424 4.313 17.448 ;
     RECT  5.497 23.28 5.929 23.304 ;
     RECT  6.073 22.08 6.505 22.104 ;
     RECT  6.505 21.456 6.541 22.104 ;
     RECT  5.929 23.28 6.541 23.592 ;
     RECT  6.541 21.456 6.577 23.592 ;
     RECT  2.704 13.056 7.808 13.08 ;
     RECT  6.721 20.064 7.808 20.088 ;
     RECT  6.577 21.456 7.808 23.64 ;
     RECT  7.808 2.148 7.912 23.772 ;
     RECT  7.912 2.418 8.104 23.64 ;
     RECT  8.104 21.456 9.349 23.64 ;
     RECT  9.385 25.728 10.249 25.752 ;
     RECT  10.249 25.728 10.841 25.8 ;
     RECT  10.841 25.68 11.401 25.8 ;
     RECT  9.349 21.456 11.941 24.312 ;
     RECT  11.941 21.408 12.373 24.312 ;
     RECT  11.401 25.536 12.373 25.8 ;
     RECT  8.104 13.056 13.208 13.08 ;
     RECT  8.104 20.064 13.208 20.088 ;
     RECT  12.373 21.408 13.208 25.8 ;
     RECT  13.208 2.148 13.312 25.8 ;
     RECT  13.312 2.418 13.504 25.8 ;
     RECT  13.504 21.408 14.605 25.8 ;
     RECT  13.504 20.064 14.785 20.088 ;
     RECT  14.605 21.264 14.785 25.8 ;
     RECT  14.785 20.064 15.973 25.8 ;
     RECT  16.069 1.728 16.153 1.752 ;
     RECT  16.153 1.152 16.237 1.752 ;
     RECT  15.973 20.064 16.261 25.896 ;
     RECT  16.237 1.2 16.345 1.752 ;
     RECT  16.345 1.728 16.412 1.752 ;
     RECT  16.441 4.752 16.661 4.776 ;
     RECT  16.225 3.408 16.693 3.432 ;
     RECT  15.685 0.096 16.787 0.12 ;
     RECT  16.693 3.408 16.883 4.392 ;
     RECT  16.261 19.536 16.909 25.896 ;
     RECT  16.909 17.664 16.933 17.688 ;
     RECT  16.909 19.392 16.933 25.896 ;
     RECT  16.729 5.712 17.129 5.736 ;
     RECT  16.933 17.664 17.461 25.896 ;
     RECT  17.449 6.816 17.629 6.84 ;
     RECT  16.883 4.368 17.845 4.392 ;
     RECT  17.629 6 17.989 6.84 ;
     RECT  17.989 6 18.125 7.176 ;
     RECT  17.845 3.888 18.181 4.392 ;
     RECT  18.125 5.712 18.181 7.176 ;
     RECT  17.737 0.528 18.277 0.552 ;
     RECT  16.412 1.728 18.349 2.28 ;
     RECT  17.461 16.848 18.385 25.896 ;
     RECT  18.277 0.528 18.421 0.6 ;
     RECT  18.181 3.888 18.421 7.176 ;
     RECT  18.349 1.68 18.433 2.28 ;
     RECT  18.421 0.144 18.515 0.6 ;
     RECT  18.433 1.728 18.608 2.28 ;
     RECT  18.421 3.888 18.608 7.224 ;
     RECT  16.801 10.128 18.608 10.152 ;
     RECT  13.504 13.056 18.608 13.08 ;
     RECT  18.385 16.272 18.608 25.896 ;
     RECT  18.515 0.144 18.707 0.168 ;
     RECT  18.608 1.728 18.904 25.896 ;
     RECT  18.904 10.032 19.001 10.152 ;
     RECT  18.904 3.696 19.469 7.224 ;
     RECT  18.904 1.728 19.645 2.28 ;
     RECT  19.645 1.104 19.681 2.28 ;
     RECT  19.469 3.696 20.185 4.488 ;
     RECT  19.681 0.528 20.243 2.28 ;
     RECT  20.243 0.528 20.627 0.552 ;
     RECT  18.904 15.408 20.657 25.896 ;
     RECT  19.001 10.032 20.761 10.056 ;
     RECT  19.469 5.616 21.049 7.224 ;
     RECT  21.049 5.616 21.161 7.368 ;
     RECT  21.161 6 21.685 7.368 ;
     RECT  21.625 8.544 21.685 8.568 ;
     RECT  20.243 1.728 21.692 2.28 ;
     RECT  20.185 3.408 21.692 4.488 ;
     RECT  21.617 0.576 21.701 0.6 ;
     RECT  20.657 16.848 21.733 25.896 ;
     RECT  21.692 1.728 21.781 4.488 ;
     RECT  21.781 1.728 21.889 4.536 ;
     RECT  21.889 3.36 22.453 4.536 ;
     RECT  22.453 3.36 22.489 4.728 ;
     RECT  21.685 6 22.745 8.568 ;
     RECT  21.889 1.728 22.789 2.28 ;
     RECT  20.657 15.408 22.849 15.432 ;
     RECT  21.733 16.608 22.849 25.896 ;
     RECT  22.789 1.2 22.876 2.28 ;
     RECT  22.876 1.68 22.885 2.28 ;
     RECT  22.489 3.36 22.885 5.016 ;
     RECT  22.885 0.576 22.969 0.6 ;
     RECT  22.885 1.68 22.993 5.016 ;
     RECT  22.745 6 22.993 8.52 ;
     RECT  22.849 15.408 23.065 25.896 ;
     RECT  22.993 1.68 23.507 8.52 ;
     RECT  23.507 1.728 23.893 8.52 ;
     RECT  23.893 1.728 24.008 8.856 ;
     RECT  20.761 10.032 24.008 10.104 ;
     RECT  18.904 13.056 24.008 13.08 ;
     RECT  23.065 14.496 24.008 25.896 ;
     RECT  23.941 0.144 24.037 0.168 ;
     RECT  24.008 1.728 24.304 25.896 ;
     RECT  24.037 0.144 24.325 0.408 ;
     RECT  24.325 0.144 24.467 0.504 ;
     RECT  24.467 0.144 24.515 0.168 ;
     RECT  24.304 15.504 25.085 25.896 ;
     RECT  25.189 0.096 25.273 0.12 ;
     RECT  24.304 14.496 25.477 14.52 ;
     RECT  25.477 14.496 25.589 14.856 ;
     RECT  25.085 15.936 25.589 25.896 ;
     RECT  25.657 0.576 25.693 0.6 ;
     RECT  24.304 1.728 25.693 8.856 ;
     RECT  25.693 0.576 25.741 8.856 ;
     RECT  25.589 15.936 25.985 18.792 ;
     RECT  25.741 1.104 26.225 8.856 ;
     RECT  24.304 10.032 26.225 10.68 ;
     RECT  26.225 1.104 26.309 10.68 ;
     RECT  25.589 19.776 26.309 25.896 ;
     RECT  26.309 1.104 26.483 8.856 ;
     RECT  25.985 16.08 26.665 18.792 ;
     RECT  26.309 19.776 26.665 22.824 ;
     RECT  26.309 23.808 26.771 25.896 ;
     RECT  27.089 0.096 27.173 0.12 ;
     RECT  26.771 23.808 27.347 24.12 ;
     RECT  26.771 25.584 27.443 25.896 ;
     RECT  26.665 16.08 27.493 22.824 ;
     RECT  27.347 23.808 27.493 23.928 ;
     RECT  25.589 14.496 27.565 14.52 ;
     RECT  27.493 16.08 27.601 23.928 ;
     RECT  27.601 15.984 27.635 23.928 ;
     RECT  26.483 1.728 27.673 8.856 ;
     RECT  26.309 10.032 27.673 10.68 ;
     RECT  27.635 15.984 27.731 22.872 ;
     RECT  27.565 14.496 27.829 14.904 ;
     RECT  27.731 15.984 27.829 22.824 ;
     RECT  27.635 23.904 27.964 23.928 ;
     RECT  27.961 0.576 28.115 0.6 ;
     RECT  27.829 14.496 28.217 22.824 ;
     RECT  27.443 25.776 28.499 25.896 ;
     RECT  28.537 0.096 28.621 0.12 ;
     RECT  27.673 1.728 28.792 10.68 ;
     RECT  28.792 1.68 28.979 10.68 ;
     RECT  28.217 20.304 29.125 22.824 ;
     RECT  29.125 20.304 29.173 23.352 ;
     RECT  28.897 24.48 29.173 24.504 ;
     RECT  28.979 1.728 29.408 10.68 ;
     RECT  24.304 13.056 29.408 13.08 ;
     RECT  28.217 14.496 29.408 19.272 ;
     RECT  29.173 20.304 29.408 24.504 ;
     RECT  29.269 0.144 29.459 0.168 ;
     RECT  29.408 1.728 29.555 24.504 ;
     RECT  29.555 1.728 29.651 23.928 ;
     RECT  28.499 25.872 29.653 25.896 ;
     RECT  29.651 1.728 29.704 23.88 ;
     RECT  29.704 1.728 30.121 10.68 ;
     RECT  29.704 14.496 30.197 23.88 ;
     RECT  30.121 0.576 30.757 10.68 ;
     RECT  30.757 0.288 30.853 10.68 ;
     RECT  30.853 0.192 30.899 10.68 ;
     RECT  30.899 0.192 30.949 0.6 ;
     RECT  30.949 0.096 31.033 0.6 ;
     RECT  31.033 0.576 31.385 0.6 ;
     RECT  30.197 14.496 31.501 23.4 ;
     RECT  31.501 14.496 31.529 23.352 ;
     RECT  29.653 25.056 31.993 25.896 ;
     RECT  31.993 24.48 32.243 25.896 ;
     RECT  31.529 14.496 32.339 22.824 ;
     RECT  32.243 24.48 32.465 24.504 ;
     RECT  32.209 0.528 32.497 0.552 ;
     RECT  30.899 1.728 32.497 10.68 ;
     RECT  32.339 14.496 32.537 22.536 ;
     RECT  32.243 25.536 32.717 25.896 ;
     RECT  32.717 25.536 32.819 25.8 ;
     RECT  32.819 25.536 32.867 25.56 ;
     RECT  32.497 0.528 33.011 10.68 ;
     RECT  32.537 20.544 33.365 22.536 ;
     RECT  33.365 21.072 33.404 22.536 ;
     RECT  33.404 21.072 33.491 22.824 ;
     RECT  33.589 25.008 33.605 25.032 ;
     RECT  33.605 24.48 33.713 25.032 ;
     RECT  33.713 23.904 33.932 25.032 ;
     RECT  32.537 16.512 33.973 19.416 ;
     RECT  33.932 23.856 34.013 25.032 ;
     RECT  34.013 23.856 34.067 23.976 ;
     RECT  34.013 24.96 34.165 25.032 ;
     RECT  33.011 0.528 34.225 0.6 ;
     RECT  33.011 1.728 34.225 10.68 ;
     RECT  34.225 0.528 34.355 10.68 ;
     RECT  34.165 24.96 34.357 25.704 ;
     RECT  34.355 0.528 34.451 0.552 ;
     RECT  33.491 21.072 34.453 22.728 ;
     RECT  34.453 20.976 34.513 22.728 ;
     RECT  34.355 1.728 34.765 10.68 ;
     RECT  34.765 1.728 34.808 10.728 ;
     RECT  29.704 12.816 34.808 13.08 ;
     RECT  32.537 14.496 34.808 15.336 ;
     RECT  33.973 16.512 34.808 19.944 ;
     RECT  34.513 20.976 34.808 23.772 ;
     RECT  34.808 1.728 35.104 23.772 ;
     RECT  35.104 14.496 35.153 23.772 ;
     RECT  35.077 0.144 35.267 0.168 ;
     RECT  34.357 24.96 35.333 25.752 ;
     RECT  35.333 24.96 35.417 25.8 ;
     RECT  35.104 1.728 35.698 10.68 ;
     RECT  35.417 24.96 35.777 25.08 ;
     RECT  35.777 24.96 35.795 24.984 ;
     RECT  36.037 0.096 36.245 0.12 ;
     RECT  35.153 14.496 36.371 23.928 ;
     RECT  36.371 14.496 36.515 22.824 ;
     RECT  35.698 1.68 36.517 10.68 ;
     RECT  36.517 1.2 36.709 10.68 ;
     RECT  36.457 11.664 36.709 11.688 ;
     RECT  36.709 1.2 36.745 11.688 ;
     RECT  36.745 1.2 36.817 11.832 ;
     RECT  36.817 1.152 36.893 11.832 ;
     RECT  36.893 1.152 36.947 11.688 ;
     RECT  35.104 12.912 36.961 13.08 ;
     RECT  36.515 14.496 36.961 22.248 ;
     RECT  36.371 23.904 37.381 23.928 ;
     RECT  37.381 23.376 37.457 23.928 ;
     RECT  36.961 12.912 37.465 22.248 ;
     RECT  37.457 23.376 37.541 24.504 ;
     RECT  37.541 23.376 37.613 23.928 ;
     RECT  37.613 23.376 37.621 23.832 ;
     RECT  37.465 12.768 37.669 22.248 ;
     RECT  37.621 23.376 37.669 23.496 ;
     RECT  37.765 25.056 38.101 25.08 ;
     RECT  37.669 12.768 38.195 23.496 ;
     RECT  38.101 25.056 38.405 25.656 ;
     RECT  36.947 1.728 38.581 11.688 ;
     RECT  38.581 1.68 38.689 11.688 ;
     RECT  38.195 12.768 38.689 22.824 ;
     RECT  38.725 23.904 38.809 23.928 ;
     RECT  38.405 25.104 39.059 25.656 ;
     RECT  39.445 23.952 39.493 23.976 ;
     RECT  38.689 1.68 39.637 22.824 ;
     RECT  39.059 25.632 39.653 25.656 ;
     RECT  39.493 23.952 39.781 24.504 ;
     RECT  39.781 23.904 39.809 24.504 ;
     RECT  39.637 1.152 39.877 22.824 ;
     RECT  39.809 23.904 39.973 23.976 ;
     RECT  39.877 0.48 40.021 22.824 ;
     RECT  39.653 25.632 40.049 25.8 ;
     RECT  40.021 0.144 40.165 22.824 ;
     RECT  40.165 0.096 40.208 22.824 ;
     RECT  39.973 23.856 40.208 23.976 ;
     RECT  40.208 0.096 40.211 23.976 ;
     RECT  40.211 1.104 40.307 23.976 ;
     RECT  40.307 1.104 40.499 23.928 ;
     RECT  40.499 1.152 40.504 23.928 ;
     RECT  40.049 24.96 40.709 25.8 ;
     RECT  40.504 1.152 40.925 23.352 ;
     RECT  40.211 0.096 41.113 0.12 ;
     RECT  40.709 24.96 41.293 25.752 ;
     RECT  41.317 24.432 41.401 24.504 ;
     RECT  41.401 24.432 41.465 24.456 ;
     RECT  41.509 23.904 41.609 24.024 ;
     RECT  41.609 24 41.747 24.024 ;
     RECT  40.925 1.152 41.843 22.488 ;
     RECT  41.843 1.728 42.149 22.488 ;
     RECT  41.293 25.728 42.37 25.752 ;
     RECT  42.37 25.68 42.373 25.8 ;
     RECT  42.217 0.096 42.515 0.12 ;
     RECT  42.373 25.056 42.617 25.8 ;
     RECT  42.149 22.464 42.709 22.488 ;
     RECT  42.149 1.728 42.901 21.144 ;
     RECT  42.901 1.152 43.091 21.144 ;
     RECT  42.709 22.464 43.333 22.824 ;
     RECT  43.091 1.728 43.381 21.144 ;
     RECT  42.617 25.68 43.481 25.8 ;
     RECT  42.757 24.528 43.613 24.552 ;
     RECT  43.481 25.68 43.613 25.752 ;
     RECT  43.381 1.728 43.765 21.24 ;
     RECT  43.333 22.224 43.765 22.824 ;
     RECT  43.613 24.528 43.793 25.752 ;
     RECT  43.765 1.728 43.801 22.824 ;
     RECT  43.793 23.904 43.801 25.752 ;
     RECT  43.801 1.728 43.877 25.752 ;
     RECT  43.877 1.728 43.955 23.4 ;
     RECT  43.877 24.528 44.051 25.752 ;
     RECT  44.051 25.056 44.173 25.752 ;
     RECT  43.955 1.728 44.237 22.536 ;
     RECT  44.173 25.152 44.435 25.752 ;
     RECT  44.435 25.152 45.011 25.272 ;
     RECT  44.237 1.728 45.169 22.488 ;
     RECT  45.011 25.152 45.404 25.224 ;
     RECT  45.404 25.104 45.605 25.224 ;
     RECT  45.169 1.152 45.608 22.488 ;
     RECT  45.605 25.104 45.628 25.128 ;
     RECT  45.608 1.152 45.637 23.772 ;
     RECT  45.637 1.152 45.904 24.6 ;
     RECT  45.637 0.144 45.925 0.168 ;
     RECT  45.904 1.152 45.925 22.824 ;
     RECT  45.925 0.144 46.019 22.824 ;
     RECT  46.019 0.24 46.115 22.824 ;
     RECT  45.904 23.856 46.469 24.6 ;
     RECT  46.115 0.528 46.643 22.824 ;
     RECT  46.643 1.728 46.787 22.824 ;
     RECT  46.643 0.528 46.873 0.6 ;
     RECT  46.789 25.056 46.885 25.08 ;
     RECT  46.885 25.056 46.937 25.8 ;
     RECT  46.469 23.856 46.981 23.928 ;
     RECT  46.873 0.528 47.123 0.552 ;
     RECT  46.937 25.776 47.189 25.8 ;
     RECT  46.981 23.376 47.225 23.928 ;
     RECT  46.787 1.728 48.125 21.96 ;
     RECT  48.125 20.736 48.229 21.96 ;
     RECT  47.225 23.376 48.293 23.4 ;
     RECT  48.293 23.376 48.301 23.928 ;
     RECT  48.037 25.056 48.301 25.08 ;
     RECT  48.301 23.376 48.413 25.08 ;
     RECT  48.229 20.736 48.437 22.2 ;
     RECT  48.413 23.952 48.467 25.08 ;
     RECT  48.125 1.728 48.665 19.416 ;
     RECT  48.467 23.952 48.737 24.024 ;
     RECT  48.737 24 48.851 24.024 ;
     RECT  48.437 20.736 48.949 22.344 ;
     RECT  48.665 1.728 48.997 10.68 ;
     RECT  48.997 1.152 49.187 10.68 ;
     RECT  48.665 11.952 49.309 19.416 ;
     RECT  48.949 20.736 49.429 22.584 ;
     RECT  49.309 11.952 49.58 19.56 ;
     RECT  49.429 20.64 49.58 22.584 ;
     RECT  49.58 11.952 49.841 22.584 ;
     RECT  48.467 25.056 49.853 25.08 ;
     RECT  49.841 11.952 49.985 22.776 ;
     RECT  49.985 11.952 50.053 22.824 ;
     RECT  50.053 11.952 50.317 23.352 ;
     RECT  49.669 0.576 50.329 0.6 ;
     RECT  50.605 25.344 50.713 25.56 ;
     RECT  50.713 25.344 50.725 25.704 ;
     RECT  50.725 25.344 50.917 25.8 ;
     RECT  49.187 1.728 50.929 10.68 ;
     RECT  50.917 25.056 50.969 25.8 ;
     RECT  50.929 1.104 51.008 10.68 ;
     RECT  50.317 11.904 51.008 23.352 ;
     RECT  51.008 1.104 51.013 23.772 ;
     RECT  50.969 25.056 51.013 25.752 ;
     RECT  51.013 1.104 51.304 25.752 ;
     RECT  51.304 1.104 51.539 10.68 ;
     RECT  51.304 20.544 51.653 25.752 ;
     RECT  51.304 11.952 51.941 19.56 ;
     RECT  51.653 20.544 52.229 24.504 ;
     RECT  51.653 25.536 52.253 25.752 ;
     RECT  52.253 25.536 52.259 25.8 ;
     RECT  51.941 12.24 52.265 19.56 ;
     RECT  52.265 12.24 52.307 19.464 ;
     RECT  52.259 25.632 52.409 25.8 ;
     RECT  52.229 23.376 52.445 24.504 ;
     RECT  52.445 23.952 52.595 24.504 ;
     RECT  51.539 1.728 52.632 10.68 ;
     RECT  52.632 1.68 52.805 10.68 ;
     RECT  52.409 25.68 53.315 25.8 ;
     RECT  53.315 25.776 53.525 25.8 ;
     RECT  52.307 12.24 53.557 19.368 ;
     RECT  52.229 20.544 53.557 22.2 ;
     RECT  53.557 12.24 53.701 22.2 ;
     RECT  53.089 24.528 53.797 24.552 ;
     RECT  53.797 23.904 53.939 24.552 ;
     RECT  53.701 12.24 54.065 22.776 ;
     RECT  52.805 1.728 54.14 10.68 ;
     RECT  54.14 1.104 54.227 10.68 ;
     RECT  54.065 21.072 54.517 22.776 ;
     RECT  53.939 23.904 54.517 23.976 ;
     RECT  54.517 21.072 54.899 23.976 ;
     RECT  54.899 21.072 55.145 23.928 ;
     RECT  54.227 1.68 55.187 10.68 ;
     RECT  55.145 23.328 55.289 23.928 ;
     RECT  55.189 25.68 55.421 25.704 ;
     RECT  55.421 25.44 55.429 25.704 ;
     RECT  55.429 25.2 55.525 25.704 ;
     RECT  55.145 21.072 55.573 22.2 ;
     RECT  54.065 12.24 56.053 19.992 ;
     RECT  55.573 21.024 56.053 22.2 ;
     RECT  56.053 12.24 56.197 22.2 ;
     RECT  55.289 23.328 56.365 23.88 ;
     RECT  55.187 1.728 56.408 10.68 ;
     RECT  56.197 12.24 56.408 22.248 ;
     RECT  56.365 23.328 56.408 23.928 ;
     RECT  55.525 25.056 56.485 25.704 ;
     RECT  56.485 25.056 56.581 25.8 ;
     RECT  56.408 1.728 56.677 23.928 ;
     RECT  56.581 25.008 56.677 25.8 ;
     RECT  56.677 1.728 56.704 25.8 ;
     RECT  56.704 12.24 56.909 25.8 ;
     RECT  56.905 0.528 57.107 0.552 ;
     RECT  56.909 12.24 57.251 25.752 ;
     RECT  56.704 1.728 57.305 10.872 ;
     RECT  57.251 12.24 57.521 25.08 ;
     RECT  57.305 1.728 57.733 10.68 ;
     RECT  57.733 1.68 57.805 10.68 ;
     RECT  57.521 25.056 58.501 25.08 ;
     RECT  57.805 1.632 58.547 10.68 ;
     RECT  58.501 25.008 58.589 25.08 ;
     RECT  58.589 25.008 58.633 25.8 ;
     RECT  58.057 0.048 58.693 0.072 ;
     RECT  57.521 12.24 58.693 23.928 ;
     RECT  58.633 25.008 58.693 25.896 ;
     RECT  58.693 0.048 58.741 0.6 ;
     RECT  58.693 12.24 59.201 25.896 ;
     RECT  58.547 1.728 59.221 10.68 ;
     RECT  59.201 12 59.285 25.896 ;
     RECT  59.221 1.728 59.429 10.776 ;
     RECT  59.285 12.24 59.555 25.896 ;
     RECT  59.555 13.344 59.717 25.896 ;
     RECT  58.741 0.048 59.804 0.696 ;
     RECT  59.429 1.728 59.804 10.68 ;
     RECT  59.717 13.344 60.131 22.488 ;
     RECT  59.804 0.048 60.467 10.68 ;
     RECT  60.467 1.68 60.661 10.68 ;
     RECT  60.131 13.92 60.805 22.488 ;
     RECT  59.717 23.568 60.805 25.896 ;
     RECT  60.661 1.68 60.947 10.92 ;
     RECT  60.467 0.048 61.049 0.648 ;
     RECT  60.947 1.728 61.808 10.92 ;
     RECT  59.555 12.24 61.808 12.264 ;
     RECT  60.805 13.92 61.808 25.896 ;
     RECT  61.808 1.728 62.104 25.896 ;
     RECT  62.104 13.92 62.165 25.896 ;
     RECT  62.104 1.728 62.557 10.92 ;
     RECT  62.557 1.68 62.957 10.92 ;
     RECT  61.049 0.048 64.249 0.6 ;
     RECT  62.957 1.68 64.249 10.68 ;
     RECT  62.165 13.92 64.541 25.8 ;
     RECT  64.249 0.048 64.595 10.68 ;
     RECT  62.104 12.24 64.757 12.264 ;
     RECT  64.541 16.896 65.041 25.8 ;
     RECT  64.595 1.152 65.089 10.68 ;
     RECT  65.089 1.728 65.477 10.68 ;
     RECT  64.541 13.92 65.581 15.816 ;
     RECT  65.041 16.896 65.581 25.848 ;
     RECT  65.581 13.92 65.585 25.848 ;
     RECT  65.585 13.92 65.765 14.856 ;
     RECT  65.585 16.56 65.833 25.848 ;
     RECT  65.477 1.728 66.089 10.152 ;
     RECT  65.765 14.496 66.125 14.856 ;
     RECT  65.833 16.56 66.197 25.896 ;
     RECT  64.595 0.048 66.733 0.072 ;
     RECT  66.089 1.728 66.841 7.56 ;
     RECT  66.841 1.68 67.208 7.56 ;
     RECT  66.089 8.832 67.208 10.152 ;
     RECT  66.125 14.496 67.208 14.52 ;
     RECT  66.197 16.608 67.208 25.896 ;
     RECT  67.208 1.68 67.504 25.896 ;
     RECT  66.733 0.048 67.525 0.6 ;
     RECT  67.504 1.68 67.525 6.888 ;
     RECT  67.504 16.56 67.667 25.896 ;
     RECT  67.504 9.36 67.709 10.152 ;
     RECT  67.525 0.048 67.955 6.888 ;
     RECT  67.955 1.728 68.033 6.888 ;
     RECT  67.667 16.656 68.501 25.896 ;
     RECT  67.955 0.048 68.545 0.6 ;
     RECT  68.033 1.728 68.717 6.648 ;
     RECT  68.501 17.088 68.753 25.896 ;
     RECT  68.717 1.728 68.825 5.784 ;
     RECT  68.825 1.728 69.077 5.688 ;
     RECT  69.077 1.776 69.185 5.688 ;
     RECT  68.545 0.048 69.299 0.168 ;
     RECT  69.185 1.776 69.329 5.256 ;
     RECT  69.329 2.064 69.437 5.256 ;
     RECT  68.753 17.184 69.545 25.896 ;
     RECT  69.545 17.184 69.653 17.208 ;
     RECT  67.709 9.888 69.833 10.152 ;
     RECT  69.437 2.256 70.121 5.256 ;
     RECT  69.833 10.08 70.121 10.152 ;
     RECT  69.545 18.432 70.121 25.896 ;
     RECT  70.121 4.176 70.193 5.256 ;
     RECT  70.121 10.128 70.301 10.152 ;
     RECT  70.193 4.176 70.445 4.488 ;
     RECT  70.121 2.256 70.553 3.048 ;
     RECT  70.553 3.024 70.661 3.048 ;
     RECT  70.445 4.464 70.661 4.488 ;
     RECT  70.121 18.72 70.661 25.896 ;
     RECT  70.661 19.536 70.805 25.896 ;
     RECT  70.805 19.68 71.453 25.896 ;
     RECT  71.453 20.64 72.608 25.896 ;
     RECT  72.608 2.148 72.712 25.896 ;
     RECT  72.712 2.418 72.904 25.896 ;
     RECT  72.904 20.88 76.709 25.896 ;
     RECT  76.709 20.88 78.008 23.016 ;
     RECT  76.709 24.192 78.008 25.896 ;
     RECT  78.008 2.148 78.077 25.896 ;
     RECT  78.077 2.148 78.112 25.704 ;
     RECT  78.112 2.418 78.304 25.704 ;
     RECT  78.304 20.88 78.689 21.432 ;
     RECT  78.304 24.192 78.689 25.704 ;
     RECT  78.689 24.192 78.905 24.888 ;
     RECT  78.689 20.88 79.553 20.904 ;
     RECT  78.905 24.192 80.273 24.84 ;
     RECT  78.304 22.752 80.309 22.776 ;
     RECT  80.273 24.192 80.957 24.792 ;
     RECT  80.957 24.768 81.497 24.792 ;
     RECT  83.408 2.148 83.512 23.772 ;
     RECT  83.512 2.418 83.704 23.502 ;
    LAYER M5 ;
     RECT  16.08 0.016 69.192 0.037 ;
     RECT  16.08 0.037 69.288 0.179 ;
     RECT  16.08 0.179 69.096 1.763 ;
     RECT  16.464 1.763 69.096 1.811 ;
     RECT  16.464 1.811 68.904 1.859 ;
     RECT  2.4 2.137 2.52 2.151 ;
     RECT  7.8 2.137 7.92 2.151 ;
     RECT  13.2 2.137 13.32 2.151 ;
     RECT  72.6 2.137 72.72 2.151 ;
     RECT  78 2.137 78.12 2.151 ;
     RECT  83.4 2.137 83.52 2.151 ;
     RECT  19.92 1.859 68.808 2.243 ;
     RECT  16.464 1.859 18.912 2.291 ;
     RECT  55.728 2.243 57.288 2.579 ;
     RECT  55.824 2.579 57.288 2.675 ;
     RECT  31.824 2.243 52.488 2.819 ;
     RECT  21.744 2.243 30.408 2.867 ;
     RECT  21.84 2.867 30.408 2.915 ;
     RECT  31.824 2.819 40.776 3.155 ;
     RECT  22.224 2.915 30.408 3.395 ;
     RECT  16.848 2.291 16.872 3.443 ;
     RECT  53.616 2.243 53.64 3.443 ;
     RECT  41.808 2.819 52.488 3.779 ;
     RECT  55.92 2.675 57.288 3.877 ;
     RECT  47.856 3.779 52.488 3.923 ;
     RECT  39.792 3.155 40.776 3.973 ;
     RECT  52.464 3.923 52.488 3.973 ;
     RECT  58.416 2.243 60.552 3.973 ;
     RECT  61.584 2.243 62.28 3.973 ;
     RECT  23.664 3.395 30.408 4.019 ;
     RECT  31.824 3.155 38.472 4.019 ;
     RECT  55.92 3.877 57.432 4.019 ;
     RECT  58.416 3.973 62.28 4.019 ;
     RECT  63.696 2.243 68.424 4.019 ;
     RECT  39.792 3.973 40.824 4.021 ;
     RECT  41.808 3.779 46.536 4.021 ;
     RECT  65.424 4.019 68.424 4.307 ;
     RECT  39.792 4.021 46.536 4.403 ;
     RECT  23.664 4.019 24.936 4.405 ;
     RECT  26.16 4.019 30.408 4.595 ;
     RECT  32.208 4.019 38.472 4.595 ;
     RECT  52.464 3.973 53.112 4.595 ;
     RECT  58.608 4.019 62.28 4.595 ;
     RECT  63.696 4.019 64.296 4.643 ;
     RECT  34.608 4.595 38.472 4.645 ;
     RECT  39.792 4.403 40.776 4.645 ;
     RECT  32.688 4.595 33.192 4.691 ;
     RECT  47.856 3.923 51.432 4.931 ;
     RECT  26.16 4.595 29.832 5.075 ;
     RECT  32.688 4.691 32.712 5.123 ;
     RECT  26.16 5.075 26.184 5.171 ;
     RECT  56.064 4.019 57.432 5.219 ;
     RECT  58.848 4.595 62.112 5.267 ;
     RECT  34.608 4.645 40.776 5.461 ;
     RECT  41.76 4.403 46.536 5.461 ;
     RECT  18.144 2.291 18.912 5.605 ;
     RECT  20.304 2.243 20.424 5.605 ;
     RECT  48.144 4.931 51.432 5.699 ;
     RECT  18.144 5.605 20.424 5.747 ;
     RECT  34.608 5.461 46.536 5.747 ;
     RECT  59.472 5.267 62.112 5.747 ;
     RECT  63.888 4.643 64.008 5.747 ;
     RECT  65.52 4.307 68.424 5.747 ;
     RECT  63.984 5.747 64.008 5.795 ;
     RECT  27.504 5.075 29.832 5.843 ;
     RECT  48.144 5.699 49.992 5.939 ;
     RECT  52.464 4.595 52.872 5.939 ;
     RECT  34.8 5.747 46.536 5.987 ;
     RECT  21.792 4.501 21.816 5.989 ;
     RECT  23.328 4.405 24.936 5.989 ;
     RECT  21.696 5.989 21.816 6.035 ;
     RECT  52.464 5.939 52.632 6.035 ;
     RECT  23.328 5.989 25.8 6.037 ;
     RECT  34.8 5.987 46.392 6.083 ;
     RECT  48.144 5.939 49.704 6.181 ;
     RECT  51 5.699 51.432 6.181 ;
     RECT  52.464 6.035 52.488 6.181 ;
     RECT  54.048 5.893 54.072 6.229 ;
     RECT  56.4 5.219 56.712 6.229 ;
     RECT  65.52 5.747 67.512 6.323 ;
     RECT  36.672 6.083 46.392 6.467 ;
     RECT  65.712 6.323 67.512 6.467 ;
     RECT  53.952 6.229 54.072 6.563 ;
     RECT  18.6 5.747 20.424 6.611 ;
     RECT  23.184 6.037 25.8 6.613 ;
     RECT  32.016 6.517 32.04 6.709 ;
     RECT  55.536 6.229 56.712 6.805 ;
     RECT  51 6.181 52.488 6.901 ;
     RECT  28.272 5.843 29.832 6.947 ;
     RECT  53.952 6.563 53.976 6.947 ;
     RECT  50.88 6.901 52.488 7.091 ;
     RECT  60.288 5.747 62.112 7.139 ;
     RECT  38.448 6.467 46.392 7.187 ;
     RECT  21.696 6.035 21.72 7.381 ;
     RECT  23.184 6.613 26.04 7.381 ;
     RECT  47.376 6.181 49.704 7.427 ;
     RECT  66.624 6.467 67.512 7.475 ;
     RECT  39.024 7.187 46.392 7.573 ;
     RECT  47.376 7.427 49.272 7.573 ;
     RECT  39.024 7.573 49.272 7.859 ;
     RECT  55.536 6.805 57.288 7.861 ;
     RECT  60.288 7.139 60.696 7.907 ;
     RECT  34.8 6.083 35.112 7.909 ;
     RECT  21.696 7.381 26.04 7.957 ;
     RECT  27.024 6.229 27.048 7.957 ;
     RECT  39.024 7.859 45.912 8.003 ;
     RECT  58.8 6.805 58.824 8.003 ;
     RECT  51 7.091 52.488 8.149 ;
     RECT  21.696 7.957 27.048 8.195 ;
     RECT  34.704 7.909 35.112 8.195 ;
     RECT  36.672 6.467 37.368 8.291 ;
     RECT  28.368 6.947 29.832 8.389 ;
     RECT  54.816 7.861 57.288 8.437 ;
     RECT  32.016 6.709 32.76 8.483 ;
     RECT  36.672 8.291 36.744 8.483 ;
     RECT  61.68 7.139 62.112 8.627 ;
     RECT  39.024 8.003 43.56 8.723 ;
     RECT  50.4 8.149 52.488 8.869 ;
     RECT  53.712 8.149 53.736 8.869 ;
     RECT  39.072 8.723 43.56 8.963 ;
     RECT  47.376 7.859 49.272 8.963 ;
     RECT  32.736 8.483 32.76 9.011 ;
     RECT  39.072 8.963 40.872 9.011 ;
     RECT  50.4 8.869 53.736 9.061 ;
     RECT  54.816 8.437 57.624 9.061 ;
     RECT  60.672 7.907 60.696 9.541 ;
     RECT  42.144 8.963 43.56 9.923 ;
     RECT  39.072 9.011 40.512 10.597 ;
     RECT  42.144 9.923 42.744 10.597 ;
     RECT  36.72 8.483 36.744 10.883 ;
     RECT  44.64 8.003 45.912 10.883 ;
     RECT  38.016 9.061 38.04 10.885 ;
     RECT  39.072 10.597 42.744 10.885 ;
     RECT  60.24 9.541 60.696 10.931 ;
     RECT  38.016 10.885 42.744 11.123 ;
     RECT  59.232 8.341 59.256 12.035 ;
     RECT  60.24 10.931 60.264 12.757 ;
     RECT  28.368 8.389 30.216 12.995 ;
     RECT  39.072 11.123 42.744 13.187 ;
     RECT  45.6 10.883 45.912 14.101 ;
     RECT  47.376 8.963 47.496 14.101 ;
     RECT  50.4 9.061 57.624 14.197 ;
     RECT  39.072 13.187 42.36 14.291 ;
     RECT  45.6 14.101 47.496 14.341 ;
     RECT  39.072 14.291 42.072 14.629 ;
     RECT  34.8 8.195 35.112 14.677 ;
     RECT  44.64 14.341 47.496 14.677 ;
     RECT  44.64 14.677 47.592 14.773 ;
     RECT  48.864 8.963 49.272 14.773 ;
     RECT  59.52 12.757 60.264 15.061 ;
     RECT  61.8 8.627 62.112 15.061 ;
     RECT  28.368 12.995 29.976 15.205 ;
     RECT  38.016 11.123 38.04 15.205 ;
     RECT  39.024 14.629 42.072 15.205 ;
     RECT  65.808 14.725 65.832 15.301 ;
     RECT  34.272 14.677 35.112 15.349 ;
     RECT  64.32 14.197 64.344 15.349 ;
     RECT  32.4 14.869 32.424 15.397 ;
     RECT  38.016 15.205 42.072 15.397 ;
     RECT  43.2 15.349 43.224 15.589 ;
     RECT  43.2 15.589 43.272 15.685 ;
     RECT  32.208 15.397 32.424 15.877 ;
     RECT  38.016 15.397 42.216 15.877 ;
     RECT  59.52 15.061 62.112 15.877 ;
     RECT  43.2 15.685 43.416 15.925 ;
     RECT  44.64 14.773 49.272 15.925 ;
     RECT  36.912 15.925 36.936 15.973 ;
     RECT  37.968 15.877 42.216 15.973 ;
     RECT  36.912 15.973 42.216 16.069 ;
     RECT  27.84 15.205 29.976 16.117 ;
     RECT  36.864 16.069 42.216 16.165 ;
     RECT  43.2 15.925 49.272 16.165 ;
     RECT  27.744 16.117 29.976 16.213 ;
     RECT  22.56 8.195 26.376 16.261 ;
     RECT  27.744 16.213 30.216 16.261 ;
     RECT  34.272 15.349 35.64 16.357 ;
     RECT  36.864 16.165 49.272 16.357 ;
     RECT  50.4 14.197 57.96 16.453 ;
     RECT  18.6 6.611 19.512 16.501 ;
     RECT  32.208 15.877 32.472 16.501 ;
     RECT  34.272 16.357 49.272 16.501 ;
     RECT  50.4 16.453 58.056 16.501 ;
     RECT  59.52 15.877 62.616 16.501 ;
     RECT  22.56 16.261 30.216 16.549 ;
     RECT  31.968 16.501 49.272 16.549 ;
     RECT  50.352 16.501 62.616 16.549 ;
     RECT  67.2 7.475 67.512 16.549 ;
     RECT  22.56 16.549 62.616 16.597 ;
     RECT  22.08 16.597 62.616 16.981 ;
     RECT  64.32 15.349 64.536 16.981 ;
     RECT  65.52 15.301 65.832 16.981 ;
     RECT  20.88 17.029 20.904 17.125 ;
     RECT  22.08 16.981 62.664 17.125 ;
     RECT  20.88 17.125 62.664 17.221 ;
     RECT  0.192 13.045 0.216 17.363 ;
     RECT  18.6 16.501 19.8 17.509 ;
     RECT  17.472 16.837 17.496 17.605 ;
     RECT  18.48 17.509 19.8 17.605 ;
     RECT  64.32 16.981 65.832 17.653 ;
     RECT  67.2 16.549 67.656 17.653 ;
     RECT  17.472 17.605 19.8 17.797 ;
     RECT  20.88 17.221 62.76 17.797 ;
     RECT  17.472 17.797 62.76 17.941 ;
     RECT  17.28 17.941 62.76 18.229 ;
     RECT  64.32 17.653 67.656 18.229 ;
     RECT  17.28 18.229 67.656 18.517 ;
     RECT  68.976 18.133 69 18.517 ;
     RECT  16.944 18.517 67.656 18.757 ;
     RECT  16.944 18.757 67.944 19.285 ;
     RECT  68.976 18.517 69.384 19.285 ;
     RECT  16.944 19.285 69.384 19.669 ;
     RECT  15.552 20.725 15.576 21.155 ;
     RECT  16.944 19.669 70.152 21.683 ;
     RECT  16.944 21.683 25.704 21.731 ;
     RECT  26.736 21.683 70.152 21.731 ;
     RECT  48.24 21.731 59.784 21.779 ;
     RECT  60.816 21.731 70.152 21.925 ;
     RECT  17.28 21.731 25.704 21.971 ;
     RECT  48.24 21.779 57.96 21.971 ;
     RECT  48.24 21.971 57.768 22.211 ;
     RECT  17.28 21.971 25.608 22.259 ;
     RECT  59.52 21.779 59.784 22.499 ;
     RECT  59.52 22.499 59.544 22.547 ;
     RECT  26.736 21.731 47.112 22.835 ;
     RECT  48.24 22.211 57.48 23.317 ;
     RECT  17.472 22.259 25.608 23.365 ;
     RECT  48.24 23.317 58.152 23.365 ;
     RECT  60.816 21.925 70.248 23.557 ;
     RECT  48.144 23.365 58.152 23.605 ;
     RECT  72.6 2.151 72.912 23.653 ;
     RECT  2.4 2.151 2.712 23.769 ;
     RECT  7.8 2.151 8.112 23.769 ;
     RECT  13.2 2.151 13.512 23.769 ;
     RECT  72.24 23.653 72.912 23.769 ;
     RECT  78 2.151 78.312 23.769 ;
     RECT  83.4 2.151 83.712 23.769 ;
     RECT  2.4 23.769 2.52 23.783 ;
     RECT  7.8 23.769 7.92 23.783 ;
     RECT  13.2 23.769 13.32 23.783 ;
     RECT  59.856 23.557 70.248 23.783 ;
     RECT  72.24 23.769 72.72 23.783 ;
     RECT  78 23.769 78.12 23.783 ;
     RECT  83.4 23.769 83.52 23.783 ;
     RECT  27.504 22.835 47.112 23.797 ;
     RECT  72.24 23.783 72.264 23.843 ;
     RECT  26.832 23.797 47.112 23.893 ;
     RECT  48.144 23.605 58.344 23.893 ;
     RECT  17.232 23.365 25.608 23.941 ;
     RECT  26.832 23.893 58.344 23.941 ;
     RECT  15.984 24.037 16.008 24.179 ;
     RECT  17.232 23.941 58.344 24.181 ;
     RECT  59.856 23.783 66.408 24.181 ;
     RECT  17.232 24.181 66.408 25.141 ;
     RECT  67.488 23.783 70.248 25.141 ;
     RECT  17.232 25.141 70.248 25.285 ;
     RECT  16.032 25.285 16.056 25.523 ;
     RECT  17.04 25.285 70.248 25.872 ;
     RECT  27.84 25.872 27.864 25.907 ;
     RECT  18.912 1.859 19.92 2.243 ;
     RECT  18.912 2.243 20.304 5.605 ;
     RECT  20.424 2.243 21.744 2.867 ;
     RECT  30.408 2.243 31.824 4.019 ;
     RECT  52.488 2.243 53.616 3.443 ;
     RECT  57.288 2.243 58.416 3.877 ;
     RECT  60.552 2.243 61.584 3.973 ;
     RECT  62.28 2.243 63.696 4.595 ;
     RECT  16.872 2.291 18.144 3.443 ;
     RECT  40.776 2.819 41.808 3.973 ;
     RECT  20.424 2.867 21.84 2.915 ;
     RECT  38.472 3.155 39.792 4.645 ;
     RECT  22.224 3.395 23.664 4.405 ;
     RECT  52.488 3.443 53.112 3.973 ;
     RECT  46.536 3.779 47.856 4.931 ;
     RECT  57.432 3.877 58.416 4.019 ;
     RECT  51.432 3.923 52.464 6.181 ;
     RECT  40.824 3.973 41.808 4.021 ;
     RECT  24.936 4.019 26.16 5.171 ;
     RECT  57.432 4.019 58.608 4.595 ;
     RECT  64.296 4.019 65.424 4.307 ;
     RECT  64.296 4.307 65.52 4.643 ;
     RECT  40.776 4.403 41.76 5.461 ;
     RECT  22.224 4.405 23.328 4.501 ;
     RECT  20.424 4.501 21.792 5.989 ;
     RECT  21.816 4.501 23.328 6.035 ;
     RECT  33.192 4.595 34.608 4.691 ;
     RECT  52.872 4.595 53.112 5.893 ;
     RECT  57.432 4.595 58.848 5.219 ;
     RECT  64.008 4.643 65.52 5.795 ;
     RECT  46.536 4.931 48.144 5.987 ;
     RECT  26.184 5.075 27.504 5.171 ;
     RECT  24.936 5.171 27.504 5.843 ;
     RECT  56.064 5.219 56.4 6.229 ;
     RECT  49.992 5.699 51 5.939 ;
     RECT  59.472 5.747 60.288 6.805 ;
     RECT  24.936 5.843 28.272 5.989 ;
     RECT  52.872 5.893 54.048 5.939 ;
     RECT  49.704 5.939 51 6.901 ;
     RECT  52.632 5.939 54.048 6.035 ;
     RECT  46.392 5.987 48.144 6.181 ;
     RECT  20.424 5.989 21.696 6.611 ;
     RECT  25.8 5.989 28.272 6.229 ;
     RECT  21.72 6.035 23.328 6.037 ;
     RECT  52.488 6.035 54.048 6.229 ;
     RECT  21.72 6.037 23.184 7.381 ;
     RECT  46.392 6.181 47.376 7.573 ;
     RECT  25.8 6.229 27.024 6.613 ;
     RECT  27.048 6.229 28.272 6.947 ;
     RECT  52.488 6.229 53.952 6.947 ;
     RECT  54.072 6.229 55.536 6.563 ;
     RECT  37.368 6.467 38.448 7.187 ;
     RECT  53.976 6.563 55.536 6.947 ;
     RECT  26.04 6.613 27.024 7.957 ;
     RECT  57.288 6.805 58.8 8.003 ;
     RECT  58.824 6.805 60.288 7.907 ;
     RECT  49.704 6.901 50.88 7.091 ;
     RECT  27.048 6.947 28.368 8.195 ;
     RECT  52.488 6.947 55.536 7.861 ;
     RECT  49.704 7.091 51 7.427 ;
     RECT  60.696 7.139 61.68 8.627 ;
     RECT  49.272 7.427 51 8.149 ;
     RECT  45.912 7.859 47.376 14.101 ;
     RECT  52.488 7.861 54.816 8.149 ;
     RECT  58.824 7.907 60.672 8.003 ;
     RECT  43.56 8.003 44.64 9.923 ;
     RECT  57.288 8.003 57.624 8.437 ;
     RECT  59.232 8.003 60.672 8.341 ;
     RECT  49.272 8.149 50.4 16.501 ;
     RECT  52.488 8.149 53.712 8.869 ;
     RECT  53.736 8.149 54.816 9.061 ;
     RECT  36.744 8.291 37.368 9.061 ;
     RECT  59.256 8.341 60.672 9.541 ;
     RECT  60.696 8.627 61.8 10.931 ;
     RECT  39.024 8.723 39.072 9.061 ;
     RECT  40.872 8.963 42.144 9.011 ;
     RECT  47.496 8.963 48.864 14.677 ;
     RECT  36.744 9.061 38.016 10.883 ;
     RECT  38.04 9.061 39.072 10.885 ;
     RECT  59.256 9.541 60.24 12.035 ;
     RECT  38.04 11.123 39.072 14.629 ;
     RECT  59.52 12.035 60.24 12.757 ;
     RECT  42.072 14.291 42.36 15.349 ;
     RECT  38.04 14.629 39.024 15.205 ;
     RECT  47.592 14.677 48.864 14.773 ;
     RECT  64.344 14.725 65.808 15.301 ;
     RECT  65.832 14.725 67.2 17.653 ;
     RECT  26.376 15.205 27.84 16.117 ;
     RECT  64.344 15.301 65.52 15.349 ;
     RECT  42.072 15.349 43.2 15.397 ;
     RECT  43.224 15.349 44.64 15.589 ;
     RECT  64.536 15.349 65.52 16.981 ;
     RECT  42.216 15.397 43.2 16.165 ;
     RECT  43.272 15.589 44.64 15.685 ;
     RECT  43.416 15.685 44.64 15.925 ;
     RECT  35.64 15.925 36.912 16.069 ;
     RECT  36.936 15.925 37.968 15.973 ;
     RECT  35.64 16.069 36.864 16.357 ;
     RECT  26.376 16.117 27.744 16.261 ;
     RECT  58.056 16.453 59.52 16.501 ;
     RECT  49.272 16.501 50.352 16.549 ;
     RECT  17.496 16.837 18.6 17.509 ;
     RECT  19.8 17.029 20.88 17.797 ;
     RECT  20.904 17.029 22.08 17.125 ;
     RECT  17.496 17.509 18.48 17.605 ;
     RECT  67.656 18.133 68.976 18.757 ;
     RECT  67.944 18.757 68.976 19.285 ;
     RECT  15.576 20.725 16.944 21.155 ;
     RECT  25.704 21.683 26.736 21.971 ;
     RECT  47.112 21.731 48.24 23.365 ;
     RECT  59.784 21.731 60.816 22.499 ;
     RECT  25.608 21.971 26.736 22.835 ;
     RECT  57.768 21.971 57.96 22.211 ;
     RECT  57.48 22.211 57.96 23.317 ;
     RECT  17.28 22.259 17.472 23.365 ;
     RECT  59.544 22.499 60.816 22.547 ;
     RECT  59.52 22.547 60.816 23.317 ;
     RECT  25.608 22.835 27.504 23.797 ;
     RECT  58.152 23.317 60.816 23.557 ;
     RECT  47.112 23.365 48.144 23.893 ;
     RECT  58.152 23.557 59.856 23.605 ;
     RECT  58.344 23.605 59.856 24.181 ;
     RECT  66.408 23.783 67.488 25.141 ;
     RECT  25.608 23.797 26.832 23.941 ;
     RECT  16.008 24.037 17.232 24.179 ;
     RECT  16.032 24.179 17.232 25.285 ;
     RECT  16.056 25.285 17.04 25.523 ;
  END
END ot_qkvd_ke_ti
END LIBRARY
